VERSION 5.7 ;
  NOWIREEXTENSIONATPIN ON ;
  DIVIDERCHAR "/" ;
  BUSBITCHARS "[]" ;
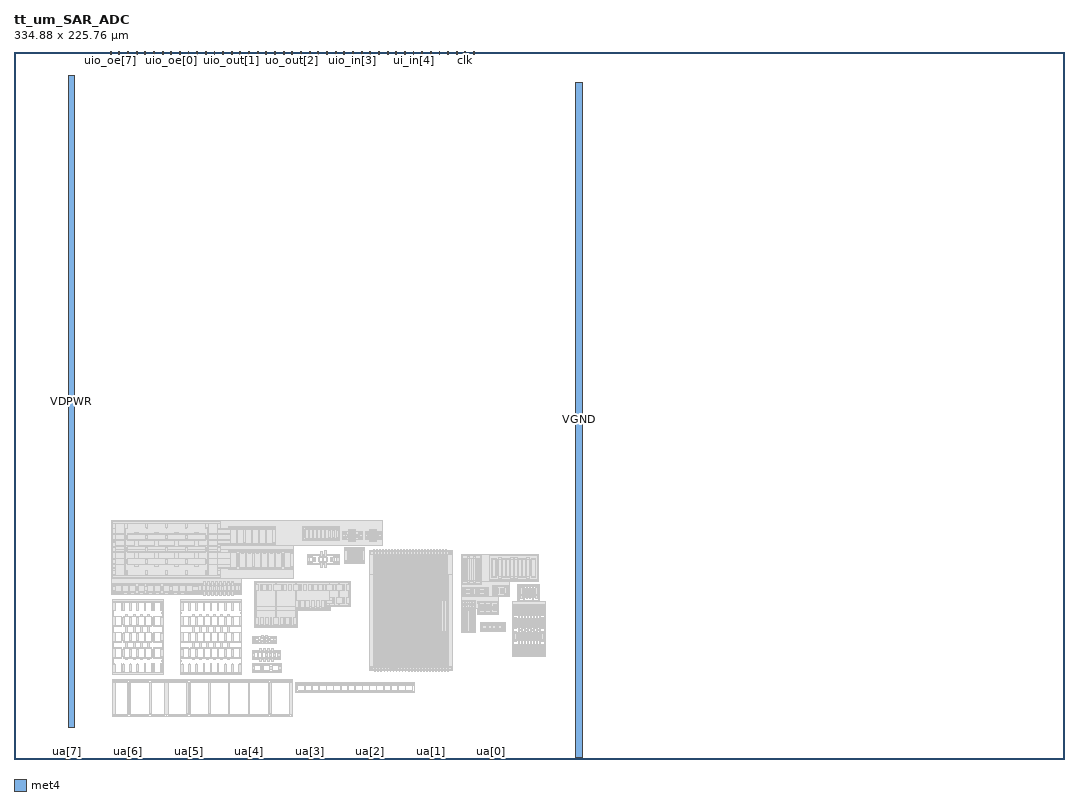
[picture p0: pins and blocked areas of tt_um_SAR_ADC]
MACRO tt_um_SAR_ADC
  CLASS BLOCK ;
  FOREIGN tt_um_SAR_ADC ;
  ORIGIN 0.000 0.000 ;
  SIZE 334.880 BY 225.760 ;
  PIN clk
    DIRECTION INPUT ;
    USE SIGNAL ;
    PORT
      LAYER met4 ;
        RECT 143.830 224.760 144.130 225.760 ;
    END
  END clk
  PIN ena
    DIRECTION INPUT ;
    USE SIGNAL ;
    PORT
      LAYER met4 ;
        RECT 146.590 224.760 146.890 225.760 ;
    END
  END ena
  PIN rst_n
    DIRECTION INPUT ;
    USE SIGNAL ;
    PORT
      LAYER met4 ;
        RECT 141.070 224.760 141.370 225.760 ;
    END
  END rst_n
  PIN ua[0]
    DIRECTION INOUT ;
    USE SIGNAL ;
    PORT
      LAYER met4 ;
        RECT 151.810 0.000 152.710 1.000 ;
    END
  END ua[0]
  PIN ua[1]
    DIRECTION INOUT ;
    USE SIGNAL ;
    PORT
      LAYER met4 ;
        RECT 132.490 0.000 133.390 1.000 ;
    END
  END ua[1]
  PIN ua[2]
    DIRECTION INOUT ;
    USE SIGNAL ;
    PORT
      LAYER met4 ;
        RECT 113.170 0.000 114.070 1.000 ;
    END
  END ua[2]
  PIN ua[3]
    DIRECTION INOUT ;
    USE SIGNAL ;
    PORT
      LAYER met4 ;
        RECT 93.850 0.000 94.750 1.000 ;
    END
  END ua[3]
  PIN ua[4]
    DIRECTION INOUT ;
    USE SIGNAL ;
    PORT
      LAYER met4 ;
        RECT 74.530 0.000 75.430 1.000 ;
    END
  END ua[4]
  PIN ua[5]
    DIRECTION INOUT ;
    USE SIGNAL ;
    PORT
      LAYER met4 ;
        RECT 55.210 0.000 56.110 1.000 ;
    END
  END ua[5]
  PIN ua[6]
    DIRECTION INOUT ;
    USE SIGNAL ;
    PORT
      LAYER met4 ;
        RECT 35.890 0.000 36.790 1.000 ;
    END
  END ua[6]
  PIN ua[7]
    DIRECTION INOUT ;
    USE SIGNAL ;
    PORT
      LAYER met4 ;
        RECT 16.570 0.000 17.470 1.000 ;
    END
  END ua[7]
  PIN ui_in[0]
    DIRECTION INPUT ;
    USE SIGNAL ;
    PORT
      LAYER met4 ;
        RECT 138.310 224.760 138.610 225.760 ;
    END
  END ui_in[0]
  PIN ui_in[1]
    DIRECTION INPUT ;
    USE SIGNAL ;
    PORT
      LAYER met4 ;
        RECT 135.550 224.760 135.850 225.760 ;
    END
  END ui_in[1]
  PIN ui_in[2]
    DIRECTION INPUT ;
    USE SIGNAL ;
    PORT
      LAYER met4 ;
        RECT 132.790 224.760 133.090 225.760 ;
    END
  END ui_in[2]
  PIN ui_in[3]
    DIRECTION INPUT ;
    USE SIGNAL ;
    PORT
      LAYER met4 ;
        RECT 130.030 224.760 130.330 225.760 ;
    END
  END ui_in[3]
  PIN ui_in[4]
    DIRECTION INPUT ;
    USE SIGNAL ;
    PORT
      LAYER met4 ;
        RECT 127.270 224.760 127.570 225.760 ;
    END
  END ui_in[4]
  PIN ui_in[5]
    DIRECTION INPUT ;
    USE SIGNAL ;
    PORT
      LAYER met4 ;
        RECT 124.510 224.760 124.810 225.760 ;
    END
  END ui_in[5]
  PIN ui_in[6]
    DIRECTION INPUT ;
    USE SIGNAL ;
    PORT
      LAYER met4 ;
        RECT 121.750 224.760 122.050 225.760 ;
    END
  END ui_in[6]
  PIN ui_in[7]
    DIRECTION INPUT ;
    USE SIGNAL ;
    PORT
      LAYER met4 ;
        RECT 118.990 224.760 119.290 225.760 ;
    END
  END ui_in[7]
  PIN uio_in[0]
    DIRECTION INPUT ;
    USE SIGNAL ;
    PORT
      LAYER met4 ;
        RECT 116.230 224.760 116.530 225.760 ;
    END
  END uio_in[0]
  PIN uio_in[1]
    DIRECTION INPUT ;
    USE SIGNAL ;
    PORT
      LAYER met4 ;
        RECT 113.470 224.760 113.770 225.760 ;
    END
  END uio_in[1]
  PIN uio_in[2]
    DIRECTION INPUT ;
    USE SIGNAL ;
    PORT
      LAYER met4 ;
        RECT 110.710 224.760 111.010 225.760 ;
    END
  END uio_in[2]
  PIN uio_in[3]
    DIRECTION INPUT ;
    USE SIGNAL ;
    PORT
      LAYER met4 ;
        RECT 107.950 224.760 108.250 225.760 ;
    END
  END uio_in[3]
  PIN uio_in[4]
    DIRECTION INPUT ;
    USE SIGNAL ;
    PORT
      LAYER met4 ;
        RECT 105.190 224.760 105.490 225.760 ;
    END
  END uio_in[4]
  PIN uio_in[5]
    DIRECTION INPUT ;
    USE SIGNAL ;
    PORT
      LAYER met4 ;
        RECT 102.430 224.760 102.730 225.760 ;
    END
  END uio_in[5]
  PIN uio_in[6]
    DIRECTION INPUT ;
    USE SIGNAL ;
    PORT
      LAYER met4 ;
        RECT 99.670 224.760 99.970 225.760 ;
    END
  END uio_in[6]
  PIN uio_in[7]
    DIRECTION INPUT ;
    USE SIGNAL ;
    PORT
      LAYER met4 ;
        RECT 96.910 224.760 97.210 225.760 ;
    END
  END uio_in[7]
  PIN uio_oe[0]
    DIRECTION OUTPUT ;
    USE SIGNAL ;
    PORT
      LAYER met4 ;
        RECT 49.990 224.760 50.290 225.760 ;
    END
  END uio_oe[0]
  PIN uio_oe[1]
    DIRECTION OUTPUT ;
    USE SIGNAL ;
    PORT
      LAYER met4 ;
        RECT 47.230 224.760 47.530 225.760 ;
    END
  END uio_oe[1]
  PIN uio_oe[2]
    DIRECTION OUTPUT ;
    USE SIGNAL ;
    PORT
      LAYER met4 ;
        RECT 44.470 224.760 44.770 225.760 ;
    END
  END uio_oe[2]
  PIN uio_oe[3]
    DIRECTION OUTPUT ;
    USE SIGNAL ;
    PORT
      LAYER met4 ;
        RECT 41.710 224.760 42.010 225.760 ;
    END
  END uio_oe[3]
  PIN uio_oe[4]
    DIRECTION OUTPUT ;
    USE SIGNAL ;
    PORT
      LAYER met4 ;
        RECT 38.950 224.760 39.250 225.760 ;
    END
  END uio_oe[4]
  PIN uio_oe[5]
    DIRECTION OUTPUT ;
    USE SIGNAL ;
    PORT
      LAYER met4 ;
        RECT 36.190 224.760 36.490 225.760 ;
    END
  END uio_oe[5]
  PIN uio_oe[6]
    DIRECTION OUTPUT ;
    USE SIGNAL ;
    PORT
      LAYER met4 ;
        RECT 33.430 224.760 33.730 225.760 ;
    END
  END uio_oe[6]
  PIN uio_oe[7]
    DIRECTION OUTPUT ;
    USE SIGNAL ;
    PORT
      LAYER met4 ;
        RECT 30.670 224.760 30.970 225.760 ;
    END
  END uio_oe[7]
  PIN uio_out[0]
    DIRECTION OUTPUT ;
    USE SIGNAL ;
    PORT
      LAYER met4 ;
        RECT 72.070 224.760 72.370 225.760 ;
    END
  END uio_out[0]
  PIN uio_out[1]
    DIRECTION OUTPUT ;
    USE SIGNAL ;
    PORT
      LAYER met4 ;
        RECT 69.310 224.760 69.610 225.760 ;
    END
  END uio_out[1]
  PIN uio_out[2]
    DIRECTION OUTPUT ;
    USE SIGNAL ;
    PORT
      LAYER met4 ;
        RECT 66.550 224.760 66.850 225.760 ;
    END
  END uio_out[2]
  PIN uio_out[3]
    DIRECTION OUTPUT ;
    USE SIGNAL ;
    PORT
      LAYER met4 ;
        RECT 63.790 224.760 64.090 225.760 ;
    END
  END uio_out[3]
  PIN uio_out[4]
    DIRECTION OUTPUT ;
    USE SIGNAL ;
    PORT
      LAYER met4 ;
        RECT 61.030 224.760 61.330 225.760 ;
    END
  END uio_out[4]
  PIN uio_out[5]
    DIRECTION OUTPUT ;
    USE SIGNAL ;
    PORT
      LAYER met4 ;
        RECT 58.270 224.760 58.570 225.760 ;
    END
  END uio_out[5]
  PIN uio_out[6]
    DIRECTION OUTPUT ;
    USE SIGNAL ;
    PORT
      LAYER met4 ;
        RECT 55.510 224.760 55.810 225.760 ;
    END
  END uio_out[6]
  PIN uio_out[7]
    DIRECTION OUTPUT ;
    USE SIGNAL ;
    PORT
      LAYER met4 ;
        RECT 52.750 224.760 53.050 225.760 ;
    END
  END uio_out[7]
  PIN uo_out[0]
    DIRECTION OUTPUT ;
    USE SIGNAL ;
    PORT
      LAYER met4 ;
        RECT 94.150 224.760 94.450 225.760 ;
    END
  END uo_out[0]
  PIN uo_out[1]
    DIRECTION OUTPUT ;
    USE SIGNAL ;
    PORT
      LAYER met4 ;
        RECT 91.390 224.760 91.690 225.760 ;
    END
  END uo_out[1]
  PIN uo_out[2]
    DIRECTION OUTPUT ;
    USE SIGNAL ;
    PORT
      LAYER met4 ;
        RECT 88.630 224.760 88.930 225.760 ;
    END
  END uo_out[2]
  PIN uo_out[3]
    DIRECTION OUTPUT ;
    USE SIGNAL ;
    PORT
      LAYER met4 ;
        RECT 85.870 224.760 86.170 225.760 ;
    END
  END uo_out[3]
  PIN uo_out[4]
    DIRECTION OUTPUT ;
    USE SIGNAL ;
    PORT
      LAYER met4 ;
        RECT 83.110 224.760 83.410 225.760 ;
    END
  END uo_out[4]
  PIN uo_out[5]
    DIRECTION OUTPUT ;
    USE SIGNAL ;
    PORT
      LAYER met4 ;
        RECT 80.350 224.760 80.650 225.760 ;
    END
  END uo_out[5]
  PIN uo_out[6]
    DIRECTION OUTPUT ;
    USE SIGNAL ;
    PORT
      LAYER met4 ;
        RECT 77.590 224.760 77.890 225.760 ;
    END
  END uo_out[6]
  PIN uo_out[7]
    DIRECTION OUTPUT ;
    USE SIGNAL ;
    PORT
      LAYER met4 ;
        RECT 74.830 224.760 75.130 225.760 ;
    END
  END uo_out[7]
  PIN VDPWR
    DIRECTION INOUT ;
    USE POWER ;
    PORT
      LAYER met4 ;
        RECT 17.400 9.940 19.400 218.050 ;
    END
  END VDPWR
  PIN VGND
    DIRECTION INOUT ;
    USE GROUND ;
    PORT
      LAYER met4 ;
        RECT 179.160 0.385 181.160 215.890 ;
    END
  END VGND
  OBS
      LAYER nwell ;
        RECT 31.225 68.130 117.555 76.010 ;
        RECT 31.225 66.700 89.210 68.130 ;
        RECT 31.225 57.720 89.215 66.700 ;
        RECT 31.225 52.520 72.515 57.720 ;
      LAYER pwell ;
        RECT 76.825 48.615 107.165 56.625 ;
        RECT 76.825 47.485 100.885 48.615 ;
        RECT 76.825 42.055 90.275 47.485 ;
      LAYER nwell ;
        RECT 113.240 28.260 139.870 66.450 ;
        RECT 142.580 56.720 167.245 65.225 ;
        RECT 142.580 51.740 158.070 56.720 ;
      LAYER pwell ;
        RECT 160.720 55.135 167.650 55.565 ;
      LAYER nwell ;
        RECT 142.580 47.900 154.585 51.740 ;
      LAYER pwell ;
        RECT 160.720 50.575 161.150 55.135 ;
        RECT 161.340 51.485 162.280 54.245 ;
        RECT 162.290 51.485 163.230 54.245 ;
        RECT 163.240 51.485 164.180 54.245 ;
        RECT 164.190 51.485 165.130 54.245 ;
        RECT 165.140 51.485 166.080 54.245 ;
        RECT 166.090 51.485 167.030 54.245 ;
        RECT 167.220 50.575 167.650 55.135 ;
        RECT 160.720 49.600 167.650 50.575 ;
        RECT 142.795 47.135 147.065 47.565 ;
        RECT 142.795 40.835 143.225 47.135 ;
        RECT 143.415 41.355 144.355 46.615 ;
        RECT 144.545 40.835 145.315 47.135 ;
        RECT 145.505 41.355 146.445 46.615 ;
        RECT 146.635 40.835 147.065 47.135 ;
      LAYER nwell ;
        RECT 147.915 46.165 154.585 47.900 ;
      LAYER pwell ;
        RECT 158.940 49.170 169.670 49.600 ;
        RECT 142.795 40.405 147.065 40.835 ;
        RECT 148.715 43.025 156.625 43.455 ;
        RECT 148.715 41.225 149.145 43.025 ;
        RECT 150.985 42.505 151.285 43.025 ;
        RECT 153.755 42.505 154.055 43.025 ;
        RECT 149.185 41.745 150.975 42.505 ;
        RECT 150.985 41.745 154.055 42.505 ;
        RECT 154.065 41.745 155.855 42.505 ;
        RECT 150.985 41.225 151.285 41.745 ;
        RECT 153.755 41.225 154.055 41.745 ;
        RECT 156.195 41.225 156.625 43.025 ;
        RECT 148.715 40.795 156.625 41.225 ;
        RECT 158.940 33.180 159.370 49.170 ;
        RECT 159.560 45.890 160.500 48.650 ;
        RECT 160.510 45.890 161.450 48.650 ;
        RECT 161.460 45.890 162.400 48.650 ;
        RECT 162.410 45.890 163.350 48.650 ;
        RECT 163.360 45.890 164.300 48.650 ;
        RECT 164.310 45.890 165.250 48.650 ;
        RECT 165.260 45.890 166.200 48.650 ;
        RECT 166.210 45.890 167.150 48.650 ;
        RECT 167.160 45.890 168.100 48.650 ;
        RECT 168.110 45.890 169.050 48.650 ;
        RECT 159.560 41.930 160.500 44.690 ;
        RECT 160.510 41.930 161.450 44.690 ;
        RECT 161.460 41.930 162.400 44.690 ;
        RECT 162.410 41.930 163.350 44.690 ;
        RECT 163.360 41.930 164.300 44.690 ;
        RECT 164.310 41.930 165.250 44.690 ;
        RECT 165.260 41.930 166.200 44.690 ;
        RECT 166.210 41.930 167.150 44.690 ;
        RECT 167.160 41.930 168.100 44.690 ;
        RECT 168.110 41.930 169.050 44.690 ;
        RECT 159.560 37.660 160.500 40.420 ;
        RECT 160.510 37.660 161.450 40.420 ;
        RECT 161.460 37.660 162.400 40.420 ;
        RECT 162.410 37.660 163.350 40.420 ;
        RECT 163.360 37.660 164.300 40.420 ;
        RECT 164.310 37.660 165.250 40.420 ;
        RECT 165.260 37.660 166.200 40.420 ;
        RECT 166.210 37.660 167.150 40.420 ;
        RECT 167.160 37.660 168.100 40.420 ;
        RECT 168.110 37.660 169.050 40.420 ;
        RECT 159.560 33.700 160.500 36.460 ;
        RECT 160.510 33.700 161.450 36.460 ;
        RECT 161.460 33.700 162.400 36.460 ;
        RECT 162.410 33.700 163.350 36.460 ;
        RECT 163.360 33.700 164.300 36.460 ;
        RECT 164.310 33.700 165.250 36.460 ;
        RECT 165.260 33.700 166.200 36.460 ;
        RECT 166.210 33.700 167.150 36.460 ;
        RECT 167.160 33.700 168.100 36.460 ;
        RECT 168.110 33.700 169.050 36.460 ;
        RECT 169.240 33.180 169.670 49.170 ;
        RECT 158.940 32.750 169.670 33.180 ;
      LAYER li1 ;
        RECT 31.555 75.535 65.725 75.830 ;
        RECT 31.555 75.345 31.725 75.535 ;
        RECT 31.555 58.485 31.765 75.345 ;
        RECT 32.355 75.150 35.355 75.320 ;
        RECT 36.205 75.150 42.205 75.320 ;
        RECT 42.495 75.150 48.495 75.320 ;
        RECT 48.785 75.150 54.785 75.320 ;
        RECT 55.075 75.150 61.075 75.320 ;
        RECT 61.925 75.150 64.925 75.320 ;
        RECT 65.555 75.225 65.725 75.535 ;
        RECT 32.125 73.645 32.295 74.935 ;
        RECT 35.415 73.645 35.585 74.935 ;
        RECT 35.975 73.645 36.145 74.935 ;
        RECT 42.265 73.645 42.435 74.935 ;
        RECT 48.555 73.645 48.725 74.935 ;
        RECT 54.845 73.645 55.015 74.935 ;
        RECT 61.135 73.645 61.305 74.935 ;
        RECT 61.695 73.645 61.865 74.935 ;
        RECT 64.985 73.645 65.155 74.935 ;
        RECT 32.355 71.615 35.355 71.785 ;
        RECT 36.205 71.615 42.205 71.785 ;
        RECT 42.495 71.615 48.495 71.785 ;
        RECT 48.785 71.615 54.785 71.785 ;
        RECT 55.075 71.615 61.075 71.785 ;
        RECT 61.925 71.615 64.925 71.785 ;
        RECT 32.125 70.110 32.295 71.400 ;
        RECT 35.415 70.110 35.585 71.400 ;
        RECT 35.975 70.110 36.145 71.400 ;
        RECT 42.265 70.110 42.435 71.400 ;
        RECT 48.555 70.110 48.725 71.400 ;
        RECT 54.845 70.110 55.015 71.400 ;
        RECT 61.135 70.110 61.305 71.400 ;
        RECT 61.695 70.110 61.865 71.400 ;
        RECT 64.985 70.110 65.155 71.400 ;
        RECT 32.355 69.725 35.355 69.895 ;
        RECT 36.205 69.725 42.205 69.895 ;
        RECT 42.495 69.725 48.495 69.895 ;
        RECT 48.785 69.725 54.785 69.895 ;
        RECT 55.075 69.725 61.075 69.895 ;
        RECT 61.925 69.725 64.925 69.895 ;
        RECT 32.355 67.725 35.355 67.895 ;
        RECT 36.205 67.725 42.205 67.895 ;
        RECT 42.495 67.725 48.495 67.895 ;
        RECT 48.785 67.725 54.785 67.895 ;
        RECT 55.075 67.725 61.075 67.895 ;
        RECT 61.925 67.725 64.925 67.895 ;
        RECT 32.125 66.220 32.295 67.510 ;
        RECT 35.415 66.220 35.585 67.510 ;
        RECT 35.975 66.220 36.145 67.510 ;
        RECT 42.265 66.220 42.435 67.510 ;
        RECT 48.555 66.220 48.725 67.510 ;
        RECT 54.845 66.220 55.015 67.510 ;
        RECT 61.135 66.220 61.305 67.510 ;
        RECT 61.695 66.220 61.865 67.510 ;
        RECT 64.985 66.220 65.155 67.510 ;
        RECT 32.355 65.835 35.355 66.005 ;
        RECT 36.205 65.835 42.205 66.005 ;
        RECT 42.495 65.835 48.495 66.005 ;
        RECT 48.785 65.835 54.785 66.005 ;
        RECT 55.075 65.835 61.075 66.005 ;
        RECT 61.925 65.835 64.925 66.005 ;
        RECT 32.355 63.835 35.355 64.005 ;
        RECT 36.205 63.835 42.205 64.005 ;
        RECT 42.495 63.835 48.495 64.005 ;
        RECT 48.785 63.835 54.785 64.005 ;
        RECT 55.075 63.835 61.075 64.005 ;
        RECT 61.925 63.835 64.925 64.005 ;
        RECT 32.125 62.330 32.295 63.620 ;
        RECT 35.415 62.330 35.585 63.620 ;
        RECT 35.975 62.330 36.145 63.620 ;
        RECT 42.265 62.330 42.435 63.620 ;
        RECT 48.555 62.330 48.725 63.620 ;
        RECT 54.845 62.330 55.015 63.620 ;
        RECT 61.135 62.330 61.305 63.620 ;
        RECT 61.695 62.330 61.865 63.620 ;
        RECT 64.985 62.330 65.155 63.620 ;
        RECT 32.355 61.945 35.355 62.115 ;
        RECT 36.205 61.945 42.205 62.115 ;
        RECT 42.495 61.945 48.495 62.115 ;
        RECT 48.785 61.945 54.785 62.115 ;
        RECT 55.075 61.945 61.075 62.115 ;
        RECT 61.925 61.945 64.925 62.115 ;
        RECT 32.125 58.795 32.295 60.085 ;
        RECT 35.415 58.795 35.585 60.085 ;
        RECT 35.975 58.795 36.145 60.085 ;
        RECT 42.265 58.795 42.435 60.085 ;
        RECT 48.555 58.795 48.725 60.085 ;
        RECT 54.845 58.795 55.015 60.085 ;
        RECT 61.135 58.795 61.305 60.085 ;
        RECT 61.695 58.795 61.865 60.085 ;
        RECT 64.985 58.795 65.155 60.085 ;
        RECT 31.555 58.170 31.725 58.485 ;
        RECT 32.355 58.410 35.355 58.580 ;
        RECT 36.205 58.410 42.205 58.580 ;
        RECT 42.495 58.410 48.495 58.580 ;
        RECT 48.785 58.410 54.785 58.580 ;
        RECT 55.075 58.410 61.075 58.580 ;
        RECT 61.925 58.410 64.925 58.580 ;
        RECT 65.460 58.450 65.725 75.225 ;
        RECT 68.290 73.885 83.340 74.055 ;
        RECT 68.290 68.145 68.460 73.885 ;
        RECT 69.090 73.375 71.090 73.545 ;
        RECT 71.380 73.375 73.380 73.545 ;
        RECT 73.670 73.375 75.670 73.545 ;
        RECT 75.960 73.375 77.960 73.545 ;
        RECT 78.250 73.375 80.250 73.545 ;
        RECT 80.540 73.375 82.540 73.545 ;
        RECT 68.860 68.870 69.030 73.160 ;
        RECT 71.150 68.870 71.320 73.160 ;
        RECT 73.440 68.870 73.610 73.160 ;
        RECT 75.730 68.870 75.900 73.160 ;
        RECT 78.020 68.870 78.190 73.160 ;
        RECT 80.310 68.870 80.480 73.160 ;
        RECT 82.600 68.870 82.770 73.160 ;
        RECT 69.090 68.485 71.090 68.655 ;
        RECT 71.380 68.485 73.380 68.655 ;
        RECT 73.670 68.485 75.670 68.655 ;
        RECT 75.960 68.485 77.960 68.655 ;
        RECT 78.250 68.485 80.250 68.655 ;
        RECT 80.540 68.485 82.540 68.655 ;
        RECT 83.170 68.145 83.340 73.885 ;
        RECT 92.145 73.795 103.775 73.965 ;
        RECT 92.145 69.805 92.315 73.795 ;
        RECT 93.010 73.285 94.010 73.455 ;
        RECT 94.300 73.285 95.300 73.455 ;
        RECT 95.590 73.285 96.590 73.455 ;
        RECT 96.880 73.285 97.880 73.455 ;
        RECT 98.170 73.285 99.170 73.455 ;
        RECT 99.460 73.285 100.460 73.455 ;
        RECT 100.750 73.285 101.750 73.455 ;
        RECT 102.040 73.285 103.040 73.455 ;
        RECT 92.780 70.530 92.950 73.070 ;
        RECT 94.070 70.530 94.240 73.070 ;
        RECT 95.360 70.530 95.530 73.070 ;
        RECT 96.650 70.530 96.820 73.070 ;
        RECT 97.940 70.530 98.110 73.070 ;
        RECT 99.230 70.530 99.400 73.070 ;
        RECT 100.520 70.530 100.690 73.070 ;
        RECT 101.810 70.530 101.980 73.070 ;
        RECT 103.100 70.530 103.270 73.070 ;
        RECT 93.010 70.145 94.010 70.315 ;
        RECT 94.300 70.145 95.300 70.315 ;
        RECT 95.590 70.145 96.590 70.315 ;
        RECT 96.880 70.145 97.880 70.315 ;
        RECT 98.170 70.145 99.170 70.315 ;
        RECT 99.460 70.145 100.460 70.315 ;
        RECT 100.750 70.145 101.750 70.315 ;
        RECT 102.040 70.145 103.040 70.315 ;
        RECT 103.605 69.805 103.775 73.795 ;
        RECT 104.750 72.445 111.020 72.615 ;
        RECT 104.750 70.075 104.920 72.445 ;
        RECT 105.550 71.935 105.900 72.105 ;
        RECT 106.750 71.935 107.100 72.105 ;
        RECT 107.390 71.935 107.740 72.105 ;
        RECT 108.030 71.935 108.380 72.105 ;
        RECT 108.670 71.935 109.020 72.105 ;
        RECT 109.870 71.935 110.220 72.105 ;
        RECT 105.320 70.800 105.490 71.720 ;
        RECT 105.960 70.800 106.130 71.720 ;
        RECT 106.520 70.800 106.690 71.720 ;
        RECT 107.160 70.800 107.330 71.720 ;
        RECT 107.800 70.800 107.970 71.720 ;
        RECT 108.440 70.800 108.610 71.720 ;
        RECT 109.080 70.800 109.250 71.720 ;
        RECT 109.640 70.800 109.810 71.720 ;
        RECT 110.280 70.800 110.450 71.720 ;
        RECT 105.550 70.415 105.900 70.585 ;
        RECT 106.750 70.415 107.100 70.585 ;
        RECT 107.390 70.415 107.740 70.585 ;
        RECT 108.030 70.415 108.380 70.585 ;
        RECT 108.670 70.415 109.020 70.585 ;
        RECT 109.870 70.415 110.220 70.585 ;
        RECT 110.850 70.075 111.020 72.445 ;
        RECT 104.750 69.905 111.020 70.075 ;
        RECT 112.030 72.445 117.180 72.615 ;
        RECT 112.030 70.075 112.200 72.445 ;
        RECT 112.830 71.935 113.180 72.105 ;
        RECT 113.470 71.935 113.820 72.105 ;
        RECT 114.110 71.935 114.460 72.105 ;
        RECT 114.750 71.935 115.100 72.105 ;
        RECT 115.390 71.935 115.740 72.105 ;
        RECT 116.030 71.935 116.380 72.105 ;
        RECT 112.600 70.800 112.770 71.720 ;
        RECT 113.240 70.800 113.410 71.720 ;
        RECT 113.880 70.800 114.050 71.720 ;
        RECT 114.520 70.800 114.690 71.720 ;
        RECT 115.160 70.800 115.330 71.720 ;
        RECT 115.800 70.800 115.970 71.720 ;
        RECT 116.440 70.800 116.610 71.720 ;
        RECT 112.830 70.415 113.180 70.585 ;
        RECT 113.470 70.415 113.820 70.585 ;
        RECT 114.110 70.415 114.460 70.585 ;
        RECT 114.750 70.415 115.100 70.585 ;
        RECT 115.390 70.415 115.740 70.585 ;
        RECT 116.030 70.415 116.380 70.585 ;
        RECT 117.010 70.075 117.180 72.445 ;
        RECT 112.030 69.905 117.180 70.075 ;
        RECT 92.145 69.635 103.775 69.805 ;
        RECT 68.290 67.975 83.340 68.145 ;
        RECT 105.430 67.295 111.860 67.465 ;
        RECT 68.285 66.260 89.035 66.430 ;
        RECT 68.285 60.520 68.455 66.260 ;
        RECT 69.085 65.750 71.085 65.920 ;
        RECT 71.935 65.750 73.935 65.920 ;
        RECT 74.225 65.750 76.225 65.920 ;
        RECT 76.515 65.750 78.515 65.920 ;
        RECT 78.805 65.750 80.805 65.920 ;
        RECT 81.095 65.750 83.095 65.920 ;
        RECT 83.385 65.750 85.385 65.920 ;
        RECT 86.235 65.750 88.235 65.920 ;
        RECT 68.855 61.245 69.025 65.535 ;
        RECT 71.145 61.245 71.315 65.535 ;
        RECT 71.705 61.245 71.875 65.535 ;
        RECT 73.995 61.245 74.165 65.535 ;
        RECT 76.285 61.245 76.455 65.535 ;
        RECT 78.575 61.245 78.745 65.535 ;
        RECT 80.865 61.245 81.035 65.535 ;
        RECT 83.155 61.245 83.325 65.535 ;
        RECT 85.445 61.245 85.615 65.535 ;
        RECT 86.005 61.245 86.175 65.535 ;
        RECT 88.295 61.245 88.465 65.535 ;
        RECT 69.085 60.860 71.085 61.030 ;
        RECT 71.935 60.860 73.935 61.030 ;
        RECT 74.225 60.860 76.225 61.030 ;
        RECT 76.515 60.860 78.515 61.030 ;
        RECT 78.805 60.860 80.805 61.030 ;
        RECT 81.095 60.860 83.095 61.030 ;
        RECT 83.385 60.860 85.385 61.030 ;
        RECT 86.235 60.860 88.235 61.030 ;
        RECT 88.865 60.520 89.035 66.260 ;
        RECT 93.540 64.950 103.710 65.120 ;
        RECT 93.540 62.300 93.710 64.950 ;
        RECT 94.340 64.440 95.340 64.610 ;
        RECT 97.480 64.440 98.480 64.610 ;
        RECT 98.770 64.440 99.770 64.610 ;
        RECT 101.910 64.440 102.910 64.610 ;
        RECT 94.110 62.980 94.280 64.270 ;
        RECT 95.400 62.980 95.570 64.270 ;
        RECT 95.960 62.980 96.130 64.270 ;
        RECT 97.250 62.980 97.420 64.270 ;
        RECT 98.540 62.980 98.710 64.270 ;
        RECT 99.830 62.980 100.000 64.270 ;
        RECT 101.120 62.980 101.290 64.270 ;
        RECT 101.680 62.980 101.850 64.270 ;
        RECT 102.970 62.980 103.140 64.270 ;
        RECT 94.340 62.640 95.340 62.810 ;
        RECT 97.480 62.640 98.480 62.810 ;
        RECT 98.770 62.640 99.770 62.810 ;
        RECT 101.910 62.640 102.910 62.810 ;
        RECT 103.540 62.300 103.710 64.950 ;
        RECT 93.540 62.130 103.710 62.300 ;
        RECT 105.430 62.395 105.600 67.295 ;
        RECT 106.230 66.785 106.580 66.955 ;
        RECT 106.870 66.785 107.220 66.955 ;
        RECT 107.510 66.785 107.860 66.955 ;
        RECT 108.150 66.785 108.500 66.955 ;
        RECT 108.790 66.785 109.140 66.955 ;
        RECT 109.430 66.785 109.780 66.955 ;
        RECT 110.070 66.785 110.420 66.955 ;
        RECT 110.710 66.785 111.060 66.955 ;
        RECT 106.000 63.075 106.170 66.615 ;
        RECT 106.640 63.075 106.810 66.615 ;
        RECT 107.280 63.075 107.450 66.615 ;
        RECT 107.920 63.075 108.090 66.615 ;
        RECT 108.560 63.075 108.730 66.615 ;
        RECT 109.200 63.075 109.370 66.615 ;
        RECT 109.840 63.075 110.010 66.615 ;
        RECT 110.480 63.075 110.650 66.615 ;
        RECT 111.120 63.075 111.290 66.615 ;
        RECT 106.230 62.735 106.580 62.905 ;
        RECT 106.870 62.735 107.220 62.905 ;
        RECT 107.510 62.735 107.860 62.905 ;
        RECT 108.150 62.735 108.500 62.905 ;
        RECT 108.790 62.735 109.140 62.905 ;
        RECT 109.430 62.735 109.780 62.905 ;
        RECT 110.070 62.735 110.420 62.905 ;
        RECT 110.710 62.735 111.060 62.905 ;
        RECT 111.690 62.395 111.860 67.295 ;
        RECT 105.430 62.225 111.860 62.395 ;
        RECT 113.420 66.100 139.690 66.270 ;
        RECT 68.285 60.350 89.035 60.520 ;
        RECT 65.555 58.170 65.725 58.450 ;
        RECT 31.555 57.900 65.725 58.170 ;
        RECT 77.005 56.275 106.985 56.445 ;
        RECT 31.405 55.860 57.855 56.030 ;
        RECT 31.405 52.870 31.575 55.860 ;
        RECT 32.205 55.350 34.205 55.520 ;
        RECT 34.495 55.350 36.495 55.520 ;
        RECT 36.785 55.350 38.785 55.520 ;
        RECT 39.635 55.350 41.635 55.520 ;
        RECT 42.485 55.350 44.485 55.520 ;
        RECT 44.775 55.350 46.775 55.520 ;
        RECT 47.625 55.350 49.625 55.520 ;
        RECT 50.475 55.350 52.475 55.520 ;
        RECT 52.765 55.350 54.765 55.520 ;
        RECT 55.055 55.350 57.055 55.520 ;
        RECT 31.975 53.595 32.145 55.135 ;
        RECT 34.265 53.595 34.435 55.135 ;
        RECT 36.555 53.595 36.725 55.135 ;
        RECT 38.845 53.595 39.015 55.135 ;
        RECT 39.405 53.595 39.575 55.135 ;
        RECT 41.695 53.595 41.865 55.135 ;
        RECT 42.255 53.595 42.425 55.135 ;
        RECT 44.545 53.595 44.715 55.135 ;
        RECT 46.835 53.595 47.005 55.135 ;
        RECT 47.395 53.595 47.565 55.135 ;
        RECT 49.685 53.595 49.855 55.135 ;
        RECT 50.245 53.595 50.415 55.135 ;
        RECT 52.535 53.595 52.705 55.135 ;
        RECT 54.825 53.595 54.995 55.135 ;
        RECT 57.115 53.595 57.285 55.135 ;
        RECT 32.205 53.210 34.205 53.380 ;
        RECT 34.495 53.210 36.495 53.380 ;
        RECT 36.785 53.210 38.785 53.380 ;
        RECT 39.635 53.210 41.635 53.380 ;
        RECT 42.485 53.210 44.485 53.380 ;
        RECT 44.775 53.210 46.775 53.380 ;
        RECT 47.625 53.210 49.625 53.380 ;
        RECT 50.475 53.210 52.475 53.380 ;
        RECT 52.765 53.210 54.765 53.380 ;
        RECT 55.055 53.210 57.055 53.380 ;
        RECT 57.685 52.870 57.855 55.860 ;
        RECT 58.125 55.795 72.335 55.965 ;
        RECT 58.125 53.055 58.295 55.795 ;
        RECT 58.925 55.285 59.925 55.455 ;
        RECT 60.215 55.285 61.215 55.455 ;
        RECT 61.505 55.285 62.505 55.455 ;
        RECT 62.795 55.285 63.795 55.455 ;
        RECT 64.085 55.285 65.085 55.455 ;
        RECT 65.375 55.285 66.375 55.455 ;
        RECT 66.665 55.285 67.665 55.455 ;
        RECT 67.955 55.285 68.955 55.455 ;
        RECT 69.245 55.285 70.245 55.455 ;
        RECT 70.535 55.285 71.535 55.455 ;
        RECT 58.695 53.780 58.865 55.070 ;
        RECT 59.985 53.780 60.155 55.070 ;
        RECT 61.275 53.780 61.445 55.070 ;
        RECT 62.565 53.780 62.735 55.070 ;
        RECT 63.855 53.780 64.025 55.070 ;
        RECT 65.145 53.780 65.315 55.070 ;
        RECT 66.435 53.780 66.605 55.070 ;
        RECT 67.725 53.780 67.895 55.070 ;
        RECT 69.015 53.780 69.185 55.070 ;
        RECT 70.305 53.780 70.475 55.070 ;
        RECT 71.595 53.780 71.765 55.070 ;
        RECT 58.925 53.395 59.925 53.565 ;
        RECT 60.215 53.395 61.215 53.565 ;
        RECT 61.505 53.395 62.505 53.565 ;
        RECT 62.795 53.395 63.795 53.565 ;
        RECT 64.085 53.395 65.085 53.565 ;
        RECT 65.375 53.395 66.375 53.565 ;
        RECT 66.665 53.395 67.665 53.565 ;
        RECT 67.955 53.395 68.955 53.565 ;
        RECT 69.245 53.395 70.245 53.565 ;
        RECT 70.535 53.395 71.535 53.565 ;
        RECT 72.165 53.055 72.335 55.795 ;
        RECT 58.125 52.885 72.335 53.055 ;
        RECT 31.405 52.700 57.855 52.870 ;
        RECT 31.375 50.530 47.545 50.740 ;
        RECT 31.375 50.300 31.545 50.530 ;
        RECT 31.375 27.635 31.575 50.300 ;
        RECT 32.175 50.060 34.175 50.230 ;
        RECT 35.025 50.060 37.025 50.230 ;
        RECT 37.315 50.060 39.315 50.230 ;
        RECT 39.605 50.060 41.605 50.230 ;
        RECT 41.895 50.060 43.895 50.230 ;
        RECT 44.745 50.060 46.745 50.230 ;
        RECT 31.945 47.350 32.115 49.890 ;
        RECT 34.235 47.350 34.405 49.890 ;
        RECT 34.795 47.350 34.965 49.890 ;
        RECT 37.085 47.350 37.255 49.890 ;
        RECT 39.375 47.350 39.545 49.890 ;
        RECT 41.665 47.350 41.835 49.890 ;
        RECT 43.955 47.350 44.125 49.890 ;
        RECT 44.515 47.350 44.685 49.890 ;
        RECT 46.805 47.350 46.975 49.890 ;
        RECT 32.175 45.320 34.175 45.490 ;
        RECT 35.025 45.320 37.025 45.490 ;
        RECT 37.315 45.320 39.315 45.490 ;
        RECT 39.605 45.320 41.605 45.490 ;
        RECT 41.895 45.320 43.895 45.490 ;
        RECT 44.745 45.320 46.745 45.490 ;
        RECT 31.945 42.610 32.115 45.150 ;
        RECT 34.235 42.610 34.405 45.150 ;
        RECT 34.795 42.610 34.965 45.150 ;
        RECT 37.085 42.610 37.255 45.150 ;
        RECT 39.375 42.610 39.545 45.150 ;
        RECT 41.665 42.610 41.835 45.150 ;
        RECT 43.955 42.610 44.125 45.150 ;
        RECT 44.515 42.610 44.685 45.150 ;
        RECT 46.805 42.610 46.975 45.150 ;
        RECT 32.175 42.270 34.175 42.440 ;
        RECT 35.025 42.270 37.025 42.440 ;
        RECT 37.315 42.270 39.315 42.440 ;
        RECT 39.605 42.270 41.605 42.440 ;
        RECT 41.895 42.270 43.895 42.440 ;
        RECT 44.745 42.270 46.745 42.440 ;
        RECT 32.175 40.275 34.175 40.445 ;
        RECT 35.025 40.270 37.025 40.440 ;
        RECT 37.315 40.270 39.315 40.440 ;
        RECT 39.605 40.270 41.605 40.440 ;
        RECT 41.895 40.270 43.895 40.440 ;
        RECT 44.745 40.270 46.745 40.440 ;
        RECT 31.945 37.565 32.115 40.105 ;
        RECT 34.235 37.565 34.405 40.105 ;
        RECT 34.795 37.560 34.965 40.100 ;
        RECT 37.085 37.560 37.255 40.100 ;
        RECT 39.375 37.560 39.545 40.100 ;
        RECT 41.665 37.560 41.835 40.100 ;
        RECT 43.955 37.560 44.125 40.100 ;
        RECT 44.515 37.560 44.685 40.100 ;
        RECT 46.805 37.560 46.975 40.100 ;
        RECT 32.175 37.225 34.175 37.395 ;
        RECT 35.025 37.220 37.025 37.390 ;
        RECT 37.315 37.220 39.315 37.390 ;
        RECT 39.605 37.220 41.605 37.390 ;
        RECT 41.895 37.220 43.895 37.390 ;
        RECT 44.745 37.220 46.745 37.390 ;
        RECT 32.175 35.220 34.175 35.390 ;
        RECT 35.025 35.220 37.025 35.390 ;
        RECT 37.315 35.220 39.315 35.390 ;
        RECT 39.605 35.220 41.605 35.390 ;
        RECT 41.895 35.220 43.895 35.390 ;
        RECT 44.745 35.220 46.745 35.390 ;
        RECT 31.945 32.510 32.115 35.050 ;
        RECT 34.235 32.510 34.405 35.050 ;
        RECT 34.795 32.510 34.965 35.050 ;
        RECT 37.085 32.510 37.255 35.050 ;
        RECT 39.375 32.510 39.545 35.050 ;
        RECT 41.665 32.510 41.835 35.050 ;
        RECT 43.955 32.510 44.125 35.050 ;
        RECT 44.515 32.510 44.685 35.050 ;
        RECT 46.805 32.510 46.975 35.050 ;
        RECT 32.175 32.170 34.175 32.340 ;
        RECT 35.025 32.170 37.025 32.340 ;
        RECT 37.315 32.170 39.315 32.340 ;
        RECT 39.605 32.170 41.605 32.340 ;
        RECT 41.895 32.170 43.895 32.340 ;
        RECT 44.745 32.170 46.745 32.340 ;
        RECT 31.945 27.770 32.115 30.310 ;
        RECT 34.235 27.770 34.405 30.310 ;
        RECT 34.795 27.770 34.965 30.310 ;
        RECT 37.085 27.770 37.255 30.310 ;
        RECT 39.375 27.770 39.545 30.310 ;
        RECT 41.665 27.770 41.835 30.310 ;
        RECT 43.955 27.770 44.125 30.310 ;
        RECT 44.515 27.770 44.685 30.310 ;
        RECT 46.805 27.770 46.975 30.310 ;
        RECT 31.375 27.210 31.545 27.635 ;
        RECT 32.175 27.430 34.175 27.600 ;
        RECT 35.025 27.430 37.025 27.600 ;
        RECT 37.315 27.430 39.315 27.600 ;
        RECT 39.605 27.430 41.605 27.600 ;
        RECT 41.895 27.430 43.895 27.600 ;
        RECT 44.745 27.430 46.745 27.600 ;
        RECT 47.375 27.210 47.545 50.530 ;
        RECT 31.375 26.920 47.545 27.210 ;
        RECT 53.025 50.520 72.660 50.740 ;
        RECT 53.025 27.120 53.195 50.520 ;
        RECT 53.830 50.060 55.830 50.230 ;
        RECT 56.120 50.060 58.120 50.230 ;
        RECT 58.410 50.060 60.410 50.230 ;
        RECT 60.700 50.060 62.700 50.230 ;
        RECT 62.990 50.060 64.990 50.230 ;
        RECT 65.280 50.060 67.280 50.230 ;
        RECT 67.570 50.060 69.570 50.230 ;
        RECT 69.860 50.060 71.860 50.230 ;
        RECT 53.600 47.350 53.770 49.890 ;
        RECT 55.890 47.350 56.060 49.890 ;
        RECT 58.180 47.350 58.350 49.890 ;
        RECT 60.470 47.350 60.640 49.890 ;
        RECT 62.760 47.350 62.930 49.890 ;
        RECT 65.050 47.350 65.220 49.890 ;
        RECT 67.340 47.350 67.510 49.890 ;
        RECT 69.630 47.350 69.800 49.890 ;
        RECT 71.920 47.350 72.090 49.890 ;
        RECT 53.825 45.320 55.825 45.490 ;
        RECT 56.115 45.320 58.115 45.490 ;
        RECT 58.405 45.320 60.405 45.490 ;
        RECT 60.695 45.320 62.695 45.490 ;
        RECT 62.985 45.320 64.985 45.490 ;
        RECT 65.275 45.320 67.275 45.490 ;
        RECT 67.565 45.320 69.565 45.490 ;
        RECT 69.855 45.320 71.855 45.490 ;
        RECT 53.595 42.610 53.765 45.150 ;
        RECT 55.885 42.610 56.055 45.150 ;
        RECT 58.175 42.610 58.345 45.150 ;
        RECT 60.465 42.610 60.635 45.150 ;
        RECT 62.755 42.610 62.925 45.150 ;
        RECT 65.045 42.610 65.215 45.150 ;
        RECT 67.335 42.610 67.505 45.150 ;
        RECT 69.625 42.610 69.795 45.150 ;
        RECT 71.915 42.610 72.085 45.150 ;
        RECT 53.825 42.270 55.825 42.440 ;
        RECT 56.115 42.270 58.115 42.440 ;
        RECT 58.405 42.270 60.405 42.440 ;
        RECT 60.695 42.270 62.695 42.440 ;
        RECT 62.985 42.270 64.985 42.440 ;
        RECT 65.275 42.270 67.275 42.440 ;
        RECT 67.565 42.270 69.565 42.440 ;
        RECT 69.855 42.270 71.855 42.440 ;
        RECT 53.825 40.270 55.825 40.440 ;
        RECT 56.115 40.270 58.115 40.440 ;
        RECT 58.405 40.270 60.405 40.440 ;
        RECT 60.695 40.270 62.695 40.440 ;
        RECT 62.985 40.270 64.985 40.440 ;
        RECT 65.275 40.270 67.275 40.440 ;
        RECT 67.565 40.270 69.565 40.440 ;
        RECT 69.855 40.270 71.855 40.440 ;
        RECT 53.595 37.560 53.765 40.100 ;
        RECT 55.885 37.560 56.055 40.100 ;
        RECT 58.175 37.560 58.345 40.100 ;
        RECT 60.465 37.560 60.635 40.100 ;
        RECT 62.755 37.560 62.925 40.100 ;
        RECT 65.045 37.560 65.215 40.100 ;
        RECT 67.335 37.560 67.505 40.100 ;
        RECT 69.625 37.560 69.795 40.100 ;
        RECT 71.915 37.560 72.085 40.100 ;
        RECT 53.825 37.220 55.825 37.390 ;
        RECT 56.115 37.220 58.115 37.390 ;
        RECT 58.405 37.220 60.405 37.390 ;
        RECT 60.695 37.220 62.695 37.390 ;
        RECT 62.985 37.220 64.985 37.390 ;
        RECT 65.275 37.220 67.275 37.390 ;
        RECT 67.565 37.220 69.565 37.390 ;
        RECT 69.855 37.220 71.855 37.390 ;
        RECT 53.825 35.220 55.825 35.390 ;
        RECT 56.115 35.220 58.115 35.390 ;
        RECT 58.405 35.220 60.405 35.390 ;
        RECT 60.695 35.220 62.695 35.390 ;
        RECT 62.985 35.220 64.985 35.390 ;
        RECT 65.275 35.220 67.275 35.390 ;
        RECT 67.565 35.220 69.565 35.390 ;
        RECT 69.855 35.220 71.855 35.390 ;
        RECT 53.595 32.510 53.765 35.050 ;
        RECT 55.885 32.510 56.055 35.050 ;
        RECT 58.175 32.510 58.345 35.050 ;
        RECT 60.465 32.510 60.635 35.050 ;
        RECT 62.755 32.510 62.925 35.050 ;
        RECT 65.045 32.510 65.215 35.050 ;
        RECT 67.335 32.510 67.505 35.050 ;
        RECT 69.625 32.510 69.795 35.050 ;
        RECT 71.915 32.510 72.085 35.050 ;
        RECT 53.825 32.170 55.825 32.340 ;
        RECT 56.115 32.170 58.115 32.340 ;
        RECT 58.405 32.170 60.405 32.340 ;
        RECT 60.695 32.170 62.695 32.340 ;
        RECT 62.985 32.170 64.985 32.340 ;
        RECT 65.275 32.170 67.275 32.340 ;
        RECT 67.565 32.170 69.565 32.340 ;
        RECT 69.855 32.170 71.855 32.340 ;
        RECT 53.595 27.770 53.765 30.310 ;
        RECT 55.885 27.770 56.055 30.310 ;
        RECT 58.175 27.770 58.345 30.310 ;
        RECT 60.465 27.770 60.635 30.310 ;
        RECT 62.755 27.770 62.925 30.310 ;
        RECT 65.045 27.770 65.215 30.310 ;
        RECT 67.335 27.770 67.505 30.310 ;
        RECT 69.625 27.770 69.795 30.310 ;
        RECT 71.915 27.770 72.085 30.310 ;
        RECT 53.825 27.430 55.825 27.600 ;
        RECT 56.115 27.430 58.115 27.600 ;
        RECT 58.405 27.430 60.405 27.600 ;
        RECT 60.695 27.430 62.695 27.600 ;
        RECT 62.985 27.430 64.985 27.600 ;
        RECT 65.275 27.430 67.275 27.600 ;
        RECT 67.565 27.430 69.565 27.600 ;
        RECT 69.855 27.430 71.855 27.600 ;
        RECT 72.490 27.120 72.660 50.520 ;
        RECT 77.005 42.405 77.175 56.275 ;
        RECT 77.655 53.635 78.005 55.795 ;
        RECT 78.485 53.635 78.835 55.795 ;
        RECT 79.315 53.635 79.665 55.795 ;
        RECT 80.145 53.635 80.495 55.795 ;
        RECT 80.975 53.635 81.325 55.795 ;
        RECT 81.805 53.635 82.155 55.795 ;
        RECT 82.635 53.635 82.985 55.795 ;
        RECT 77.655 42.885 78.005 45.045 ;
        RECT 78.485 42.885 78.835 45.045 ;
        RECT 79.315 42.885 79.665 45.045 ;
        RECT 80.145 42.885 80.495 45.045 ;
        RECT 80.975 42.885 81.325 45.045 ;
        RECT 81.805 42.885 82.155 45.045 ;
        RECT 82.635 42.885 82.985 45.045 ;
        RECT 83.465 42.405 83.635 56.275 ;
        RECT 84.115 53.635 84.465 55.795 ;
        RECT 84.945 53.635 85.295 55.795 ;
        RECT 85.775 53.635 86.125 55.795 ;
        RECT 86.605 53.635 86.955 55.795 ;
        RECT 87.435 53.635 87.785 55.795 ;
        RECT 88.265 53.635 88.615 55.795 ;
        RECT 89.095 53.635 89.445 55.795 ;
        RECT 89.925 47.835 90.095 56.275 ;
        RECT 90.575 53.635 90.925 55.795 ;
        RECT 91.405 53.635 91.755 55.795 ;
        RECT 92.235 53.635 92.585 55.795 ;
        RECT 93.065 53.635 93.415 55.795 ;
        RECT 93.895 53.635 94.245 55.795 ;
        RECT 94.725 53.635 95.075 55.795 ;
        RECT 95.555 53.635 95.905 55.795 ;
        RECT 96.385 53.635 96.735 55.795 ;
        RECT 97.215 53.635 97.565 55.795 ;
        RECT 98.045 53.635 98.395 55.795 ;
        RECT 98.875 53.635 99.225 55.795 ;
        RECT 99.705 53.635 100.055 55.795 ;
        RECT 90.575 48.315 90.925 50.475 ;
        RECT 91.405 48.315 91.755 50.475 ;
        RECT 92.235 48.315 92.585 50.475 ;
        RECT 93.065 48.315 93.415 50.475 ;
        RECT 93.895 48.315 94.245 50.475 ;
        RECT 94.725 48.315 95.075 50.475 ;
        RECT 95.555 48.315 95.905 50.475 ;
        RECT 96.385 48.315 96.735 50.475 ;
        RECT 97.215 48.315 97.565 50.475 ;
        RECT 98.045 48.315 98.395 50.475 ;
        RECT 98.875 48.315 99.225 50.475 ;
        RECT 99.705 48.315 100.055 50.475 ;
        RECT 100.535 48.965 100.705 56.275 ;
        RECT 101.185 53.635 101.535 55.795 ;
        RECT 102.015 53.635 102.365 55.795 ;
        RECT 102.845 53.635 103.195 55.795 ;
        RECT 101.185 49.445 101.535 51.605 ;
        RECT 102.015 49.445 102.365 51.605 ;
        RECT 102.845 49.445 103.195 51.605 ;
        RECT 103.675 48.965 103.845 56.275 ;
        RECT 104.325 53.635 104.675 55.795 ;
        RECT 105.155 53.635 105.505 55.795 ;
        RECT 105.985 53.635 106.335 55.795 ;
        RECT 104.325 49.445 104.675 51.605 ;
        RECT 105.155 49.445 105.505 51.605 ;
        RECT 105.985 49.445 106.335 51.605 ;
        RECT 106.815 48.965 106.985 56.275 ;
        RECT 100.535 48.795 106.985 48.965 ;
        RECT 100.535 47.835 100.705 48.795 ;
        RECT 89.925 47.665 100.705 47.835 ;
        RECT 84.115 42.885 84.465 45.045 ;
        RECT 84.945 42.885 85.295 45.045 ;
        RECT 85.775 42.885 86.125 45.045 ;
        RECT 86.605 42.885 86.955 45.045 ;
        RECT 87.435 42.885 87.785 45.045 ;
        RECT 88.265 42.885 88.615 45.045 ;
        RECT 89.095 42.885 89.445 45.045 ;
        RECT 89.925 42.405 90.095 47.665 ;
        RECT 77.005 42.235 90.095 42.405 ;
        RECT 76.075 39.010 83.665 39.180 ;
        RECT 76.075 37.110 76.245 39.010 ;
        RECT 76.875 38.500 77.875 38.670 ;
        RECT 78.725 38.500 79.725 38.670 ;
        RECT 80.015 38.500 81.015 38.670 ;
        RECT 81.865 38.500 82.865 38.670 ;
        RECT 76.645 37.790 76.815 38.330 ;
        RECT 77.935 37.790 78.105 38.330 ;
        RECT 78.495 37.790 78.665 38.330 ;
        RECT 79.785 37.790 79.955 38.330 ;
        RECT 81.075 37.790 81.245 38.330 ;
        RECT 81.635 37.790 81.805 38.330 ;
        RECT 82.925 37.790 83.095 38.330 ;
        RECT 76.875 37.450 77.875 37.620 ;
        RECT 78.725 37.450 79.725 37.620 ;
        RECT 80.015 37.450 81.015 37.620 ;
        RECT 81.865 37.450 82.865 37.620 ;
        RECT 83.495 37.110 83.665 39.010 ;
        RECT 76.075 36.940 83.665 37.110 ;
        RECT 75.980 34.550 85.030 34.720 ;
        RECT 75.980 31.900 76.150 34.550 ;
        RECT 76.780 34.040 77.780 34.210 ;
        RECT 78.070 34.040 79.070 34.210 ;
        RECT 79.360 34.040 80.360 34.210 ;
        RECT 80.650 34.040 81.650 34.210 ;
        RECT 81.940 34.040 82.940 34.210 ;
        RECT 83.230 34.040 84.230 34.210 ;
        RECT 76.550 32.580 76.720 33.870 ;
        RECT 77.840 32.580 78.010 33.870 ;
        RECT 79.130 32.580 79.300 33.870 ;
        RECT 80.420 32.580 80.590 33.870 ;
        RECT 81.710 32.580 81.880 33.870 ;
        RECT 83.000 32.580 83.170 33.870 ;
        RECT 84.290 32.580 84.460 33.870 ;
        RECT 76.780 32.240 77.780 32.410 ;
        RECT 78.070 32.240 79.070 32.410 ;
        RECT 79.360 32.240 80.360 32.410 ;
        RECT 80.650 32.240 81.650 32.410 ;
        RECT 81.940 32.240 82.940 32.410 ;
        RECT 83.230 32.240 84.230 32.410 ;
        RECT 84.860 31.900 85.030 34.550 ;
        RECT 75.980 31.730 85.030 31.900 ;
        RECT 75.980 30.240 85.280 30.410 ;
        RECT 75.980 27.840 76.150 30.240 ;
        RECT 76.780 29.730 78.780 29.900 ;
        RECT 79.630 29.730 81.630 29.900 ;
        RECT 82.480 29.730 84.480 29.900 ;
        RECT 76.550 28.520 76.720 29.560 ;
        RECT 78.840 28.520 79.010 29.560 ;
        RECT 79.400 28.520 79.570 29.560 ;
        RECT 81.690 28.520 81.860 29.560 ;
        RECT 82.250 28.520 82.420 29.560 ;
        RECT 84.540 28.520 84.710 29.560 ;
        RECT 76.780 28.180 78.780 28.350 ;
        RECT 79.630 28.180 81.630 28.350 ;
        RECT 82.480 28.180 84.480 28.350 ;
        RECT 85.110 27.840 85.280 30.240 ;
        RECT 113.420 28.610 113.590 66.100 ;
        RECT 114.630 65.590 114.960 65.760 ;
        RECT 115.590 65.590 115.920 65.760 ;
        RECT 116.550 65.590 116.880 65.760 ;
        RECT 117.510 65.590 117.840 65.760 ;
        RECT 118.470 65.590 118.800 65.760 ;
        RECT 119.430 65.590 119.760 65.760 ;
        RECT 120.390 65.590 120.720 65.760 ;
        RECT 121.350 65.590 121.680 65.760 ;
        RECT 122.310 65.590 122.640 65.760 ;
        RECT 123.270 65.590 123.600 65.760 ;
        RECT 124.230 65.590 124.560 65.760 ;
        RECT 125.190 65.590 125.520 65.760 ;
        RECT 126.150 65.590 126.480 65.760 ;
        RECT 127.110 65.590 127.440 65.760 ;
        RECT 128.070 65.590 128.400 65.760 ;
        RECT 129.030 65.590 129.360 65.760 ;
        RECT 129.990 65.590 130.320 65.760 ;
        RECT 130.950 65.590 131.280 65.760 ;
        RECT 131.910 65.590 132.240 65.760 ;
        RECT 132.870 65.590 133.200 65.760 ;
        RECT 133.830 65.590 134.160 65.760 ;
        RECT 134.790 65.590 135.120 65.760 ;
        RECT 135.750 65.590 136.080 65.760 ;
        RECT 136.710 65.590 137.040 65.760 ;
        RECT 137.670 65.590 138.000 65.760 ;
        RECT 138.630 65.590 138.960 65.760 ;
        RECT 113.990 29.335 114.160 65.375 ;
        RECT 114.470 29.335 114.640 65.375 ;
        RECT 114.950 29.335 115.120 65.375 ;
        RECT 115.430 29.335 115.600 65.375 ;
        RECT 115.910 29.335 116.080 65.375 ;
        RECT 116.390 29.335 116.560 65.375 ;
        RECT 116.870 29.335 117.040 65.375 ;
        RECT 117.350 29.335 117.520 65.375 ;
        RECT 117.830 29.335 118.000 65.375 ;
        RECT 118.310 29.335 118.480 65.375 ;
        RECT 118.790 29.335 118.960 65.375 ;
        RECT 119.270 29.335 119.440 65.375 ;
        RECT 119.750 29.335 119.920 65.375 ;
        RECT 120.230 29.335 120.400 65.375 ;
        RECT 120.710 29.335 120.880 65.375 ;
        RECT 121.190 29.335 121.360 65.375 ;
        RECT 121.670 29.335 121.840 65.375 ;
        RECT 122.150 29.335 122.320 65.375 ;
        RECT 122.630 29.335 122.800 65.375 ;
        RECT 123.110 29.335 123.280 65.375 ;
        RECT 123.590 29.335 123.760 65.375 ;
        RECT 124.070 29.335 124.240 65.375 ;
        RECT 124.550 29.335 124.720 65.375 ;
        RECT 125.030 29.335 125.200 65.375 ;
        RECT 125.510 29.335 125.680 65.375 ;
        RECT 125.990 29.335 126.160 65.375 ;
        RECT 126.470 29.335 126.640 65.375 ;
        RECT 126.950 29.335 127.120 65.375 ;
        RECT 127.430 29.335 127.600 65.375 ;
        RECT 127.910 29.335 128.080 65.375 ;
        RECT 128.390 29.335 128.560 65.375 ;
        RECT 128.870 29.335 129.040 65.375 ;
        RECT 129.350 29.335 129.520 65.375 ;
        RECT 129.830 29.335 130.000 65.375 ;
        RECT 130.310 29.335 130.480 65.375 ;
        RECT 130.790 29.335 130.960 65.375 ;
        RECT 131.270 29.335 131.440 65.375 ;
        RECT 131.750 29.335 131.920 65.375 ;
        RECT 132.230 29.335 132.400 65.375 ;
        RECT 132.710 29.335 132.880 65.375 ;
        RECT 133.190 29.335 133.360 65.375 ;
        RECT 133.670 29.335 133.840 65.375 ;
        RECT 134.150 29.335 134.320 65.375 ;
        RECT 134.630 29.335 134.800 65.375 ;
        RECT 135.110 29.335 135.280 65.375 ;
        RECT 135.590 29.335 135.760 65.375 ;
        RECT 136.070 29.335 136.240 65.375 ;
        RECT 136.550 29.335 136.720 65.375 ;
        RECT 137.030 29.335 137.200 65.375 ;
        RECT 137.510 29.335 137.680 65.375 ;
        RECT 137.990 29.335 138.160 65.375 ;
        RECT 138.470 29.335 138.640 65.375 ;
        RECT 138.950 29.335 139.120 65.375 ;
        RECT 114.150 28.950 114.480 29.120 ;
        RECT 115.110 28.950 115.440 29.120 ;
        RECT 116.070 28.950 116.400 29.120 ;
        RECT 117.030 28.950 117.360 29.120 ;
        RECT 117.990 28.950 118.320 29.120 ;
        RECT 118.950 28.950 119.280 29.120 ;
        RECT 119.910 28.950 120.240 29.120 ;
        RECT 120.870 28.950 121.200 29.120 ;
        RECT 121.830 28.950 122.160 29.120 ;
        RECT 122.790 28.950 123.120 29.120 ;
        RECT 123.750 28.950 124.080 29.120 ;
        RECT 124.710 28.950 125.040 29.120 ;
        RECT 125.670 28.950 126.000 29.120 ;
        RECT 126.630 28.950 126.960 29.120 ;
        RECT 127.590 28.950 127.920 29.120 ;
        RECT 128.550 28.950 128.880 29.120 ;
        RECT 129.510 28.950 129.840 29.120 ;
        RECT 130.470 28.950 130.800 29.120 ;
        RECT 131.430 28.950 131.760 29.120 ;
        RECT 132.390 28.950 132.720 29.120 ;
        RECT 133.350 28.950 133.680 29.120 ;
        RECT 134.310 28.950 134.640 29.120 ;
        RECT 135.270 28.950 135.600 29.120 ;
        RECT 136.230 28.950 136.560 29.120 ;
        RECT 137.190 28.950 137.520 29.120 ;
        RECT 138.150 28.950 138.480 29.120 ;
        RECT 139.520 28.610 139.690 66.100 ;
        RECT 142.760 64.875 149.070 65.045 ;
        RECT 142.760 55.870 142.930 64.875 ;
        RECT 143.645 63.840 143.995 64.070 ;
        RECT 144.795 63.840 145.145 64.070 ;
        RECT 145.425 63.840 145.775 64.070 ;
        RECT 146.055 63.840 146.405 64.070 ;
        RECT 146.685 63.840 147.035 64.070 ;
        RECT 147.835 63.840 148.185 64.070 ;
        RECT 143.420 57.030 143.590 63.630 ;
        RECT 144.050 57.030 144.220 63.630 ;
        RECT 144.570 57.030 144.740 63.630 ;
        RECT 145.200 57.030 145.370 63.630 ;
        RECT 145.830 57.030 146.000 63.630 ;
        RECT 146.460 57.030 146.630 63.630 ;
        RECT 147.090 57.030 147.260 63.630 ;
        RECT 147.610 57.030 147.780 63.630 ;
        RECT 148.240 57.030 148.410 63.630 ;
        RECT 143.645 56.590 143.995 56.820 ;
        RECT 144.795 56.590 145.145 56.820 ;
        RECT 145.425 56.590 145.775 56.820 ;
        RECT 146.055 56.590 146.405 56.820 ;
        RECT 146.685 56.590 147.035 56.820 ;
        RECT 147.835 56.590 148.185 56.820 ;
        RECT 148.900 55.870 149.070 64.875 ;
        RECT 151.565 64.875 167.065 65.045 ;
        RECT 151.565 57.070 151.735 64.875 ;
        RECT 152.620 63.685 153.620 63.915 ;
        RECT 154.420 63.685 155.420 63.915 ;
        RECT 155.700 63.685 156.700 63.915 ;
        RECT 156.980 63.685 157.980 63.915 ;
        RECT 158.260 63.685 159.260 63.915 ;
        RECT 159.540 63.685 160.540 63.915 ;
        RECT 160.820 63.685 161.820 63.915 ;
        RECT 162.100 63.685 163.100 63.915 ;
        RECT 163.380 63.685 164.380 63.915 ;
        RECT 165.180 63.685 166.180 63.915 ;
        RECT 152.395 58.475 152.565 63.475 ;
        RECT 153.675 58.475 153.845 63.475 ;
        RECT 154.195 58.475 154.365 63.475 ;
        RECT 155.475 58.475 155.645 63.475 ;
        RECT 156.755 58.475 156.925 63.475 ;
        RECT 158.035 58.475 158.205 63.475 ;
        RECT 159.315 58.475 159.485 63.475 ;
        RECT 160.595 58.475 160.765 63.475 ;
        RECT 161.875 58.475 162.045 63.475 ;
        RECT 163.155 58.475 163.325 63.475 ;
        RECT 164.435 58.475 164.605 63.475 ;
        RECT 164.955 58.475 165.125 63.475 ;
        RECT 166.235 58.475 166.405 63.475 ;
        RECT 152.620 58.035 153.620 58.265 ;
        RECT 154.420 58.035 155.420 58.265 ;
        RECT 155.700 58.035 156.700 58.265 ;
        RECT 156.980 58.035 157.980 58.265 ;
        RECT 158.260 58.035 159.260 58.265 ;
        RECT 159.540 58.035 160.540 58.265 ;
        RECT 160.820 58.035 161.820 58.265 ;
        RECT 162.100 58.035 163.100 58.265 ;
        RECT 163.380 58.035 164.380 58.265 ;
        RECT 165.180 58.035 166.180 58.265 ;
        RECT 166.895 57.070 167.065 64.875 ;
        RECT 151.565 56.900 167.065 57.070 ;
        RECT 142.760 55.700 149.070 55.870 ;
        RECT 152.560 55.150 157.890 55.320 ;
        RECT 142.760 54.490 146.770 54.660 ;
        RECT 142.760 52.430 142.930 54.490 ;
        RECT 143.630 53.920 143.980 54.150 ;
        RECT 145.520 53.920 145.870 54.150 ;
        RECT 146.600 53.960 146.770 54.490 ;
        RECT 146.960 54.440 151.380 54.610 ;
        RECT 146.960 53.960 147.130 54.440 ;
        RECT 143.405 53.210 143.575 53.710 ;
        RECT 144.035 53.210 144.205 53.710 ;
        RECT 144.665 53.210 144.835 53.710 ;
        RECT 145.295 53.210 145.465 53.710 ;
        RECT 145.925 53.210 146.095 53.710 ;
        RECT 143.630 52.770 143.980 53.000 ;
        RECT 145.520 52.770 145.870 53.000 ;
        RECT 146.600 52.630 147.130 53.960 ;
        RECT 147.865 53.870 148.215 54.100 ;
        RECT 150.165 53.870 150.515 54.100 ;
        RECT 147.640 53.240 147.810 53.660 ;
        RECT 148.270 53.240 148.440 53.660 ;
        RECT 148.790 53.240 148.960 53.660 ;
        RECT 149.420 53.240 149.590 53.660 ;
        RECT 149.940 53.240 150.110 53.660 ;
        RECT 150.570 53.240 150.740 53.660 ;
        RECT 147.865 52.800 148.215 53.030 ;
        RECT 150.165 52.800 150.515 53.030 ;
        RECT 146.600 52.430 146.770 52.630 ;
        RECT 142.760 52.260 146.770 52.430 ;
        RECT 146.960 52.460 147.130 52.630 ;
        RECT 151.210 52.460 151.380 54.440 ;
        RECT 146.960 52.290 151.380 52.460 ;
        RECT 152.560 52.090 152.730 55.150 ;
        RECT 153.445 54.580 153.865 54.810 ;
        RECT 156.585 54.580 157.005 54.810 ;
        RECT 153.220 52.870 153.390 54.370 ;
        RECT 153.920 52.870 154.090 54.370 ;
        RECT 154.440 52.870 154.610 54.370 ;
        RECT 155.140 52.870 155.310 54.370 ;
        RECT 155.840 52.870 156.010 54.370 ;
        RECT 156.360 52.870 156.530 54.370 ;
        RECT 157.060 52.870 157.230 54.370 ;
        RECT 153.445 52.430 153.865 52.660 ;
        RECT 156.585 52.430 157.005 52.660 ;
        RECT 157.720 52.090 157.890 55.150 ;
        RECT 152.560 51.920 157.890 52.090 ;
        RECT 160.850 55.265 167.520 55.435 ;
        RECT 142.760 50.360 144.880 50.530 ;
        RECT 142.760 48.250 142.930 50.360 ;
        RECT 143.645 49.790 143.995 50.020 ;
        RECT 143.420 49.030 143.590 49.580 ;
        RECT 144.050 49.030 144.220 49.580 ;
        RECT 143.645 48.590 143.995 48.820 ;
        RECT 144.710 48.250 144.880 50.360 ;
        RECT 142.760 48.080 144.880 48.250 ;
        RECT 145.070 50.360 147.190 50.530 ;
        RECT 145.070 48.250 145.240 50.360 ;
        RECT 145.955 49.790 146.305 50.020 ;
        RECT 145.730 49.030 145.900 49.580 ;
        RECT 146.360 49.030 146.530 49.580 ;
        RECT 145.955 48.590 146.305 48.820 ;
        RECT 147.020 48.250 147.190 50.360 ;
        RECT 160.850 50.445 161.020 55.265 ;
        RECT 161.645 54.325 161.975 54.555 ;
        RECT 162.595 54.325 162.925 54.555 ;
        RECT 163.545 54.325 163.875 54.555 ;
        RECT 164.495 54.325 164.825 54.555 ;
        RECT 165.445 54.325 165.775 54.555 ;
        RECT 166.395 54.325 166.725 54.555 ;
        RECT 161.510 51.615 161.680 54.115 ;
        RECT 161.940 51.615 162.110 54.115 ;
        RECT 162.460 51.615 162.630 54.115 ;
        RECT 162.890 51.615 163.060 54.115 ;
        RECT 163.410 51.615 163.580 54.115 ;
        RECT 163.840 51.615 164.010 54.115 ;
        RECT 164.360 51.615 164.530 54.115 ;
        RECT 164.790 51.615 164.960 54.115 ;
        RECT 165.310 51.615 165.480 54.115 ;
        RECT 165.740 51.615 165.910 54.115 ;
        RECT 166.260 51.615 166.430 54.115 ;
        RECT 166.690 51.615 166.860 54.115 ;
        RECT 161.645 51.175 161.975 51.405 ;
        RECT 162.595 51.175 162.925 51.405 ;
        RECT 163.545 51.175 163.875 51.405 ;
        RECT 164.495 51.175 164.825 51.405 ;
        RECT 165.445 51.175 165.775 51.405 ;
        RECT 166.395 51.175 166.725 51.405 ;
        RECT 167.350 50.445 167.520 55.265 ;
        RECT 160.850 50.275 167.520 50.445 ;
        RECT 145.070 48.080 147.190 48.250 ;
        RECT 148.095 49.865 154.405 50.035 ;
        RECT 142.925 47.265 144.845 47.435 ;
        RECT 142.925 40.705 143.095 47.265 ;
        RECT 144.675 46.995 144.845 47.265 ;
        RECT 145.015 47.265 146.935 47.435 ;
        RECT 145.015 46.995 145.185 47.265 ;
        RECT 143.720 46.695 144.050 46.925 ;
        RECT 143.585 41.485 143.755 46.485 ;
        RECT 144.015 41.485 144.185 46.485 ;
        RECT 144.675 44.105 145.185 46.995 ;
        RECT 145.810 46.695 146.140 46.925 ;
        RECT 144.675 43.545 144.845 44.105 ;
        RECT 145.015 43.545 145.185 44.105 ;
        RECT 143.720 41.045 144.050 41.275 ;
        RECT 144.675 41.025 145.185 43.545 ;
        RECT 145.675 41.485 145.845 46.485 ;
        RECT 146.105 41.485 146.275 46.485 ;
        RECT 145.810 41.045 146.140 41.275 ;
        RECT 144.675 40.705 144.845 41.025 ;
        RECT 142.925 40.535 144.845 40.705 ;
        RECT 145.015 40.705 145.185 41.025 ;
        RECT 146.765 40.705 146.935 47.265 ;
        RECT 148.095 46.515 148.265 49.865 ;
        RECT 148.980 48.900 149.330 49.130 ;
        RECT 150.130 48.900 150.480 49.130 ;
        RECT 150.760 48.900 151.110 49.130 ;
        RECT 151.390 48.900 151.740 49.130 ;
        RECT 152.020 48.900 152.370 49.130 ;
        RECT 153.170 48.900 153.520 49.130 ;
        RECT 148.755 47.690 148.925 48.690 ;
        RECT 149.385 47.690 149.555 48.690 ;
        RECT 149.905 47.690 150.075 48.690 ;
        RECT 150.535 47.690 150.705 48.690 ;
        RECT 151.165 47.690 151.335 48.690 ;
        RECT 151.795 47.690 151.965 48.690 ;
        RECT 152.425 47.690 152.595 48.690 ;
        RECT 152.945 47.690 153.115 48.690 ;
        RECT 153.575 47.690 153.745 48.690 ;
        RECT 148.980 47.250 149.330 47.480 ;
        RECT 150.130 47.250 150.480 47.480 ;
        RECT 150.760 47.250 151.110 47.480 ;
        RECT 151.390 47.250 151.740 47.480 ;
        RECT 152.020 47.250 152.370 47.480 ;
        RECT 153.170 47.250 153.520 47.480 ;
        RECT 154.235 46.515 154.405 49.865 ;
        RECT 148.095 46.345 154.405 46.515 ;
        RECT 159.070 49.300 169.540 49.470 ;
        RECT 148.845 43.155 156.495 43.325 ;
        RECT 148.845 41.095 149.015 43.155 ;
        RECT 149.580 42.585 150.580 42.815 ;
        RECT 154.460 42.585 155.460 42.815 ;
        RECT 149.355 41.875 149.525 42.375 ;
        RECT 150.635 41.875 150.805 42.375 ;
        RECT 151.155 41.875 151.325 42.375 ;
        RECT 152.435 41.875 152.605 42.375 ;
        RECT 153.715 41.875 153.885 42.375 ;
        RECT 154.235 41.875 154.405 42.375 ;
        RECT 155.515 41.875 155.685 42.375 ;
        RECT 149.580 41.435 150.580 41.665 ;
        RECT 154.460 41.435 155.460 41.665 ;
        RECT 156.325 41.095 156.495 43.155 ;
        RECT 148.845 40.925 156.495 41.095 ;
        RECT 145.015 40.535 146.935 40.705 ;
        RECT 159.070 33.050 159.240 49.300 ;
        RECT 159.865 48.730 160.195 48.960 ;
        RECT 160.815 48.730 161.145 48.960 ;
        RECT 161.765 48.730 162.095 48.960 ;
        RECT 162.715 48.730 163.045 48.960 ;
        RECT 163.665 48.730 163.995 48.960 ;
        RECT 164.615 48.730 164.945 48.960 ;
        RECT 165.565 48.730 165.895 48.960 ;
        RECT 166.515 48.730 166.845 48.960 ;
        RECT 167.465 48.730 167.795 48.960 ;
        RECT 168.415 48.730 168.745 48.960 ;
        RECT 159.730 46.020 159.900 48.520 ;
        RECT 160.160 46.020 160.330 48.520 ;
        RECT 160.680 46.020 160.850 48.520 ;
        RECT 161.110 46.020 161.280 48.520 ;
        RECT 161.630 46.020 161.800 48.520 ;
        RECT 162.060 46.020 162.230 48.520 ;
        RECT 162.580 46.020 162.750 48.520 ;
        RECT 163.010 46.020 163.180 48.520 ;
        RECT 163.530 46.020 163.700 48.520 ;
        RECT 163.960 46.020 164.130 48.520 ;
        RECT 164.480 46.020 164.650 48.520 ;
        RECT 164.910 46.020 165.080 48.520 ;
        RECT 165.430 46.020 165.600 48.520 ;
        RECT 165.860 46.020 166.030 48.520 ;
        RECT 166.380 46.020 166.550 48.520 ;
        RECT 166.810 46.020 166.980 48.520 ;
        RECT 167.330 46.020 167.500 48.520 ;
        RECT 167.760 46.020 167.930 48.520 ;
        RECT 168.280 46.020 168.450 48.520 ;
        RECT 168.710 46.020 168.880 48.520 ;
        RECT 159.865 44.770 160.195 45.000 ;
        RECT 160.815 44.770 161.145 45.000 ;
        RECT 161.765 44.770 162.095 45.000 ;
        RECT 162.715 44.770 163.045 45.000 ;
        RECT 163.665 44.770 163.995 45.000 ;
        RECT 164.615 44.770 164.945 45.000 ;
        RECT 165.565 44.770 165.895 45.000 ;
        RECT 166.515 44.770 166.845 45.000 ;
        RECT 167.465 44.770 167.795 45.000 ;
        RECT 168.415 44.770 168.745 45.000 ;
        RECT 159.730 42.060 159.900 44.560 ;
        RECT 160.160 42.060 160.330 44.560 ;
        RECT 160.680 42.060 160.850 44.560 ;
        RECT 161.110 42.060 161.280 44.560 ;
        RECT 161.630 42.060 161.800 44.560 ;
        RECT 162.060 42.060 162.230 44.560 ;
        RECT 162.580 42.060 162.750 44.560 ;
        RECT 163.010 42.060 163.180 44.560 ;
        RECT 163.530 42.060 163.700 44.560 ;
        RECT 163.960 42.060 164.130 44.560 ;
        RECT 164.480 42.060 164.650 44.560 ;
        RECT 164.910 42.060 165.080 44.560 ;
        RECT 165.430 42.060 165.600 44.560 ;
        RECT 165.860 42.060 166.030 44.560 ;
        RECT 166.380 42.060 166.550 44.560 ;
        RECT 166.810 42.060 166.980 44.560 ;
        RECT 167.330 42.060 167.500 44.560 ;
        RECT 167.760 42.060 167.930 44.560 ;
        RECT 168.280 42.060 168.450 44.560 ;
        RECT 168.710 42.060 168.880 44.560 ;
        RECT 159.865 41.620 160.195 41.850 ;
        RECT 160.815 41.620 161.145 41.850 ;
        RECT 161.765 41.620 162.095 41.850 ;
        RECT 162.715 41.620 163.045 41.850 ;
        RECT 163.665 41.620 163.995 41.850 ;
        RECT 164.615 41.620 164.945 41.850 ;
        RECT 165.565 41.620 165.895 41.850 ;
        RECT 166.515 41.620 166.845 41.850 ;
        RECT 167.465 41.620 167.795 41.850 ;
        RECT 168.415 41.620 168.745 41.850 ;
        RECT 159.865 40.500 160.195 40.730 ;
        RECT 160.815 40.500 161.145 40.730 ;
        RECT 161.765 40.500 162.095 40.730 ;
        RECT 162.715 40.500 163.045 40.730 ;
        RECT 163.665 40.500 163.995 40.730 ;
        RECT 164.615 40.500 164.945 40.730 ;
        RECT 165.565 40.500 165.895 40.730 ;
        RECT 166.515 40.500 166.845 40.730 ;
        RECT 167.465 40.500 167.795 40.730 ;
        RECT 168.415 40.500 168.745 40.730 ;
        RECT 159.730 37.790 159.900 40.290 ;
        RECT 160.160 37.790 160.330 40.290 ;
        RECT 160.680 37.790 160.850 40.290 ;
        RECT 161.110 37.790 161.280 40.290 ;
        RECT 161.630 37.790 161.800 40.290 ;
        RECT 162.060 37.790 162.230 40.290 ;
        RECT 162.580 37.790 162.750 40.290 ;
        RECT 163.010 37.790 163.180 40.290 ;
        RECT 163.530 37.790 163.700 40.290 ;
        RECT 163.960 37.790 164.130 40.290 ;
        RECT 164.480 37.790 164.650 40.290 ;
        RECT 164.910 37.790 165.080 40.290 ;
        RECT 165.430 37.790 165.600 40.290 ;
        RECT 165.860 37.790 166.030 40.290 ;
        RECT 166.380 37.790 166.550 40.290 ;
        RECT 166.810 37.790 166.980 40.290 ;
        RECT 167.330 37.790 167.500 40.290 ;
        RECT 167.760 37.790 167.930 40.290 ;
        RECT 168.280 37.790 168.450 40.290 ;
        RECT 168.710 37.790 168.880 40.290 ;
        RECT 159.865 37.350 160.195 37.580 ;
        RECT 160.815 37.350 161.145 37.580 ;
        RECT 161.765 37.350 162.095 37.580 ;
        RECT 162.715 37.350 163.045 37.580 ;
        RECT 163.665 37.350 163.995 37.580 ;
        RECT 164.615 37.350 164.945 37.580 ;
        RECT 165.565 37.350 165.895 37.580 ;
        RECT 166.515 37.350 166.845 37.580 ;
        RECT 167.465 37.350 167.795 37.580 ;
        RECT 168.415 37.350 168.745 37.580 ;
        RECT 159.730 33.830 159.900 36.330 ;
        RECT 160.160 33.830 160.330 36.330 ;
        RECT 160.680 33.830 160.850 36.330 ;
        RECT 161.110 33.830 161.280 36.330 ;
        RECT 161.630 33.830 161.800 36.330 ;
        RECT 162.060 33.830 162.230 36.330 ;
        RECT 162.580 33.830 162.750 36.330 ;
        RECT 163.010 33.830 163.180 36.330 ;
        RECT 163.530 33.830 163.700 36.330 ;
        RECT 163.960 33.830 164.130 36.330 ;
        RECT 164.480 33.830 164.650 36.330 ;
        RECT 164.910 33.830 165.080 36.330 ;
        RECT 165.430 33.830 165.600 36.330 ;
        RECT 165.860 33.830 166.030 36.330 ;
        RECT 166.380 33.830 166.550 36.330 ;
        RECT 166.810 33.830 166.980 36.330 ;
        RECT 167.330 33.830 167.500 36.330 ;
        RECT 167.760 33.830 167.930 36.330 ;
        RECT 168.280 33.830 168.450 36.330 ;
        RECT 168.710 33.830 168.880 36.330 ;
        RECT 159.865 33.390 160.195 33.620 ;
        RECT 160.815 33.390 161.145 33.620 ;
        RECT 161.765 33.390 162.095 33.620 ;
        RECT 162.715 33.390 163.045 33.620 ;
        RECT 163.665 33.390 163.995 33.620 ;
        RECT 164.615 33.390 164.945 33.620 ;
        RECT 165.565 33.390 165.895 33.620 ;
        RECT 166.515 33.390 166.845 33.620 ;
        RECT 167.465 33.390 167.795 33.620 ;
        RECT 168.415 33.390 168.745 33.620 ;
        RECT 169.370 33.050 169.540 49.300 ;
        RECT 159.070 32.880 169.540 33.050 ;
        RECT 113.420 28.440 139.690 28.610 ;
        RECT 75.980 27.670 85.280 27.840 ;
        RECT 53.025 26.920 72.660 27.120 ;
        RECT 31.405 25.000 88.705 25.170 ;
        RECT 31.405 13.600 31.575 25.000 ;
        RECT 32.205 24.490 36.205 24.660 ;
        RECT 37.055 24.490 43.055 24.660 ;
        RECT 43.905 24.490 47.905 24.660 ;
        RECT 31.975 14.280 32.145 24.320 ;
        RECT 36.265 14.280 36.435 24.320 ;
        RECT 36.825 14.280 36.995 24.320 ;
        RECT 43.115 14.280 43.285 24.320 ;
        RECT 43.675 14.280 43.845 24.320 ;
        RECT 47.965 14.280 48.135 24.320 ;
        RECT 32.205 13.940 36.205 14.110 ;
        RECT 37.055 13.940 43.055 14.110 ;
        RECT 43.905 13.940 47.905 14.110 ;
        RECT 48.535 13.600 48.705 25.000 ;
        RECT 49.335 24.490 55.335 24.660 ;
        RECT 56.185 24.490 62.185 24.660 ;
        RECT 62.475 24.490 68.475 24.660 ;
        RECT 68.765 24.490 74.765 24.660 ;
        RECT 75.055 24.490 81.055 24.660 ;
        RECT 81.905 24.490 87.905 24.660 ;
        RECT 49.105 14.280 49.275 24.320 ;
        RECT 55.395 14.280 55.565 24.320 ;
        RECT 55.955 14.280 56.125 24.320 ;
        RECT 62.245 14.280 62.415 24.320 ;
        RECT 68.535 14.280 68.705 24.320 ;
        RECT 74.825 14.280 74.995 24.320 ;
        RECT 81.115 14.280 81.285 24.320 ;
        RECT 81.675 14.280 81.845 24.320 ;
        RECT 87.965 14.280 88.135 24.320 ;
        RECT 49.335 13.940 55.335 14.110 ;
        RECT 56.185 13.940 62.185 14.110 ;
        RECT 62.475 13.940 68.475 14.110 ;
        RECT 68.765 13.940 74.765 14.110 ;
        RECT 75.055 13.940 81.055 14.110 ;
        RECT 81.905 13.940 87.905 14.110 ;
        RECT 88.535 13.600 88.705 25.000 ;
        RECT 89.825 24.050 127.775 24.220 ;
        RECT 89.825 21.400 89.995 24.050 ;
        RECT 90.625 23.540 92.625 23.710 ;
        RECT 92.915 23.540 94.915 23.710 ;
        RECT 95.205 23.540 97.205 23.710 ;
        RECT 97.495 23.540 99.495 23.710 ;
        RECT 99.785 23.540 101.785 23.710 ;
        RECT 102.075 23.540 104.075 23.710 ;
        RECT 104.365 23.540 106.365 23.710 ;
        RECT 106.655 23.540 108.655 23.710 ;
        RECT 108.945 23.540 110.945 23.710 ;
        RECT 111.235 23.540 113.235 23.710 ;
        RECT 113.525 23.540 115.525 23.710 ;
        RECT 115.815 23.540 117.815 23.710 ;
        RECT 118.105 23.540 120.105 23.710 ;
        RECT 120.395 23.540 122.395 23.710 ;
        RECT 122.685 23.540 124.685 23.710 ;
        RECT 124.975 23.540 126.975 23.710 ;
        RECT 90.395 22.080 90.565 23.370 ;
        RECT 92.685 22.080 92.855 23.370 ;
        RECT 94.975 22.080 95.145 23.370 ;
        RECT 97.265 22.080 97.435 23.370 ;
        RECT 99.555 22.080 99.725 23.370 ;
        RECT 101.845 22.080 102.015 23.370 ;
        RECT 104.135 22.080 104.305 23.370 ;
        RECT 106.425 22.080 106.595 23.370 ;
        RECT 108.715 22.080 108.885 23.370 ;
        RECT 111.005 22.080 111.175 23.370 ;
        RECT 113.295 22.080 113.465 23.370 ;
        RECT 115.585 22.080 115.755 23.370 ;
        RECT 117.875 22.080 118.045 23.370 ;
        RECT 120.165 22.080 120.335 23.370 ;
        RECT 122.455 22.080 122.625 23.370 ;
        RECT 124.745 22.080 124.915 23.370 ;
        RECT 127.035 22.080 127.205 23.370 ;
        RECT 90.625 21.740 92.625 21.910 ;
        RECT 92.915 21.740 94.915 21.910 ;
        RECT 95.205 21.740 97.205 21.910 ;
        RECT 97.495 21.740 99.495 21.910 ;
        RECT 99.785 21.740 101.785 21.910 ;
        RECT 102.075 21.740 104.075 21.910 ;
        RECT 104.365 21.740 106.365 21.910 ;
        RECT 106.655 21.740 108.655 21.910 ;
        RECT 108.945 21.740 110.945 21.910 ;
        RECT 111.235 21.740 113.235 21.910 ;
        RECT 113.525 21.740 115.525 21.910 ;
        RECT 115.815 21.740 117.815 21.910 ;
        RECT 118.105 21.740 120.105 21.910 ;
        RECT 120.395 21.740 122.395 21.910 ;
        RECT 122.685 21.740 124.685 21.910 ;
        RECT 124.975 21.740 126.975 21.910 ;
        RECT 127.605 21.400 127.775 24.050 ;
        RECT 89.825 21.230 127.775 21.400 ;
        RECT 31.405 13.430 88.705 13.600 ;
      LAYER met1 ;
        RECT 31.555 75.065 65.725 75.830 ;
        RECT 31.555 73.665 32.345 75.065 ;
        RECT 35.385 73.665 36.175 75.065 ;
        RECT 42.065 73.725 42.635 75.065 ;
        RECT 42.235 73.665 42.465 73.725 ;
        RECT 48.355 73.695 48.925 75.065 ;
        RECT 54.650 73.725 55.220 75.065 ;
        RECT 60.945 73.725 61.895 75.065 ;
        RECT 48.525 73.665 48.755 73.695 ;
        RECT 54.815 73.665 55.045 73.725 ;
        RECT 61.105 73.665 61.335 73.725 ;
        RECT 31.555 71.815 32.325 73.665 ;
        RECT 35.385 71.815 35.615 73.665 ;
        RECT 38.585 71.815 39.865 72.375 ;
        RECT 44.865 71.815 46.145 72.375 ;
        RECT 51.140 71.815 52.420 72.375 ;
        RECT 57.425 71.815 58.705 72.375 ;
        RECT 61.665 71.815 61.895 73.725 ;
        RECT 64.840 73.485 65.725 75.065 ;
        RECT 68.260 73.855 83.370 74.085 ;
        RECT 68.260 73.575 68.490 73.855 ;
        RECT 72.080 73.575 72.720 73.650 ;
        RECT 74.360 73.575 75.000 73.650 ;
        RECT 76.605 73.575 77.245 73.650 ;
        RECT 78.930 73.575 79.570 73.650 ;
        RECT 83.140 73.575 83.370 73.855 ;
        RECT 68.260 73.485 71.070 73.575 ;
        RECT 64.840 73.345 71.070 73.485 ;
        RECT 71.400 73.345 73.360 73.575 ;
        RECT 73.690 73.345 75.650 73.575 ;
        RECT 75.980 73.345 77.940 73.575 ;
        RECT 78.270 73.345 80.230 73.575 ;
        RECT 80.560 73.345 83.370 73.575 ;
        RECT 64.840 71.865 69.135 73.345 ;
        RECT 72.080 73.280 72.720 73.345 ;
        RECT 74.360 73.280 75.000 73.345 ;
        RECT 76.605 73.280 77.245 73.345 ;
        RECT 78.930 73.280 79.570 73.345 ;
        RECT 71.120 73.080 71.350 73.140 ;
        RECT 73.410 73.080 73.640 73.140 ;
        RECT 75.700 73.080 75.930 73.140 ;
        RECT 77.990 73.080 78.220 73.140 ;
        RECT 80.280 73.080 80.510 73.140 ;
        RECT 82.570 73.080 82.800 73.140 ;
        RECT 83.140 73.080 83.370 73.345 ;
        RECT 64.820 71.815 69.135 71.865 ;
        RECT 31.555 71.585 35.615 71.815 ;
        RECT 36.225 71.585 42.185 71.815 ;
        RECT 42.515 71.585 48.475 71.815 ;
        RECT 48.805 71.585 54.765 71.815 ;
        RECT 55.095 71.585 61.055 71.815 ;
        RECT 61.665 71.585 69.135 71.815 ;
        RECT 31.555 69.925 32.325 71.585 ;
        RECT 35.385 69.925 35.615 71.585 ;
        RECT 35.945 71.320 36.175 71.380 ;
        RECT 42.235 71.320 42.465 71.380 ;
        RECT 48.525 71.320 48.755 71.380 ;
        RECT 54.815 71.320 55.045 71.380 ;
        RECT 61.105 71.320 61.335 71.380 ;
        RECT 35.760 70.190 36.330 71.320 ;
        RECT 42.065 70.190 42.635 71.320 ;
        RECT 48.355 70.190 48.925 71.320 ;
        RECT 54.650 70.190 55.220 71.320 ;
        RECT 60.940 70.190 61.510 71.320 ;
        RECT 35.945 70.130 36.175 70.190 ;
        RECT 42.235 70.130 42.465 70.190 ;
        RECT 48.525 70.130 48.755 70.190 ;
        RECT 54.815 70.130 55.045 70.190 ;
        RECT 61.105 70.130 61.335 70.190 ;
        RECT 61.665 69.925 61.895 71.585 ;
        RECT 64.820 69.925 69.135 71.585 ;
        RECT 31.555 69.695 35.615 69.925 ;
        RECT 36.225 69.695 42.185 69.925 ;
        RECT 42.515 69.695 48.475 69.925 ;
        RECT 48.805 69.695 54.765 69.925 ;
        RECT 55.095 69.695 61.055 69.925 ;
        RECT 61.665 69.695 69.135 69.925 ;
        RECT 31.555 69.480 32.325 69.695 ;
        RECT 31.555 69.160 32.365 69.480 ;
        RECT 31.555 67.925 32.325 69.160 ;
        RECT 35.385 67.925 35.615 69.695 ;
        RECT 38.585 67.925 39.865 69.695 ;
        RECT 44.865 67.925 46.145 69.695 ;
        RECT 51.140 67.925 52.420 69.695 ;
        RECT 57.425 67.925 58.705 69.695 ;
        RECT 61.665 67.925 61.895 69.695 ;
        RECT 64.840 68.685 69.135 69.695 ;
        RECT 71.045 68.950 71.425 73.080 ;
        RECT 73.335 68.950 73.715 73.080 ;
        RECT 75.625 68.950 76.005 73.080 ;
        RECT 77.915 68.950 78.295 73.080 ;
        RECT 80.205 68.950 80.585 73.080 ;
        RECT 82.495 68.950 83.370 73.080 ;
        RECT 92.115 73.740 103.805 74.010 ;
        RECT 92.115 69.880 92.345 73.740 ;
        RECT 93.030 73.255 103.020 73.485 ;
        RECT 92.750 72.990 92.980 73.050 ;
        RECT 94.040 72.990 94.270 73.050 ;
        RECT 95.330 72.990 95.560 73.050 ;
        RECT 92.675 70.610 93.055 72.990 ;
        RECT 93.965 70.610 94.345 72.990 ;
        RECT 95.255 70.610 95.635 72.990 ;
        RECT 92.750 70.550 92.980 70.610 ;
        RECT 94.040 70.550 94.270 70.610 ;
        RECT 95.330 70.550 95.560 70.610 ;
        RECT 96.545 70.345 96.925 73.255 ;
        RECT 97.910 73.040 98.140 73.050 ;
        RECT 97.835 70.560 98.215 73.040 ;
        RECT 97.910 70.550 98.140 70.560 ;
        RECT 99.125 70.345 99.505 73.255 ;
        RECT 100.490 72.990 100.720 73.050 ;
        RECT 101.780 72.990 102.010 73.050 ;
        RECT 103.070 72.990 103.300 73.050 ;
        RECT 100.415 70.610 100.795 72.990 ;
        RECT 101.705 70.610 102.085 72.990 ;
        RECT 102.995 70.610 103.375 72.990 ;
        RECT 100.490 70.550 100.720 70.610 ;
        RECT 101.780 70.550 102.010 70.610 ;
        RECT 103.070 70.550 103.300 70.610 ;
        RECT 93.030 70.115 103.020 70.345 ;
        RECT 103.575 69.880 103.805 73.740 ;
        RECT 104.720 72.370 105.020 72.645 ;
        RECT 104.720 72.175 104.950 72.370 ;
        RECT 104.695 72.135 105.070 72.175 ;
        RECT 104.695 71.905 105.880 72.135 ;
        RECT 106.770 71.905 107.080 73.190 ;
        RECT 107.410 71.905 107.720 73.190 ;
        RECT 108.050 71.905 108.360 73.190 ;
        RECT 108.690 71.905 109.000 73.190 ;
        RECT 112.060 72.645 113.275 72.665 ;
        RECT 110.730 72.370 111.050 72.645 ;
        RECT 112.050 72.415 113.275 72.645 ;
        RECT 112.060 72.380 113.275 72.415 ;
        RECT 110.820 72.185 111.050 72.370 ;
        RECT 110.805 72.135 111.180 72.185 ;
        RECT 109.890 71.905 111.180 72.135 ;
        RECT 104.695 71.640 105.070 71.905 ;
        RECT 105.290 71.640 105.520 71.700 ;
        RECT 105.930 71.640 106.160 71.700 ;
        RECT 106.490 71.640 106.720 71.700 ;
        RECT 107.130 71.640 107.360 71.700 ;
        RECT 107.770 71.640 108.000 71.700 ;
        RECT 108.410 71.640 108.640 71.700 ;
        RECT 109.050 71.640 109.280 71.700 ;
        RECT 109.610 71.640 109.840 71.700 ;
        RECT 110.250 71.640 110.480 71.700 ;
        RECT 110.805 71.640 111.180 71.905 ;
        RECT 104.695 70.880 105.585 71.640 ;
        RECT 105.865 70.880 106.225 71.640 ;
        RECT 106.415 70.880 106.795 71.640 ;
        RECT 107.055 70.880 107.435 71.640 ;
        RECT 107.695 70.880 108.075 71.640 ;
        RECT 108.335 70.880 108.715 71.640 ;
        RECT 108.975 70.880 109.355 71.640 ;
        RECT 109.545 70.880 109.905 71.640 ;
        RECT 110.185 70.880 111.180 71.640 ;
        RECT 104.695 70.615 105.070 70.880 ;
        RECT 105.290 70.820 105.520 70.880 ;
        RECT 105.930 70.820 106.160 70.880 ;
        RECT 106.490 70.820 106.720 70.880 ;
        RECT 107.130 70.820 107.360 70.880 ;
        RECT 107.770 70.820 108.000 70.880 ;
        RECT 108.410 70.820 108.640 70.880 ;
        RECT 109.050 70.820 109.280 70.880 ;
        RECT 109.610 70.820 109.840 70.880 ;
        RECT 110.250 70.820 110.480 70.880 ;
        RECT 110.805 70.615 111.180 70.880 ;
        RECT 104.695 70.385 105.880 70.615 ;
        RECT 104.695 70.185 105.070 70.385 ;
        RECT 92.115 69.610 103.805 69.880 ;
        RECT 104.720 70.165 105.070 70.185 ;
        RECT 104.720 69.875 105.180 70.165 ;
        RECT 92.480 69.605 103.805 69.610 ;
        RECT 106.770 69.345 107.080 70.615 ;
        RECT 107.410 69.345 107.720 70.615 ;
        RECT 108.050 69.340 108.360 70.615 ;
        RECT 108.690 69.345 109.000 70.615 ;
        RECT 109.890 70.385 111.180 70.615 ;
        RECT 110.805 70.195 111.180 70.385 ;
        RECT 112.000 72.135 112.230 72.195 ;
        RECT 112.000 71.905 113.160 72.135 ;
        RECT 113.490 71.905 113.800 73.235 ;
        RECT 114.130 71.905 114.440 73.235 ;
        RECT 114.770 71.905 115.080 73.235 ;
        RECT 115.410 71.905 115.720 73.235 ;
        RECT 115.915 72.415 117.100 72.645 ;
        RECT 116.980 72.135 117.210 72.195 ;
        RECT 116.050 71.905 117.210 72.135 ;
        RECT 112.000 71.700 112.230 71.905 ;
        RECT 116.980 71.700 117.210 71.905 ;
        RECT 112.000 71.640 112.800 71.700 ;
        RECT 113.210 71.640 113.440 71.700 ;
        RECT 113.850 71.640 114.080 71.700 ;
        RECT 114.490 71.640 114.720 71.700 ;
        RECT 115.130 71.640 115.360 71.700 ;
        RECT 115.770 71.640 116.000 71.700 ;
        RECT 116.410 71.640 117.210 71.700 ;
        RECT 112.000 70.880 112.875 71.640 ;
        RECT 113.135 70.880 113.515 71.640 ;
        RECT 113.785 70.880 114.145 71.640 ;
        RECT 114.415 70.880 114.795 71.640 ;
        RECT 115.065 70.880 115.425 71.640 ;
        RECT 115.695 70.880 116.075 71.640 ;
        RECT 116.345 70.880 117.210 71.640 ;
        RECT 112.000 70.820 112.800 70.880 ;
        RECT 113.210 70.820 113.440 70.880 ;
        RECT 113.850 70.820 114.080 70.880 ;
        RECT 114.490 70.820 114.720 70.880 ;
        RECT 115.130 70.820 115.360 70.880 ;
        RECT 115.770 70.820 116.000 70.880 ;
        RECT 116.410 70.820 117.210 70.880 ;
        RECT 112.000 70.615 112.230 70.820 ;
        RECT 116.980 70.615 117.210 70.820 ;
        RECT 112.000 70.385 113.160 70.615 ;
        RECT 112.000 70.325 112.230 70.385 ;
        RECT 110.805 70.165 111.050 70.195 ;
        RECT 110.720 69.875 111.050 70.165 ;
        RECT 112.005 69.875 113.190 70.105 ;
        RECT 113.490 69.300 113.800 70.615 ;
        RECT 114.130 69.300 114.440 70.615 ;
        RECT 114.770 69.300 115.080 70.615 ;
        RECT 115.410 69.300 115.720 70.615 ;
        RECT 116.050 70.385 117.210 70.615 ;
        RECT 116.980 70.325 117.210 70.385 ;
        RECT 115.930 69.875 117.115 70.105 ;
        RECT 71.120 68.890 71.350 68.950 ;
        RECT 73.410 68.890 73.640 68.950 ;
        RECT 75.700 68.890 75.930 68.950 ;
        RECT 77.990 68.890 78.220 68.950 ;
        RECT 80.280 68.890 80.510 68.950 ;
        RECT 82.570 68.890 82.800 68.950 ;
        RECT 72.080 68.685 72.720 68.730 ;
        RECT 74.360 68.685 75.000 68.730 ;
        RECT 76.610 68.685 77.250 68.730 ;
        RECT 78.925 68.685 79.565 68.730 ;
        RECT 83.140 68.685 83.370 68.950 ;
        RECT 64.840 68.455 71.070 68.685 ;
        RECT 71.400 68.455 73.360 68.685 ;
        RECT 73.690 68.455 75.650 68.685 ;
        RECT 75.980 68.455 77.940 68.685 ;
        RECT 78.270 68.455 80.230 68.685 ;
        RECT 80.560 68.455 83.370 68.685 ;
        RECT 64.840 67.925 65.725 68.455 ;
        RECT 68.260 68.175 68.490 68.455 ;
        RECT 72.080 68.360 72.720 68.455 ;
        RECT 74.360 68.360 75.000 68.455 ;
        RECT 76.610 68.360 77.250 68.455 ;
        RECT 78.925 68.360 79.565 68.455 ;
        RECT 83.140 68.175 83.370 68.455 ;
        RECT 68.260 67.945 83.370 68.175 ;
        RECT 31.555 67.695 35.615 67.925 ;
        RECT 36.225 67.695 42.185 67.925 ;
        RECT 42.515 67.695 48.475 67.925 ;
        RECT 48.805 67.695 54.765 67.925 ;
        RECT 55.095 67.695 61.055 67.925 ;
        RECT 61.665 67.695 65.725 67.925 ;
        RECT 31.555 67.430 32.325 67.695 ;
        RECT 31.555 66.300 32.460 67.430 ;
        RECT 31.555 66.035 32.325 66.300 ;
        RECT 35.385 66.035 35.615 67.695 ;
        RECT 35.945 67.430 36.175 67.490 ;
        RECT 42.235 67.430 42.465 67.490 ;
        RECT 48.525 67.430 48.755 67.490 ;
        RECT 54.815 67.430 55.045 67.490 ;
        RECT 61.105 67.430 61.335 67.490 ;
        RECT 35.760 66.300 36.330 67.430 ;
        RECT 42.065 66.300 42.635 67.430 ;
        RECT 48.355 66.300 48.925 67.430 ;
        RECT 54.650 66.300 55.220 67.430 ;
        RECT 60.950 66.300 61.520 67.430 ;
        RECT 35.945 66.240 36.175 66.300 ;
        RECT 42.235 66.240 42.465 66.300 ;
        RECT 48.525 66.240 48.755 66.300 ;
        RECT 54.815 66.240 55.045 66.300 ;
        RECT 61.105 66.240 61.335 66.300 ;
        RECT 61.665 66.035 61.895 67.695 ;
        RECT 64.840 67.430 65.725 67.695 ;
        RECT 64.825 66.300 65.725 67.430 ;
        RECT 105.800 67.265 111.515 67.495 ;
        RECT 105.400 66.985 105.630 67.225 ;
        RECT 111.660 66.985 111.890 67.225 ;
        RECT 105.400 66.755 106.560 66.985 ;
        RECT 106.890 66.755 110.400 66.985 ;
        RECT 110.730 66.755 111.890 66.985 ;
        RECT 105.400 66.535 105.630 66.755 ;
        RECT 105.970 66.535 106.200 66.595 ;
        RECT 106.610 66.535 106.840 66.595 ;
        RECT 107.250 66.535 107.480 66.595 ;
        RECT 107.890 66.535 108.120 66.595 ;
        RECT 64.840 66.035 65.725 66.300 ;
        RECT 31.555 65.805 35.615 66.035 ;
        RECT 36.225 65.805 42.185 66.035 ;
        RECT 42.515 65.805 48.475 66.035 ;
        RECT 48.805 65.805 54.765 66.035 ;
        RECT 55.095 65.805 61.055 66.035 ;
        RECT 61.665 65.950 65.725 66.035 ;
        RECT 68.255 66.230 89.065 66.460 ;
        RECT 68.255 65.950 68.485 66.230 ;
        RECT 72.615 65.950 73.255 66.005 ;
        RECT 74.900 65.950 75.540 66.020 ;
        RECT 77.185 65.950 77.825 66.020 ;
        RECT 79.460 65.950 80.100 66.020 ;
        RECT 81.755 65.950 82.395 66.020 ;
        RECT 84.060 65.950 84.700 66.020 ;
        RECT 88.835 65.950 89.065 66.230 ;
        RECT 61.665 65.805 71.065 65.950 ;
        RECT 31.555 64.035 32.325 65.805 ;
        RECT 35.385 64.035 35.615 65.805 ;
        RECT 38.585 64.035 39.865 65.805 ;
        RECT 44.865 64.035 46.145 65.805 ;
        RECT 51.140 64.035 52.420 65.805 ;
        RECT 57.425 64.035 58.705 65.805 ;
        RECT 61.665 64.035 61.895 65.805 ;
        RECT 64.840 65.720 71.065 65.805 ;
        RECT 71.955 65.720 73.915 65.950 ;
        RECT 74.245 65.720 76.205 65.950 ;
        RECT 76.535 65.720 78.495 65.950 ;
        RECT 78.825 65.720 80.785 65.950 ;
        RECT 81.115 65.720 83.075 65.950 ;
        RECT 83.405 65.720 85.365 65.950 ;
        RECT 86.255 65.720 89.065 65.950 ;
        RECT 64.840 64.035 69.130 65.720 ;
        RECT 72.615 65.635 73.255 65.720 ;
        RECT 74.900 65.650 75.540 65.720 ;
        RECT 77.185 65.650 77.825 65.720 ;
        RECT 79.460 65.650 80.100 65.720 ;
        RECT 81.755 65.650 82.395 65.720 ;
        RECT 84.060 65.650 84.700 65.720 ;
        RECT 71.115 65.455 71.345 65.515 ;
        RECT 71.675 65.455 71.905 65.515 ;
        RECT 73.965 65.455 74.195 65.515 ;
        RECT 76.255 65.455 76.485 65.515 ;
        RECT 78.545 65.455 78.775 65.515 ;
        RECT 80.835 65.455 81.065 65.515 ;
        RECT 83.125 65.455 83.355 65.515 ;
        RECT 85.415 65.455 85.645 65.515 ;
        RECT 85.975 65.455 86.205 65.515 ;
        RECT 88.265 65.455 88.495 65.515 ;
        RECT 88.835 65.455 89.065 65.720 ;
        RECT 31.555 63.805 35.615 64.035 ;
        RECT 36.225 63.805 42.185 64.035 ;
        RECT 42.515 63.805 48.475 64.035 ;
        RECT 48.805 63.805 54.765 64.035 ;
        RECT 55.095 63.805 61.055 64.035 ;
        RECT 61.665 63.805 69.130 64.035 ;
        RECT 31.555 63.540 32.325 63.805 ;
        RECT 31.555 62.410 32.460 63.540 ;
        RECT 31.555 62.145 32.325 62.410 ;
        RECT 35.385 62.145 35.615 63.805 ;
        RECT 35.945 63.540 36.175 63.600 ;
        RECT 42.235 63.540 42.465 63.600 ;
        RECT 48.525 63.540 48.755 63.600 ;
        RECT 54.815 63.540 55.045 63.600 ;
        RECT 61.105 63.540 61.335 63.600 ;
        RECT 35.760 62.410 36.330 63.540 ;
        RECT 42.065 62.410 42.635 63.540 ;
        RECT 48.355 62.410 48.925 63.540 ;
        RECT 54.650 62.410 55.220 63.540 ;
        RECT 60.945 62.410 61.515 63.540 ;
        RECT 35.945 62.350 36.175 62.410 ;
        RECT 42.235 62.350 42.465 62.410 ;
        RECT 48.525 62.350 48.755 62.410 ;
        RECT 54.815 62.350 55.045 62.410 ;
        RECT 61.105 62.350 61.335 62.410 ;
        RECT 61.665 62.145 61.895 63.805 ;
        RECT 64.840 62.145 69.130 63.805 ;
        RECT 31.555 61.915 35.615 62.145 ;
        RECT 36.225 61.915 42.185 62.145 ;
        RECT 42.515 61.915 48.475 62.145 ;
        RECT 48.805 61.915 54.765 62.145 ;
        RECT 55.095 61.915 61.055 62.145 ;
        RECT 61.665 61.915 69.130 62.145 ;
        RECT 31.555 61.210 32.325 61.915 ;
        RECT 31.555 60.890 32.400 61.210 ;
        RECT 31.555 60.005 32.325 60.890 ;
        RECT 31.555 58.875 32.440 60.005 ;
        RECT 31.555 58.815 32.325 58.875 ;
        RECT 35.385 58.815 35.615 61.915 ;
        RECT 38.585 61.355 39.865 61.915 ;
        RECT 44.865 61.355 46.145 61.915 ;
        RECT 51.140 61.355 52.420 61.915 ;
        RECT 57.420 61.520 58.705 61.915 ;
        RECT 57.425 61.355 58.705 61.520 ;
        RECT 35.945 59.920 36.175 60.065 ;
        RECT 42.235 60.005 42.465 60.065 ;
        RECT 48.525 60.005 48.755 60.065 ;
        RECT 54.815 60.005 55.045 60.065 ;
        RECT 61.105 60.005 61.335 60.065 ;
        RECT 35.760 58.875 36.330 59.920 ;
        RECT 42.065 58.875 42.635 60.005 ;
        RECT 48.355 58.875 48.925 60.005 ;
        RECT 54.650 58.875 55.220 60.005 ;
        RECT 60.940 58.875 61.510 60.005 ;
        RECT 35.945 58.815 36.175 58.875 ;
        RECT 42.235 58.815 42.465 58.875 ;
        RECT 48.525 58.815 48.755 58.875 ;
        RECT 54.815 58.815 55.045 58.875 ;
        RECT 61.105 58.815 61.335 58.875 ;
        RECT 31.555 58.610 32.260 58.815 ;
        RECT 61.665 58.610 61.895 61.915 ;
        RECT 64.840 61.060 69.130 61.915 ;
        RECT 70.920 61.325 71.345 65.455 ;
        RECT 71.600 61.325 71.980 65.455 ;
        RECT 73.890 61.325 74.270 65.455 ;
        RECT 76.180 61.325 76.560 65.455 ;
        RECT 78.470 61.325 78.850 65.455 ;
        RECT 80.760 61.325 81.140 65.455 ;
        RECT 83.050 61.325 83.430 65.455 ;
        RECT 85.340 61.325 85.720 65.455 ;
        RECT 85.975 61.325 86.400 65.455 ;
        RECT 88.190 61.325 89.065 65.455 ;
        RECT 93.510 64.640 93.740 65.230 ;
        RECT 97.660 64.640 98.300 66.250 ;
        RECT 98.950 64.640 99.590 66.360 ;
        RECT 103.510 64.640 103.740 64.880 ;
        RECT 93.510 64.410 95.320 64.640 ;
        RECT 97.500 64.410 98.460 64.640 ;
        RECT 98.790 64.410 99.750 64.640 ;
        RECT 101.930 64.410 103.740 64.640 ;
        RECT 93.510 64.190 93.740 64.410 ;
        RECT 94.080 64.190 94.310 64.250 ;
        RECT 95.370 64.190 95.600 64.250 ;
        RECT 95.930 64.190 96.160 64.250 ;
        RECT 97.220 64.190 97.450 64.250 ;
        RECT 98.510 64.190 98.740 64.250 ;
        RECT 93.510 63.060 94.385 64.190 ;
        RECT 95.160 63.060 95.600 64.190 ;
        RECT 95.855 63.060 96.235 64.190 ;
        RECT 97.145 63.060 97.525 64.190 ;
        RECT 98.435 63.060 98.815 64.190 ;
        RECT 99.800 64.185 100.030 64.250 ;
        RECT 101.090 64.190 101.320 64.250 ;
        RECT 101.650 64.190 101.880 64.250 ;
        RECT 102.940 64.190 103.170 64.250 ;
        RECT 103.510 64.190 103.740 64.410 ;
        RECT 93.510 62.840 93.740 63.060 ;
        RECT 94.080 63.000 94.310 63.060 ;
        RECT 95.370 63.000 95.600 63.060 ;
        RECT 95.930 63.000 96.160 63.060 ;
        RECT 97.220 63.000 97.450 63.060 ;
        RECT 98.510 63.000 98.740 63.060 ;
        RECT 99.725 63.055 100.105 64.185 ;
        RECT 101.015 63.060 101.395 64.190 ;
        RECT 101.650 63.060 102.085 64.190 ;
        RECT 102.865 63.060 103.740 64.190 ;
        RECT 99.800 63.000 100.030 63.055 ;
        RECT 101.090 63.000 101.320 63.060 ;
        RECT 101.650 63.000 101.880 63.060 ;
        RECT 102.940 63.000 103.170 63.060 ;
        RECT 103.510 62.840 103.740 63.060 ;
        RECT 93.510 62.610 95.320 62.840 ;
        RECT 97.500 62.610 98.460 62.840 ;
        RECT 98.790 62.610 99.750 62.840 ;
        RECT 101.930 62.610 103.740 62.840 ;
        RECT 93.510 62.015 93.740 62.610 ;
        RECT 71.115 61.265 71.345 61.325 ;
        RECT 71.675 61.265 71.905 61.325 ;
        RECT 73.965 61.265 74.195 61.325 ;
        RECT 76.255 61.265 76.485 61.325 ;
        RECT 78.545 61.265 78.775 61.325 ;
        RECT 80.835 61.265 81.065 61.325 ;
        RECT 83.125 61.265 83.355 61.325 ;
        RECT 85.415 61.265 85.645 61.325 ;
        RECT 85.975 61.265 86.205 61.325 ;
        RECT 88.265 61.265 88.495 61.325 ;
        RECT 72.605 61.060 73.245 61.100 ;
        RECT 74.900 61.060 75.540 61.100 ;
        RECT 77.180 61.060 77.820 61.100 ;
        RECT 79.455 61.060 80.095 61.100 ;
        RECT 81.755 61.060 82.395 61.100 ;
        RECT 84.065 61.060 84.705 61.100 ;
        RECT 88.835 61.060 89.065 61.325 ;
        RECT 64.840 60.880 71.065 61.060 ;
        RECT 64.840 60.005 65.725 60.880 ;
        RECT 68.255 60.830 71.065 60.880 ;
        RECT 71.955 60.830 73.915 61.060 ;
        RECT 74.245 60.830 76.205 61.060 ;
        RECT 76.535 60.830 78.495 61.060 ;
        RECT 78.825 60.830 80.785 61.060 ;
        RECT 81.115 60.830 83.075 61.060 ;
        RECT 83.405 60.830 85.365 61.060 ;
        RECT 86.255 60.830 89.065 61.060 ;
        RECT 97.660 60.995 98.300 62.610 ;
        RECT 98.950 60.995 99.590 62.610 ;
        RECT 103.510 62.370 103.740 62.610 ;
        RECT 105.400 63.155 106.265 66.535 ;
        RECT 106.545 63.155 106.905 66.535 ;
        RECT 107.175 63.155 107.555 66.535 ;
        RECT 107.825 63.155 108.185 66.535 ;
        RECT 105.400 62.935 105.630 63.155 ;
        RECT 105.970 63.095 106.200 63.155 ;
        RECT 106.610 63.095 106.840 63.155 ;
        RECT 107.250 63.095 107.480 63.155 ;
        RECT 107.890 63.095 108.120 63.155 ;
        RECT 108.455 62.935 108.835 66.755 ;
        RECT 109.170 66.535 109.400 66.595 ;
        RECT 109.810 66.570 110.040 66.595 ;
        RECT 109.105 63.155 109.465 66.535 ;
        RECT 109.735 63.190 110.115 66.570 ;
        RECT 110.450 66.535 110.680 66.595 ;
        RECT 111.090 66.535 111.320 66.595 ;
        RECT 111.660 66.535 111.890 66.755 ;
        RECT 109.170 63.095 109.400 63.155 ;
        RECT 109.810 63.095 110.040 63.190 ;
        RECT 110.385 63.155 110.745 66.535 ;
        RECT 111.025 63.155 111.890 66.535 ;
        RECT 110.450 63.095 110.680 63.155 ;
        RECT 111.090 63.095 111.320 63.155 ;
        RECT 111.660 62.935 111.890 63.155 ;
        RECT 105.400 62.705 106.560 62.935 ;
        RECT 106.890 62.705 110.400 62.935 ;
        RECT 110.730 62.705 111.890 62.935 ;
        RECT 105.400 62.425 105.630 62.705 ;
        RECT 111.660 62.425 111.890 62.705 ;
        RECT 105.400 62.195 111.890 62.425 ;
        RECT 113.390 65.355 113.620 66.380 ;
        RECT 114.650 65.560 114.940 66.895 ;
        RECT 115.610 65.560 115.900 66.895 ;
        RECT 116.570 65.560 116.860 66.895 ;
        RECT 117.530 65.560 117.820 66.895 ;
        RECT 118.490 65.560 118.780 66.895 ;
        RECT 119.450 65.560 119.740 66.895 ;
        RECT 120.410 65.560 120.700 66.895 ;
        RECT 121.370 65.560 121.660 66.895 ;
        RECT 122.330 65.560 122.620 66.895 ;
        RECT 123.290 65.560 123.580 66.895 ;
        RECT 124.250 65.560 124.540 66.895 ;
        RECT 125.210 65.560 125.500 66.895 ;
        RECT 126.170 65.560 126.460 66.895 ;
        RECT 127.130 65.560 127.420 66.895 ;
        RECT 128.090 65.560 128.380 66.895 ;
        RECT 129.050 65.560 129.340 66.895 ;
        RECT 130.010 65.560 130.300 66.895 ;
        RECT 130.970 65.560 131.260 66.895 ;
        RECT 131.930 65.560 132.220 66.895 ;
        RECT 132.890 65.560 133.180 66.895 ;
        RECT 133.850 65.560 134.140 66.895 ;
        RECT 134.810 65.560 135.100 66.895 ;
        RECT 135.770 65.560 136.060 66.895 ;
        RECT 136.730 65.560 137.020 66.895 ;
        RECT 137.690 65.560 137.980 66.895 ;
        RECT 139.490 65.790 139.720 65.850 ;
        RECT 138.650 65.560 139.720 65.790 ;
        RECT 139.490 65.355 139.720 65.560 ;
        RECT 113.390 65.295 114.670 65.355 ;
        RECT 68.255 60.550 68.485 60.830 ;
        RECT 72.605 60.730 73.245 60.830 ;
        RECT 74.900 60.730 75.540 60.830 ;
        RECT 77.180 60.730 77.820 60.830 ;
        RECT 79.455 60.730 80.095 60.830 ;
        RECT 81.755 60.730 82.395 60.830 ;
        RECT 84.065 60.730 84.705 60.830 ;
        RECT 88.835 60.550 89.065 60.830 ;
        RECT 68.255 60.320 89.065 60.550 ;
        RECT 64.835 58.875 65.725 60.005 ;
        RECT 64.840 58.610 65.725 58.875 ;
        RECT 31.555 57.900 65.725 58.610 ;
        RECT 113.390 58.870 114.750 65.295 ;
        RECT 31.375 55.550 31.605 55.790 ;
        RECT 34.900 55.550 36.180 56.110 ;
        RECT 37.110 55.550 38.390 56.110 ;
        RECT 39.995 55.550 41.275 56.110 ;
        RECT 41.585 55.830 42.535 56.060 ;
        RECT 31.375 55.320 34.185 55.550 ;
        RECT 34.515 55.320 36.475 55.550 ;
        RECT 36.805 55.320 38.765 55.550 ;
        RECT 39.655 55.320 41.615 55.550 ;
        RECT 31.375 55.115 31.605 55.320 ;
        RECT 41.755 55.115 42.335 55.830 ;
        RECT 42.875 55.550 44.155 56.110 ;
        RECT 45.145 55.550 46.425 56.110 ;
        RECT 47.925 55.550 49.205 56.110 ;
        RECT 49.575 55.830 50.525 56.060 ;
        RECT 42.505 55.320 44.465 55.550 ;
        RECT 44.795 55.320 46.755 55.550 ;
        RECT 47.645 55.320 49.605 55.550 ;
        RECT 49.780 55.115 50.355 55.830 ;
        RECT 50.855 55.550 52.135 56.110 ;
        RECT 53.130 55.550 54.410 56.110 ;
        RECT 58.095 55.605 58.325 55.725 ;
        RECT 57.060 55.550 58.325 55.605 ;
        RECT 50.495 55.320 52.455 55.550 ;
        RECT 52.785 55.320 54.745 55.550 ;
        RECT 55.075 55.485 58.325 55.550 ;
        RECT 60.400 55.485 61.040 56.555 ;
        RECT 61.680 55.485 62.320 56.555 ;
        RECT 62.980 55.485 63.620 56.555 ;
        RECT 64.265 55.485 64.905 56.555 ;
        RECT 65.535 55.485 66.175 56.555 ;
        RECT 66.840 55.485 67.480 56.555 ;
        RECT 68.135 56.540 68.775 56.555 ;
        RECT 69.425 56.540 70.065 56.555 ;
        RECT 68.115 56.210 68.775 56.540 ;
        RECT 69.400 56.210 70.065 56.540 ;
        RECT 68.135 55.485 68.775 56.210 ;
        RECT 69.425 55.485 70.065 56.210 ;
        RECT 76.975 56.245 90.125 56.475 ;
        RECT 90.345 56.245 107.015 56.475 ;
        RECT 76.975 55.765 77.205 56.245 ;
        RECT 83.435 55.765 83.665 56.245 ;
        RECT 89.895 55.765 90.125 56.245 ;
        RECT 90.355 56.180 107.015 56.245 ;
        RECT 100.505 55.765 100.735 56.180 ;
        RECT 103.645 55.765 103.875 56.180 ;
        RECT 106.785 55.765 107.015 56.180 ;
        RECT 72.135 55.485 72.365 55.725 ;
        RECT 55.075 55.320 59.905 55.485 ;
        RECT 57.060 55.255 59.905 55.320 ;
        RECT 60.235 55.255 61.195 55.485 ;
        RECT 61.525 55.255 62.485 55.485 ;
        RECT 62.815 55.255 63.775 55.485 ;
        RECT 64.105 55.255 65.065 55.485 ;
        RECT 65.395 55.255 66.355 55.485 ;
        RECT 66.685 55.255 67.645 55.485 ;
        RECT 67.975 55.255 68.935 55.485 ;
        RECT 69.265 55.255 70.225 55.485 ;
        RECT 70.555 55.255 72.365 55.485 ;
        RECT 31.375 53.615 32.250 55.115 ;
        RECT 34.235 55.055 34.465 55.115 ;
        RECT 36.525 55.055 36.755 55.115 ;
        RECT 38.815 55.055 39.045 55.115 ;
        RECT 39.375 55.055 39.605 55.115 ;
        RECT 41.665 55.055 42.455 55.115 ;
        RECT 44.515 55.055 44.745 55.115 ;
        RECT 46.805 55.055 47.035 55.115 ;
        RECT 47.365 55.055 47.595 55.115 ;
        RECT 49.655 55.055 50.445 55.115 ;
        RECT 52.505 55.055 52.735 55.115 ;
        RECT 54.795 55.055 55.025 55.115 ;
        RECT 57.060 55.055 58.970 55.255 ;
        RECT 34.160 53.675 34.540 55.055 ;
        RECT 36.450 53.675 36.830 55.055 ;
        RECT 38.620 53.675 39.125 55.055 ;
        RECT 39.300 53.675 39.680 55.055 ;
        RECT 41.645 53.675 42.475 55.055 ;
        RECT 44.440 53.675 44.820 55.055 ;
        RECT 46.735 53.675 47.115 55.055 ;
        RECT 47.290 53.675 47.670 55.055 ;
        RECT 49.635 53.675 50.465 55.055 ;
        RECT 52.430 53.675 52.810 55.055 ;
        RECT 54.720 53.675 55.100 55.055 ;
        RECT 57.010 53.675 58.970 55.055 ;
        RECT 59.955 54.990 60.185 55.050 ;
        RECT 61.245 54.990 61.475 55.050 ;
        RECT 62.535 54.990 62.765 55.050 ;
        RECT 63.825 54.990 64.055 55.050 ;
        RECT 65.115 54.990 65.345 55.050 ;
        RECT 66.405 54.990 66.635 55.050 ;
        RECT 67.695 54.990 67.925 55.050 ;
        RECT 68.985 54.990 69.215 55.050 ;
        RECT 70.275 54.990 70.505 55.050 ;
        RECT 59.880 53.860 60.260 54.990 ;
        RECT 61.170 53.860 61.550 54.990 ;
        RECT 62.460 53.860 62.840 54.990 ;
        RECT 63.750 53.860 64.130 54.990 ;
        RECT 65.040 53.860 65.420 54.990 ;
        RECT 66.330 53.860 66.710 54.990 ;
        RECT 67.620 53.860 68.000 54.990 ;
        RECT 68.910 53.860 69.290 54.990 ;
        RECT 70.200 53.860 70.580 54.990 ;
        RECT 59.955 53.800 60.185 53.860 ;
        RECT 61.245 53.800 61.475 53.860 ;
        RECT 62.535 53.800 62.765 53.860 ;
        RECT 63.825 53.800 64.055 53.860 ;
        RECT 65.115 53.800 65.345 53.860 ;
        RECT 66.405 53.800 66.635 53.860 ;
        RECT 67.695 53.800 67.925 53.860 ;
        RECT 68.985 53.800 69.215 53.860 ;
        RECT 70.275 53.800 70.505 53.860 ;
        RECT 34.235 53.615 34.465 53.675 ;
        RECT 36.525 53.615 36.755 53.675 ;
        RECT 38.815 53.615 39.045 53.675 ;
        RECT 39.375 53.615 39.605 53.675 ;
        RECT 41.665 53.615 42.455 53.675 ;
        RECT 44.515 53.615 44.745 53.675 ;
        RECT 46.805 53.615 47.035 53.675 ;
        RECT 47.365 53.615 47.595 53.675 ;
        RECT 49.655 53.615 50.445 53.675 ;
        RECT 52.505 53.615 52.735 53.675 ;
        RECT 54.795 53.615 55.025 53.675 ;
        RECT 31.375 53.410 31.605 53.615 ;
        RECT 31.375 53.180 34.185 53.410 ;
        RECT 34.515 53.180 36.475 53.410 ;
        RECT 36.805 53.180 38.765 53.410 ;
        RECT 39.655 53.180 41.615 53.410 ;
        RECT 31.375 53.010 31.605 53.180 ;
        RECT 34.900 52.620 36.180 53.180 ;
        RECT 37.110 52.620 38.390 53.180 ;
        RECT 39.995 52.620 41.275 53.180 ;
        RECT 41.760 52.900 42.335 53.615 ;
        RECT 42.505 53.180 44.465 53.410 ;
        RECT 44.795 53.180 46.755 53.410 ;
        RECT 47.645 53.180 49.605 53.410 ;
        RECT 41.585 52.670 42.535 52.900 ;
        RECT 42.875 52.620 44.155 53.180 ;
        RECT 45.145 52.620 46.425 53.180 ;
        RECT 47.925 52.620 49.205 53.180 ;
        RECT 49.780 52.900 50.355 53.615 ;
        RECT 57.060 53.595 58.970 53.675 ;
        RECT 71.490 53.595 72.365 55.255 ;
        RECT 57.060 53.410 59.905 53.595 ;
        RECT 50.495 53.180 52.455 53.410 ;
        RECT 52.785 53.180 54.745 53.410 ;
        RECT 55.075 53.365 59.905 53.410 ;
        RECT 60.235 53.365 61.195 53.595 ;
        RECT 61.525 53.365 62.485 53.595 ;
        RECT 62.815 53.365 63.775 53.595 ;
        RECT 64.105 53.365 65.065 53.595 ;
        RECT 65.395 53.365 66.355 53.595 ;
        RECT 66.685 53.365 67.645 53.595 ;
        RECT 67.975 53.365 68.935 53.595 ;
        RECT 69.265 53.365 70.225 53.595 ;
        RECT 70.555 53.365 72.365 53.595 ;
        RECT 55.075 53.180 58.325 53.365 ;
        RECT 49.575 52.670 50.525 52.900 ;
        RECT 50.855 52.620 52.135 53.180 ;
        RECT 53.130 52.620 54.410 53.180 ;
        RECT 57.655 53.165 57.885 53.180 ;
        RECT 58.095 53.125 58.325 53.180 ;
        RECT 60.400 52.295 61.040 53.365 ;
        RECT 61.680 52.295 62.320 53.365 ;
        RECT 62.980 52.295 63.620 53.365 ;
        RECT 64.265 52.295 64.905 53.365 ;
        RECT 65.535 52.295 66.175 53.365 ;
        RECT 66.840 52.295 67.480 53.365 ;
        RECT 68.135 52.295 68.775 53.365 ;
        RECT 69.425 52.295 70.065 53.365 ;
        RECT 72.135 53.125 72.365 53.365 ;
        RECT 76.975 53.660 77.955 55.765 ;
        RECT 78.535 55.705 78.785 55.765 ;
        RECT 78.470 53.720 78.850 55.705 ;
        RECT 78.535 53.660 78.785 53.720 ;
        RECT 79.365 53.660 80.445 55.765 ;
        RECT 81.025 53.660 82.105 55.765 ;
        RECT 82.685 53.660 85.245 55.765 ;
        RECT 85.825 53.660 86.905 55.765 ;
        RECT 87.485 53.660 88.565 55.765 ;
        RECT 89.145 53.660 90.875 55.765 ;
        RECT 91.455 55.700 91.705 55.765 ;
        RECT 91.390 53.715 91.770 55.700 ;
        RECT 91.455 53.660 91.705 53.715 ;
        RECT 92.285 53.660 93.365 55.765 ;
        RECT 93.945 53.660 95.025 55.765 ;
        RECT 95.605 53.660 96.685 55.765 ;
        RECT 97.265 53.660 98.345 55.765 ;
        RECT 98.925 55.705 99.175 55.765 ;
        RECT 98.860 53.720 99.240 55.705 ;
        RECT 98.925 53.660 99.175 53.720 ;
        RECT 99.755 53.660 101.485 55.765 ;
        RECT 102.065 55.745 102.315 55.765 ;
        RECT 101.980 53.680 102.400 55.745 ;
        RECT 102.065 53.660 102.315 53.680 ;
        RECT 102.895 53.660 104.625 55.765 ;
        RECT 105.205 55.755 105.455 55.765 ;
        RECT 105.125 53.690 105.545 55.755 ;
        RECT 105.205 53.660 105.455 53.690 ;
        RECT 106.035 53.660 107.015 55.765 ;
        RECT 76.975 50.740 77.205 53.660 ;
        RECT 31.375 50.350 47.545 50.740 ;
        RECT 31.375 50.030 47.575 50.350 ;
        RECT 53.025 50.250 72.660 50.740 ;
        RECT 53.025 50.095 72.690 50.250 ;
        RECT 31.375 47.370 32.255 50.030 ;
        RECT 34.205 47.370 34.435 50.030 ;
        RECT 34.765 49.770 34.995 49.870 ;
        RECT 37.055 49.770 37.285 49.870 ;
        RECT 39.345 49.770 39.575 49.870 ;
        RECT 41.635 49.770 41.865 49.870 ;
        RECT 43.925 49.770 44.155 49.870 ;
        RECT 34.645 47.495 35.115 49.770 ;
        RECT 36.935 47.495 37.405 49.770 ;
        RECT 39.225 47.495 39.695 49.770 ;
        RECT 41.515 47.495 41.985 49.770 ;
        RECT 43.810 47.495 44.280 49.770 ;
        RECT 34.765 47.370 34.995 47.495 ;
        RECT 37.055 47.370 37.285 47.495 ;
        RECT 39.345 47.370 39.575 47.495 ;
        RECT 41.635 47.370 41.865 47.495 ;
        RECT 43.925 47.370 44.155 47.495 ;
        RECT 44.485 47.370 44.715 50.030 ;
        RECT 46.645 47.480 47.115 50.030 ;
        RECT 46.775 47.370 47.005 47.480 ;
        RECT 31.375 46.560 31.605 47.370 ;
        RECT 47.345 46.570 47.575 50.030 ;
        RECT 31.375 46.240 31.780 46.560 ;
        RECT 47.155 46.250 47.575 46.570 ;
        RECT 31.375 45.520 31.605 46.240 ;
        RECT 35.705 45.520 36.345 46.080 ;
        RECT 38.010 45.520 38.650 46.080 ;
        RECT 40.300 45.520 40.940 46.090 ;
        RECT 42.585 45.520 43.225 46.080 ;
        RECT 47.345 45.520 47.575 46.250 ;
        RECT 31.375 45.395 34.430 45.520 ;
        RECT 31.375 45.290 34.435 45.395 ;
        RECT 35.045 45.290 37.005 45.520 ;
        RECT 37.335 45.290 39.295 45.520 ;
        RECT 39.625 45.290 41.585 45.520 ;
        RECT 41.915 45.290 43.875 45.520 ;
        RECT 44.485 45.290 47.575 45.520 ;
        RECT 31.375 42.470 32.260 45.290 ;
        RECT 34.205 42.470 34.435 45.290 ;
        RECT 34.765 45.025 34.995 45.130 ;
        RECT 37.055 45.025 37.285 45.130 ;
        RECT 39.345 45.025 39.575 45.130 ;
        RECT 41.635 45.025 41.865 45.130 ;
        RECT 43.925 45.025 44.155 45.130 ;
        RECT 34.645 42.750 35.115 45.025 ;
        RECT 36.935 42.750 37.405 45.025 ;
        RECT 39.225 42.750 39.695 45.025 ;
        RECT 41.515 42.750 41.985 45.025 ;
        RECT 43.810 42.750 44.280 45.025 ;
        RECT 34.765 42.630 34.995 42.750 ;
        RECT 37.055 42.630 37.285 42.750 ;
        RECT 39.345 42.630 39.575 42.750 ;
        RECT 41.635 42.630 41.865 42.750 ;
        RECT 43.925 42.630 44.155 42.750 ;
        RECT 44.485 42.470 44.715 45.290 ;
        RECT 46.775 45.005 47.575 45.290 ;
        RECT 46.640 42.730 47.575 45.005 ;
        RECT 46.775 42.470 47.575 42.730 ;
        RECT 31.375 42.240 34.435 42.470 ;
        RECT 35.045 42.240 37.005 42.470 ;
        RECT 37.335 42.240 39.295 42.470 ;
        RECT 39.625 42.240 41.585 42.470 ;
        RECT 41.915 42.240 43.875 42.470 ;
        RECT 44.485 42.240 47.575 42.470 ;
        RECT 31.375 40.475 31.605 42.240 ;
        RECT 31.375 40.245 34.435 40.475 ;
        RECT 35.705 40.470 36.345 42.240 ;
        RECT 38.010 40.470 38.650 42.240 ;
        RECT 40.300 40.470 40.940 42.240 ;
        RECT 42.585 40.470 43.225 42.240 ;
        RECT 47.345 40.470 47.575 42.240 ;
        RECT 31.375 37.425 32.250 40.245 ;
        RECT 34.205 37.425 34.435 40.245 ;
        RECT 35.045 40.240 37.005 40.470 ;
        RECT 37.335 40.240 39.295 40.470 ;
        RECT 39.625 40.240 41.585 40.470 ;
        RECT 41.915 40.240 43.875 40.470 ;
        RECT 44.485 40.240 47.575 40.470 ;
        RECT 34.765 39.965 34.995 40.080 ;
        RECT 37.055 39.970 37.285 40.080 ;
        RECT 39.345 39.970 39.575 40.080 ;
        RECT 41.635 39.970 41.865 40.080 ;
        RECT 43.925 39.970 44.155 40.080 ;
        RECT 34.645 37.690 35.115 39.965 ;
        RECT 36.935 37.695 37.405 39.970 ;
        RECT 39.225 37.695 39.695 39.970 ;
        RECT 41.515 37.695 41.985 39.970 ;
        RECT 43.810 37.695 44.280 39.970 ;
        RECT 34.765 37.580 34.995 37.690 ;
        RECT 37.055 37.580 37.285 37.695 ;
        RECT 39.345 37.580 39.575 37.695 ;
        RECT 41.635 37.580 41.865 37.695 ;
        RECT 43.925 37.580 44.155 37.695 ;
        RECT 31.375 37.195 34.435 37.425 ;
        RECT 44.485 37.420 44.715 40.240 ;
        RECT 46.775 39.970 47.575 40.240 ;
        RECT 46.645 37.695 47.575 39.970 ;
        RECT 46.775 37.420 47.575 37.695 ;
        RECT 31.375 35.420 31.605 37.195 ;
        RECT 35.045 37.190 37.005 37.420 ;
        RECT 37.335 37.190 39.295 37.420 ;
        RECT 39.625 37.190 41.585 37.420 ;
        RECT 41.915 37.190 43.875 37.420 ;
        RECT 44.485 37.190 47.575 37.420 ;
        RECT 35.705 35.420 36.345 37.190 ;
        RECT 38.010 35.420 38.650 37.190 ;
        RECT 40.300 35.420 40.940 37.190 ;
        RECT 42.585 35.420 43.225 37.190 ;
        RECT 47.345 35.420 47.575 37.190 ;
        RECT 31.375 35.190 34.435 35.420 ;
        RECT 35.045 35.190 37.005 35.420 ;
        RECT 37.335 35.190 39.295 35.420 ;
        RECT 39.625 35.190 41.585 35.420 ;
        RECT 41.915 35.190 43.875 35.420 ;
        RECT 44.485 35.190 47.575 35.420 ;
        RECT 31.375 32.370 32.250 35.190 ;
        RECT 34.205 32.370 34.435 35.190 ;
        RECT 34.765 34.900 34.995 35.030 ;
        RECT 37.055 34.900 37.285 35.030 ;
        RECT 39.345 34.900 39.575 35.030 ;
        RECT 41.635 34.900 41.865 35.030 ;
        RECT 43.925 34.900 44.155 35.030 ;
        RECT 34.645 32.625 35.115 34.900 ;
        RECT 36.935 32.625 37.405 34.900 ;
        RECT 39.225 32.625 39.695 34.900 ;
        RECT 41.515 32.625 41.985 34.900 ;
        RECT 43.810 32.625 44.280 34.900 ;
        RECT 34.765 32.530 34.995 32.625 ;
        RECT 37.055 32.530 37.285 32.625 ;
        RECT 39.345 32.530 39.575 32.625 ;
        RECT 41.635 32.530 41.865 32.625 ;
        RECT 43.925 32.530 44.155 32.625 ;
        RECT 44.485 32.370 44.715 35.190 ;
        RECT 46.775 34.925 47.575 35.190 ;
        RECT 46.650 32.650 47.575 34.925 ;
        RECT 46.775 32.370 47.575 32.650 ;
        RECT 31.375 32.140 34.435 32.370 ;
        RECT 35.045 32.140 37.005 32.370 ;
        RECT 37.335 32.140 39.295 32.370 ;
        RECT 39.625 32.140 41.585 32.370 ;
        RECT 41.915 32.140 43.875 32.370 ;
        RECT 44.485 32.140 47.575 32.370 ;
        RECT 31.375 31.405 31.605 32.140 ;
        RECT 35.705 31.580 36.345 32.140 ;
        RECT 38.010 31.580 38.650 32.140 ;
        RECT 40.300 31.580 40.940 32.140 ;
        RECT 42.585 31.580 43.225 32.140 ;
        RECT 47.345 31.415 47.575 32.140 ;
        RECT 31.370 31.085 31.690 31.405 ;
        RECT 47.150 31.095 47.575 31.415 ;
        RECT 31.375 30.240 31.605 31.085 ;
        RECT 31.915 30.240 32.145 30.290 ;
        RECT 31.375 27.630 32.255 30.240 ;
        RECT 34.205 27.630 34.435 30.290 ;
        RECT 34.765 30.185 34.995 30.290 ;
        RECT 37.055 30.185 37.285 30.290 ;
        RECT 39.345 30.185 39.575 30.290 ;
        RECT 41.635 30.185 41.865 30.290 ;
        RECT 43.925 30.185 44.155 30.290 ;
        RECT 34.645 27.910 35.115 30.185 ;
        RECT 36.935 27.910 37.405 30.185 ;
        RECT 39.225 27.910 39.695 30.185 ;
        RECT 41.515 27.910 41.985 30.185 ;
        RECT 43.810 27.910 44.280 30.185 ;
        RECT 34.765 27.790 34.995 27.910 ;
        RECT 37.055 27.790 37.285 27.910 ;
        RECT 39.345 27.790 39.575 27.910 ;
        RECT 41.635 27.790 41.865 27.910 ;
        RECT 43.925 27.790 44.155 27.910 ;
        RECT 44.485 27.630 44.715 30.290 ;
        RECT 46.775 30.210 47.005 30.290 ;
        RECT 46.655 27.935 47.125 30.210 ;
        RECT 46.775 27.790 47.005 27.935 ;
        RECT 47.345 27.630 47.575 31.095 ;
        RECT 31.375 27.565 47.575 27.630 ;
        RECT 52.995 50.030 72.690 50.095 ;
        RECT 52.995 47.465 53.920 50.030 ;
        RECT 55.740 47.470 56.210 50.030 ;
        RECT 58.030 47.470 58.500 50.030 ;
        RECT 60.320 47.470 60.790 50.030 ;
        RECT 62.610 47.470 63.080 50.030 ;
        RECT 64.900 47.470 65.370 50.030 ;
        RECT 67.190 47.470 67.660 50.030 ;
        RECT 69.480 47.470 69.950 50.030 ;
        RECT 71.770 47.470 72.690 50.030 ;
        RECT 76.880 49.870 77.305 50.740 ;
        RECT 52.995 46.570 53.225 47.465 ;
        RECT 53.570 47.370 53.800 47.465 ;
        RECT 55.860 47.370 56.090 47.470 ;
        RECT 58.150 47.370 58.380 47.470 ;
        RECT 60.440 47.370 60.670 47.470 ;
        RECT 62.730 47.370 62.960 47.470 ;
        RECT 65.020 47.370 65.250 47.470 ;
        RECT 67.310 47.370 67.540 47.470 ;
        RECT 69.600 47.370 69.830 47.470 ;
        RECT 71.890 47.370 72.120 47.470 ;
        RECT 72.460 46.570 72.690 47.470 ;
        RECT 76.975 46.595 77.205 49.870 ;
        RECT 52.995 46.250 53.430 46.570 ;
        RECT 72.250 46.250 72.690 46.570 ;
        RECT 52.995 45.520 53.225 46.250 ;
        RECT 56.805 45.520 57.445 46.085 ;
        RECT 59.090 45.520 59.730 46.085 ;
        RECT 61.380 45.520 62.020 46.085 ;
        RECT 63.655 45.520 64.295 46.085 ;
        RECT 65.955 45.520 66.595 46.085 ;
        RECT 68.240 45.520 68.880 46.085 ;
        RECT 72.460 45.520 72.690 46.250 ;
        RECT 76.880 46.225 77.305 46.595 ;
        RECT 52.995 45.290 55.805 45.520 ;
        RECT 56.135 45.290 58.095 45.520 ;
        RECT 58.425 45.290 60.385 45.520 ;
        RECT 60.715 45.290 62.675 45.520 ;
        RECT 63.005 45.290 64.965 45.520 ;
        RECT 65.295 45.290 67.255 45.520 ;
        RECT 67.585 45.290 69.545 45.520 ;
        RECT 69.875 45.290 72.690 45.520 ;
        RECT 52.995 42.470 53.915 45.290 ;
        RECT 55.745 42.630 56.215 45.130 ;
        RECT 58.025 42.630 58.495 45.130 ;
        RECT 60.320 42.630 60.790 45.130 ;
        RECT 62.600 42.630 63.070 45.130 ;
        RECT 64.900 42.630 65.370 45.130 ;
        RECT 67.185 42.630 67.655 45.130 ;
        RECT 69.480 42.630 69.950 45.130 ;
        RECT 71.765 42.470 72.690 45.290 ;
        RECT 52.995 42.240 55.805 42.470 ;
        RECT 56.135 42.240 58.095 42.470 ;
        RECT 58.425 42.240 60.385 42.470 ;
        RECT 60.715 42.240 62.675 42.470 ;
        RECT 63.005 42.240 64.965 42.470 ;
        RECT 65.295 42.240 67.255 42.470 ;
        RECT 67.585 42.240 69.545 42.470 ;
        RECT 69.875 42.240 72.690 42.470 ;
        RECT 52.995 40.470 53.225 42.240 ;
        RECT 56.805 40.470 57.445 42.240 ;
        RECT 59.090 40.470 59.730 42.240 ;
        RECT 61.380 40.470 62.020 42.240 ;
        RECT 63.655 40.470 64.295 42.240 ;
        RECT 65.955 40.470 66.595 42.240 ;
        RECT 68.240 40.470 68.880 42.240 ;
        RECT 72.460 40.470 72.690 42.240 ;
        RECT 76.975 45.015 77.205 46.225 ;
        RECT 83.435 45.020 83.665 53.660 ;
        RECT 89.895 50.450 90.125 53.660 ;
        RECT 100.505 51.580 100.735 53.660 ;
        RECT 103.645 51.580 103.875 53.660 ;
        RECT 106.785 51.580 107.015 53.660 ;
        RECT 100.505 50.450 101.485 51.580 ;
        RECT 89.895 48.345 90.875 50.450 ;
        RECT 91.455 48.345 92.535 50.450 ;
        RECT 93.115 48.345 94.195 50.450 ;
        RECT 94.775 48.345 95.855 50.450 ;
        RECT 96.435 48.345 97.515 50.450 ;
        RECT 98.095 48.345 99.175 50.450 ;
        RECT 99.755 49.475 101.485 50.450 ;
        RECT 99.755 48.995 100.735 49.475 ;
        RECT 102.065 48.995 102.315 51.580 ;
        RECT 102.895 49.475 104.625 51.580 ;
        RECT 105.205 51.520 105.455 51.580 ;
        RECT 103.645 48.995 103.875 49.475 ;
        RECT 105.120 49.455 105.540 51.520 ;
        RECT 106.035 49.475 107.015 51.580 ;
        RECT 106.785 49.040 107.015 49.475 ;
        RECT 105.305 48.995 107.015 49.040 ;
        RECT 99.755 48.765 107.015 48.995 ;
        RECT 99.755 48.345 100.735 48.765 ;
        RECT 105.305 48.730 106.915 48.765 ;
        RECT 89.895 47.865 90.125 48.345 ;
        RECT 90.350 47.865 100.330 47.890 ;
        RECT 100.505 47.865 100.735 48.345 ;
        RECT 89.895 47.635 100.735 47.865 ;
        RECT 89.895 45.020 90.125 47.635 ;
        RECT 90.350 47.600 100.330 47.635 ;
        RECT 77.705 45.015 77.955 45.020 ;
        RECT 76.975 42.915 77.955 45.015 ;
        RECT 78.535 42.915 79.615 45.020 ;
        RECT 80.195 42.915 81.275 45.020 ;
        RECT 81.855 44.960 82.105 45.020 ;
        RECT 81.790 42.975 82.170 44.960 ;
        RECT 81.855 42.915 82.105 42.975 ;
        RECT 82.685 42.915 84.415 45.020 ;
        RECT 84.995 42.915 86.075 45.020 ;
        RECT 86.655 42.915 87.735 45.020 ;
        RECT 88.315 44.960 88.565 45.020 ;
        RECT 88.250 42.975 88.630 44.960 ;
        RECT 88.315 42.915 88.565 42.975 ;
        RECT 89.145 42.915 90.125 45.020 ;
        RECT 76.975 42.910 77.770 42.915 ;
        RECT 76.975 42.465 77.205 42.910 ;
        RECT 83.435 42.465 83.665 42.915 ;
        RECT 89.895 42.465 90.125 42.915 ;
        RECT 76.975 42.205 90.125 42.465 ;
        RECT 77.025 42.185 90.060 42.205 ;
        RECT 52.995 40.240 55.805 40.470 ;
        RECT 56.135 40.240 58.095 40.470 ;
        RECT 58.425 40.240 60.385 40.470 ;
        RECT 60.715 40.240 62.675 40.470 ;
        RECT 63.005 40.240 64.965 40.470 ;
        RECT 65.295 40.240 67.255 40.470 ;
        RECT 67.585 40.240 69.545 40.470 ;
        RECT 69.875 40.240 72.690 40.470 ;
        RECT 52.995 37.420 53.910 40.240 ;
        RECT 55.750 37.580 56.220 40.080 ;
        RECT 58.025 37.580 58.495 40.080 ;
        RECT 60.305 37.740 60.790 40.080 ;
        RECT 62.595 37.740 63.080 40.080 ;
        RECT 64.885 37.740 65.370 40.080 ;
        RECT 67.170 37.740 67.655 40.080 ;
        RECT 60.435 37.580 60.665 37.740 ;
        RECT 62.725 37.580 62.955 37.740 ;
        RECT 65.015 37.580 65.245 37.740 ;
        RECT 67.305 37.580 67.535 37.740 ;
        RECT 69.480 37.580 69.950 40.080 ;
        RECT 71.765 37.420 72.690 40.240 ;
        RECT 76.045 38.980 78.610 39.210 ;
        RECT 76.045 38.700 76.275 38.980 ;
        RECT 78.920 38.700 79.560 39.260 ;
        RECT 80.190 38.700 80.830 39.260 ;
        RECT 81.150 38.980 83.695 39.210 ;
        RECT 81.170 38.930 83.695 38.980 ;
        RECT 83.465 38.700 83.695 38.930 ;
        RECT 76.045 38.470 77.855 38.700 ;
        RECT 78.745 38.470 79.705 38.700 ;
        RECT 80.035 38.470 80.995 38.700 ;
        RECT 81.885 38.470 83.695 38.700 ;
        RECT 76.045 38.310 76.275 38.470 ;
        RECT 83.465 38.310 83.695 38.470 ;
        RECT 76.045 38.230 76.845 38.310 ;
        RECT 77.905 38.235 78.135 38.310 ;
        RECT 78.465 38.250 78.695 38.310 ;
        RECT 79.755 38.250 79.985 38.310 ;
        RECT 81.045 38.250 81.275 38.310 ;
        RECT 81.605 38.255 81.835 38.310 ;
        RECT 75.985 38.220 76.845 38.230 ;
        RECT 75.985 37.910 76.890 38.220 ;
        RECT 77.870 37.915 78.190 38.235 ;
        RECT 52.995 37.190 55.805 37.420 ;
        RECT 56.135 37.190 58.095 37.420 ;
        RECT 58.425 37.190 60.385 37.420 ;
        RECT 60.715 37.190 62.675 37.420 ;
        RECT 63.005 37.190 64.965 37.420 ;
        RECT 65.295 37.190 67.255 37.420 ;
        RECT 67.585 37.190 69.545 37.420 ;
        RECT 69.875 37.190 72.690 37.420 ;
        RECT 52.995 35.420 53.225 37.190 ;
        RECT 56.805 35.420 57.445 37.190 ;
        RECT 59.090 35.420 59.730 37.190 ;
        RECT 61.380 35.420 62.020 37.190 ;
        RECT 63.655 35.420 64.295 37.190 ;
        RECT 65.955 35.420 66.595 37.190 ;
        RECT 68.240 35.420 68.880 37.190 ;
        RECT 72.460 35.420 72.690 37.190 ;
        RECT 76.045 37.900 76.890 37.910 ;
        RECT 76.045 37.810 76.845 37.900 ;
        RECT 77.905 37.810 78.135 37.915 ;
        RECT 78.390 37.870 78.770 38.250 ;
        RECT 79.680 37.870 80.060 38.250 ;
        RECT 80.970 37.870 81.350 38.250 ;
        RECT 81.575 37.935 81.895 38.255 ;
        RECT 78.465 37.810 78.695 37.870 ;
        RECT 79.755 37.810 79.985 37.870 ;
        RECT 81.045 37.810 81.275 37.870 ;
        RECT 81.605 37.810 81.835 37.935 ;
        RECT 82.895 37.810 83.695 38.310 ;
        RECT 76.045 37.650 76.275 37.810 ;
        RECT 83.465 37.650 83.695 37.810 ;
        RECT 76.045 37.420 77.855 37.650 ;
        RECT 78.745 37.420 79.705 37.650 ;
        RECT 80.035 37.420 80.995 37.650 ;
        RECT 81.885 37.420 83.695 37.650 ;
        RECT 76.045 37.140 76.275 37.420 ;
        RECT 76.045 36.910 78.620 37.140 ;
        RECT 78.920 36.860 79.560 37.420 ;
        RECT 80.190 36.860 80.830 37.420 ;
        RECT 83.465 37.180 83.695 37.420 ;
        RECT 81.030 37.140 83.695 37.180 ;
        RECT 80.975 36.910 83.695 37.140 ;
        RECT 52.995 35.190 55.805 35.420 ;
        RECT 56.135 35.190 58.095 35.420 ;
        RECT 58.425 35.190 60.385 35.420 ;
        RECT 60.715 35.190 62.675 35.420 ;
        RECT 63.005 35.190 64.965 35.420 ;
        RECT 65.295 35.190 67.255 35.420 ;
        RECT 67.585 35.190 69.545 35.420 ;
        RECT 69.875 35.190 72.690 35.420 ;
        RECT 52.995 34.975 53.795 35.190 ;
        RECT 55.855 34.975 56.085 35.030 ;
        RECT 52.995 32.635 53.915 34.975 ;
        RECT 55.740 32.635 56.225 34.975 ;
        RECT 58.145 34.970 58.375 35.030 ;
        RECT 60.435 34.970 60.665 35.030 ;
        RECT 62.725 34.970 62.955 35.030 ;
        RECT 65.015 34.970 65.245 35.030 ;
        RECT 67.305 34.970 67.535 35.030 ;
        RECT 69.595 34.970 69.825 35.030 ;
        RECT 52.995 32.370 53.795 32.635 ;
        RECT 55.855 32.530 56.085 32.635 ;
        RECT 58.020 32.630 58.505 34.970 ;
        RECT 60.315 32.630 60.800 34.970 ;
        RECT 62.600 32.630 63.085 34.970 ;
        RECT 64.890 32.630 65.375 34.970 ;
        RECT 67.175 32.630 67.660 34.970 ;
        RECT 69.470 32.630 69.955 34.970 ;
        RECT 58.145 32.530 58.375 32.630 ;
        RECT 60.435 32.530 60.665 32.630 ;
        RECT 62.725 32.530 62.955 32.630 ;
        RECT 65.015 32.530 65.245 32.630 ;
        RECT 67.305 32.530 67.535 32.630 ;
        RECT 69.595 32.530 69.825 32.630 ;
        RECT 71.765 32.370 72.690 35.190 ;
        RECT 52.995 32.140 55.805 32.370 ;
        RECT 56.135 32.140 58.095 32.370 ;
        RECT 58.425 32.140 60.385 32.370 ;
        RECT 60.715 32.140 62.675 32.370 ;
        RECT 63.005 32.140 64.965 32.370 ;
        RECT 65.295 32.140 67.255 32.370 ;
        RECT 67.585 32.140 69.545 32.370 ;
        RECT 69.875 32.140 72.690 32.370 ;
        RECT 52.995 31.415 53.225 32.140 ;
        RECT 56.805 31.580 57.445 32.140 ;
        RECT 59.090 31.580 59.730 32.140 ;
        RECT 61.380 31.580 62.020 32.140 ;
        RECT 63.655 31.580 64.295 32.140 ;
        RECT 65.955 31.580 66.595 32.140 ;
        RECT 68.240 31.580 68.880 32.140 ;
        RECT 52.995 31.095 53.430 31.415 ;
        RECT 52.995 30.205 53.225 31.095 ;
        RECT 53.565 30.205 53.795 30.290 ;
        RECT 55.855 30.205 56.085 30.290 ;
        RECT 58.145 30.205 58.375 30.290 ;
        RECT 60.435 30.205 60.665 30.290 ;
        RECT 62.725 30.205 62.955 30.290 ;
        RECT 65.015 30.205 65.245 30.290 ;
        RECT 67.305 30.205 67.535 30.290 ;
        RECT 69.595 30.205 69.825 30.290 ;
        RECT 71.885 30.205 72.115 30.290 ;
        RECT 72.460 30.205 72.690 32.140 ;
        RECT 75.950 34.520 77.845 34.750 ;
        RECT 75.950 34.240 76.180 34.520 ;
        RECT 78.250 34.240 78.890 35.310 ;
        RECT 79.550 34.240 80.190 35.310 ;
        RECT 80.820 34.240 81.460 35.310 ;
        RECT 82.110 34.240 82.750 35.310 ;
        RECT 82.925 34.520 85.060 34.750 ;
        RECT 84.830 34.240 85.060 34.520 ;
        RECT 75.950 34.010 77.760 34.240 ;
        RECT 78.090 34.010 79.050 34.240 ;
        RECT 79.380 34.010 80.340 34.240 ;
        RECT 80.670 34.010 81.630 34.240 ;
        RECT 81.960 34.010 82.920 34.240 ;
        RECT 83.250 34.010 85.060 34.240 ;
        RECT 75.950 33.790 76.180 34.010 ;
        RECT 76.520 33.790 76.750 33.850 ;
        RECT 77.810 33.790 78.040 33.850 ;
        RECT 79.100 33.790 79.330 33.850 ;
        RECT 80.390 33.790 80.620 33.850 ;
        RECT 81.680 33.790 81.910 33.850 ;
        RECT 82.970 33.790 83.200 33.850 ;
        RECT 84.260 33.790 84.490 33.850 ;
        RECT 84.830 33.790 85.060 34.010 ;
        RECT 75.950 32.660 76.825 33.790 ;
        RECT 77.735 32.660 78.115 33.790 ;
        RECT 79.025 32.660 79.405 33.790 ;
        RECT 80.315 32.660 80.695 33.790 ;
        RECT 81.605 32.660 81.985 33.790 ;
        RECT 82.895 32.660 83.275 33.790 ;
        RECT 84.185 32.660 85.060 33.790 ;
        RECT 75.950 32.440 76.180 32.660 ;
        RECT 76.520 32.600 76.750 32.660 ;
        RECT 77.810 32.600 78.040 32.660 ;
        RECT 79.100 32.600 79.330 32.660 ;
        RECT 80.390 32.600 80.620 32.660 ;
        RECT 81.680 32.600 81.910 32.660 ;
        RECT 82.970 32.600 83.200 32.660 ;
        RECT 84.260 32.600 84.490 32.660 ;
        RECT 84.830 32.440 85.060 32.660 ;
        RECT 75.950 32.210 77.760 32.440 ;
        RECT 78.090 32.210 79.050 32.440 ;
        RECT 79.380 32.210 80.340 32.440 ;
        RECT 80.670 32.210 81.630 32.440 ;
        RECT 81.960 32.210 82.920 32.440 ;
        RECT 83.250 32.210 85.060 32.440 ;
        RECT 75.950 31.930 76.180 32.210 ;
        RECT 75.950 31.700 77.845 31.930 ;
        RECT 78.250 31.140 78.890 32.210 ;
        RECT 79.550 31.140 80.190 32.210 ;
        RECT 80.820 31.140 81.460 32.210 ;
        RECT 82.110 31.140 82.750 32.210 ;
        RECT 84.830 31.930 85.060 32.210 ;
        RECT 82.915 31.700 85.060 31.930 ;
        RECT 52.995 27.650 53.960 30.205 ;
        RECT 55.735 27.650 56.205 30.205 ;
        RECT 58.025 27.650 58.495 30.205 ;
        RECT 60.320 27.650 60.790 30.205 ;
        RECT 62.605 27.650 63.075 30.205 ;
        RECT 64.900 27.650 65.370 30.205 ;
        RECT 67.185 27.650 67.655 30.205 ;
        RECT 69.480 27.650 69.950 30.205 ;
        RECT 71.640 27.650 72.690 30.205 ;
        RECT 31.375 26.920 47.545 27.565 ;
        RECT 52.995 27.360 72.690 27.650 ;
        RECT 75.950 30.180 85.310 30.440 ;
        RECT 75.950 29.930 76.180 30.180 ;
        RECT 85.080 29.930 85.310 30.180 ;
        RECT 75.950 29.700 78.760 29.930 ;
        RECT 79.370 29.700 81.610 29.930 ;
        RECT 82.500 29.700 85.310 29.930 ;
        RECT 75.950 29.480 76.180 29.700 ;
        RECT 76.520 29.480 76.750 29.540 ;
        RECT 78.810 29.480 79.040 29.540 ;
        RECT 79.370 29.480 79.600 29.700 ;
        RECT 81.660 29.480 81.890 29.540 ;
        RECT 82.220 29.480 82.450 29.540 ;
        RECT 84.510 29.480 84.740 29.540 ;
        RECT 85.080 29.480 85.310 29.700 ;
        RECT 75.950 28.600 76.750 29.480 ;
        RECT 78.615 28.600 79.040 29.480 ;
        RECT 79.295 28.600 79.675 29.480 ;
        RECT 81.640 28.600 82.470 29.480 ;
        RECT 84.490 28.600 85.310 29.480 ;
        RECT 75.950 28.380 76.180 28.600 ;
        RECT 76.520 28.540 76.750 28.600 ;
        RECT 78.810 28.540 79.040 28.600 ;
        RECT 79.370 28.380 79.600 28.600 ;
        RECT 81.660 28.540 81.890 28.600 ;
        RECT 82.220 28.540 82.450 28.600 ;
        RECT 84.510 28.540 84.740 28.600 ;
        RECT 85.080 28.380 85.310 28.600 ;
        RECT 75.950 28.150 78.760 28.380 ;
        RECT 79.370 28.150 81.610 28.380 ;
        RECT 82.500 28.150 85.310 28.380 ;
        RECT 113.390 29.355 114.670 58.870 ;
        RECT 114.920 58.730 115.150 65.355 ;
        RECT 115.400 65.295 115.630 65.355 ;
        RECT 115.335 58.870 115.700 65.295 ;
        RECT 114.845 52.145 115.225 58.730 ;
        RECT 114.920 29.355 115.150 52.145 ;
        RECT 115.400 50.470 115.630 58.870 ;
        RECT 115.880 58.730 116.110 65.355 ;
        RECT 116.360 65.295 116.590 65.355 ;
        RECT 116.295 58.870 116.655 65.295 ;
        RECT 115.805 52.145 116.185 58.730 ;
        RECT 115.325 40.590 115.705 50.470 ;
        RECT 115.400 35.840 115.630 40.590 ;
        RECT 115.335 29.415 115.695 35.840 ;
        RECT 115.400 29.355 115.630 29.415 ;
        RECT 115.880 29.355 116.110 52.145 ;
        RECT 116.360 50.470 116.590 58.870 ;
        RECT 116.840 58.730 117.070 65.355 ;
        RECT 117.320 65.295 117.550 65.355 ;
        RECT 117.255 58.870 117.615 65.295 ;
        RECT 116.765 52.145 117.145 58.730 ;
        RECT 116.285 40.590 116.665 50.470 ;
        RECT 116.360 35.840 116.590 40.590 ;
        RECT 116.295 29.415 116.655 35.840 ;
        RECT 116.360 29.355 116.590 29.415 ;
        RECT 116.840 29.355 117.070 52.145 ;
        RECT 117.320 50.470 117.550 58.870 ;
        RECT 117.800 58.730 118.030 65.355 ;
        RECT 118.280 65.295 118.510 65.355 ;
        RECT 118.215 58.870 118.575 65.295 ;
        RECT 117.730 52.145 118.110 58.730 ;
        RECT 117.245 40.590 117.625 50.470 ;
        RECT 117.320 35.840 117.550 40.590 ;
        RECT 117.255 29.415 117.615 35.840 ;
        RECT 117.320 29.355 117.550 29.415 ;
        RECT 117.800 29.355 118.030 52.145 ;
        RECT 118.280 50.470 118.510 58.870 ;
        RECT 118.760 58.730 118.990 65.355 ;
        RECT 119.240 65.295 119.470 65.355 ;
        RECT 119.175 58.870 119.535 65.295 ;
        RECT 118.685 52.145 119.065 58.730 ;
        RECT 118.205 40.590 118.585 50.470 ;
        RECT 118.280 35.840 118.510 40.590 ;
        RECT 118.215 29.415 118.575 35.840 ;
        RECT 118.280 29.355 118.510 29.415 ;
        RECT 118.760 29.355 118.990 52.145 ;
        RECT 119.240 50.470 119.470 58.870 ;
        RECT 119.720 58.730 119.950 65.355 ;
        RECT 120.200 65.295 120.430 65.355 ;
        RECT 120.135 58.870 120.495 65.295 ;
        RECT 119.650 52.145 120.030 58.730 ;
        RECT 119.165 40.590 119.545 50.470 ;
        RECT 119.240 35.840 119.470 40.590 ;
        RECT 119.175 29.415 119.535 35.840 ;
        RECT 119.240 29.355 119.470 29.415 ;
        RECT 119.720 29.355 119.950 52.145 ;
        RECT 120.200 50.470 120.430 58.870 ;
        RECT 120.680 58.730 120.910 65.355 ;
        RECT 121.160 65.295 121.390 65.355 ;
        RECT 121.095 58.870 121.455 65.295 ;
        RECT 120.605 52.145 120.985 58.730 ;
        RECT 120.125 40.590 120.505 50.470 ;
        RECT 120.200 35.840 120.430 40.590 ;
        RECT 120.135 29.415 120.495 35.840 ;
        RECT 120.200 29.355 120.430 29.415 ;
        RECT 120.680 29.355 120.910 52.145 ;
        RECT 121.160 50.470 121.390 58.870 ;
        RECT 121.640 58.730 121.870 65.355 ;
        RECT 122.120 65.295 122.350 65.355 ;
        RECT 122.055 58.870 122.415 65.295 ;
        RECT 121.570 52.145 121.950 58.730 ;
        RECT 121.085 40.590 121.465 50.470 ;
        RECT 121.160 35.840 121.390 40.590 ;
        RECT 121.095 29.415 121.455 35.840 ;
        RECT 121.160 29.355 121.390 29.415 ;
        RECT 121.640 29.355 121.870 52.145 ;
        RECT 122.120 50.470 122.350 58.870 ;
        RECT 122.600 58.730 122.830 65.355 ;
        RECT 123.080 65.295 123.310 65.355 ;
        RECT 123.015 58.870 123.375 65.295 ;
        RECT 122.525 52.145 122.905 58.730 ;
        RECT 122.045 40.590 122.425 50.470 ;
        RECT 122.120 35.840 122.350 40.590 ;
        RECT 122.055 29.415 122.415 35.840 ;
        RECT 122.120 29.355 122.350 29.415 ;
        RECT 122.600 29.355 122.830 52.145 ;
        RECT 123.080 50.470 123.310 58.870 ;
        RECT 123.560 58.730 123.790 65.355 ;
        RECT 124.040 65.295 124.270 65.355 ;
        RECT 123.975 58.870 124.335 65.295 ;
        RECT 123.490 52.145 123.870 58.730 ;
        RECT 123.005 40.590 123.385 50.470 ;
        RECT 123.080 35.840 123.310 40.590 ;
        RECT 123.015 29.415 123.375 35.840 ;
        RECT 123.080 29.355 123.310 29.415 ;
        RECT 123.560 29.355 123.790 52.145 ;
        RECT 124.040 50.470 124.270 58.870 ;
        RECT 124.520 58.730 124.750 65.355 ;
        RECT 125.000 65.295 125.230 65.355 ;
        RECT 124.935 58.870 125.295 65.295 ;
        RECT 124.445 52.145 124.825 58.730 ;
        RECT 123.965 40.590 124.345 50.470 ;
        RECT 124.040 35.840 124.270 40.590 ;
        RECT 123.975 29.415 124.335 35.840 ;
        RECT 124.040 29.355 124.270 29.415 ;
        RECT 124.520 29.355 124.750 52.145 ;
        RECT 125.000 50.470 125.230 58.870 ;
        RECT 125.480 58.730 125.710 65.355 ;
        RECT 125.960 65.295 126.190 65.355 ;
        RECT 125.895 58.870 126.255 65.295 ;
        RECT 125.410 52.145 125.790 58.730 ;
        RECT 124.925 40.590 125.305 50.470 ;
        RECT 125.000 35.840 125.230 40.590 ;
        RECT 124.935 29.415 125.295 35.840 ;
        RECT 125.000 29.355 125.230 29.415 ;
        RECT 125.480 29.355 125.710 52.145 ;
        RECT 125.960 50.470 126.190 58.870 ;
        RECT 126.440 58.730 126.670 65.355 ;
        RECT 126.920 65.295 127.150 65.355 ;
        RECT 126.855 58.870 127.215 65.295 ;
        RECT 126.365 52.145 126.745 58.730 ;
        RECT 125.885 40.590 126.265 50.470 ;
        RECT 125.960 35.840 126.190 40.590 ;
        RECT 125.895 29.415 126.255 35.840 ;
        RECT 125.960 29.355 126.190 29.415 ;
        RECT 126.440 29.355 126.670 52.145 ;
        RECT 126.920 50.470 127.150 58.870 ;
        RECT 127.400 58.730 127.630 65.355 ;
        RECT 127.880 65.295 128.110 65.355 ;
        RECT 127.815 58.870 128.175 65.295 ;
        RECT 127.330 52.145 127.710 58.730 ;
        RECT 126.845 40.590 127.225 50.470 ;
        RECT 126.920 35.840 127.150 40.590 ;
        RECT 126.855 29.415 127.215 35.840 ;
        RECT 126.920 29.355 127.150 29.415 ;
        RECT 127.400 29.355 127.630 52.145 ;
        RECT 127.880 50.470 128.110 58.870 ;
        RECT 128.360 58.730 128.590 65.355 ;
        RECT 128.840 65.295 129.070 65.355 ;
        RECT 128.775 58.870 129.135 65.295 ;
        RECT 128.285 52.145 128.665 58.730 ;
        RECT 127.805 40.590 128.185 50.470 ;
        RECT 127.880 35.840 128.110 40.590 ;
        RECT 127.815 29.415 128.175 35.840 ;
        RECT 127.880 29.355 128.110 29.415 ;
        RECT 128.360 29.355 128.590 52.145 ;
        RECT 128.840 50.470 129.070 58.870 ;
        RECT 129.320 58.730 129.550 65.355 ;
        RECT 129.800 65.285 130.030 65.355 ;
        RECT 129.735 58.860 130.095 65.285 ;
        RECT 129.250 52.145 129.630 58.730 ;
        RECT 128.765 40.590 129.145 50.470 ;
        RECT 128.840 35.840 129.070 40.590 ;
        RECT 128.775 29.415 129.135 35.840 ;
        RECT 128.840 29.355 129.070 29.415 ;
        RECT 129.320 29.355 129.550 52.145 ;
        RECT 129.800 50.470 130.030 58.860 ;
        RECT 130.280 58.730 130.510 65.355 ;
        RECT 130.760 65.285 130.990 65.355 ;
        RECT 130.695 58.860 131.055 65.285 ;
        RECT 130.205 52.145 130.585 58.730 ;
        RECT 129.725 40.590 130.105 50.470 ;
        RECT 129.800 35.840 130.030 40.590 ;
        RECT 129.735 29.415 130.095 35.840 ;
        RECT 129.800 29.355 130.030 29.415 ;
        RECT 130.280 29.355 130.510 52.145 ;
        RECT 130.760 50.470 130.990 58.860 ;
        RECT 131.240 58.730 131.470 65.355 ;
        RECT 131.720 65.285 131.950 65.355 ;
        RECT 131.655 58.860 132.015 65.285 ;
        RECT 131.170 52.145 131.550 58.730 ;
        RECT 130.685 40.590 131.065 50.470 ;
        RECT 130.760 35.840 130.990 40.590 ;
        RECT 130.695 29.415 131.055 35.840 ;
        RECT 130.760 29.355 130.990 29.415 ;
        RECT 131.240 29.355 131.470 52.145 ;
        RECT 131.720 50.470 131.950 58.860 ;
        RECT 132.200 58.730 132.430 65.355 ;
        RECT 132.680 65.285 132.910 65.355 ;
        RECT 132.615 58.860 132.975 65.285 ;
        RECT 132.125 52.145 132.505 58.730 ;
        RECT 131.645 40.590 132.025 50.470 ;
        RECT 131.720 35.840 131.950 40.590 ;
        RECT 131.655 29.415 132.015 35.840 ;
        RECT 131.720 29.355 131.950 29.415 ;
        RECT 132.200 29.355 132.430 52.145 ;
        RECT 132.680 50.470 132.910 58.860 ;
        RECT 133.160 58.730 133.390 65.355 ;
        RECT 133.640 65.285 133.870 65.355 ;
        RECT 133.575 58.860 133.935 65.285 ;
        RECT 133.090 52.145 133.470 58.730 ;
        RECT 132.605 40.590 132.985 50.470 ;
        RECT 132.680 35.840 132.910 40.590 ;
        RECT 132.615 29.415 132.975 35.840 ;
        RECT 132.680 29.355 132.910 29.415 ;
        RECT 133.160 29.355 133.390 52.145 ;
        RECT 133.640 50.470 133.870 58.860 ;
        RECT 134.120 58.730 134.350 65.355 ;
        RECT 134.600 65.285 134.830 65.355 ;
        RECT 134.535 58.860 134.895 65.285 ;
        RECT 134.045 52.145 134.425 58.730 ;
        RECT 133.565 40.590 133.945 50.470 ;
        RECT 133.640 35.840 133.870 40.590 ;
        RECT 133.575 29.415 133.935 35.840 ;
        RECT 133.640 29.355 133.870 29.415 ;
        RECT 134.120 29.355 134.350 52.145 ;
        RECT 134.600 50.470 134.830 58.860 ;
        RECT 135.080 58.730 135.310 65.355 ;
        RECT 135.560 65.285 135.790 65.355 ;
        RECT 135.495 58.860 135.855 65.285 ;
        RECT 135.010 52.145 135.390 58.730 ;
        RECT 134.525 40.590 134.905 50.470 ;
        RECT 134.600 35.840 134.830 40.590 ;
        RECT 134.535 29.415 134.895 35.840 ;
        RECT 134.600 29.355 134.830 29.415 ;
        RECT 135.080 29.355 135.310 52.145 ;
        RECT 135.560 50.470 135.790 58.860 ;
        RECT 136.040 58.730 136.270 65.355 ;
        RECT 136.520 65.285 136.750 65.355 ;
        RECT 136.455 58.860 136.815 65.285 ;
        RECT 135.965 52.145 136.345 58.730 ;
        RECT 135.485 40.590 135.865 50.470 ;
        RECT 135.560 35.840 135.790 40.590 ;
        RECT 135.495 29.415 135.855 35.840 ;
        RECT 135.560 29.355 135.790 29.415 ;
        RECT 136.040 29.355 136.270 52.145 ;
        RECT 136.520 50.470 136.750 58.860 ;
        RECT 137.000 58.730 137.230 65.355 ;
        RECT 137.480 65.285 137.710 65.355 ;
        RECT 137.415 58.860 137.775 65.285 ;
        RECT 136.930 52.145 137.310 58.730 ;
        RECT 136.445 40.590 136.825 50.470 ;
        RECT 136.520 35.840 136.750 40.590 ;
        RECT 136.455 29.415 136.815 35.840 ;
        RECT 136.520 29.355 136.750 29.415 ;
        RECT 137.000 29.355 137.230 52.145 ;
        RECT 137.480 50.470 137.710 58.860 ;
        RECT 137.960 58.705 138.190 65.355 ;
        RECT 138.440 65.285 139.720 65.355 ;
        RECT 138.365 58.860 139.720 65.285 ;
        RECT 137.885 52.120 138.265 58.705 ;
        RECT 137.405 40.590 137.785 50.470 ;
        RECT 137.480 35.840 137.710 40.590 ;
        RECT 137.415 29.415 137.775 35.840 ;
        RECT 137.480 29.355 137.710 29.415 ;
        RECT 137.960 29.355 138.190 52.120 ;
        RECT 138.440 29.355 139.720 58.860 ;
        RECT 142.700 64.815 149.130 65.105 ;
        RECT 142.700 55.935 142.990 64.815 ;
        RECT 143.390 63.820 144.250 64.090 ;
        RECT 144.795 63.820 145.145 64.520 ;
        RECT 145.425 63.820 145.775 64.090 ;
        RECT 146.055 63.820 146.405 64.090 ;
        RECT 146.685 63.820 147.035 64.520 ;
        RECT 147.580 63.820 148.440 64.090 ;
        RECT 143.390 62.135 143.620 63.820 ;
        RECT 144.020 62.135 144.250 63.820 ;
        RECT 143.375 61.495 143.635 62.135 ;
        RECT 144.005 61.495 144.265 62.135 ;
        RECT 143.390 56.840 143.620 61.495 ;
        RECT 144.020 56.840 144.250 61.495 ;
        RECT 144.540 60.505 144.770 63.630 ;
        RECT 144.525 59.865 144.785 60.505 ;
        RECT 144.540 57.030 144.770 59.865 ;
        RECT 145.170 57.910 145.400 63.630 ;
        RECT 145.800 63.465 146.030 63.630 ;
        RECT 145.785 62.825 146.045 63.465 ;
        RECT 145.155 57.270 145.415 57.910 ;
        RECT 145.170 57.030 145.400 57.270 ;
        RECT 145.800 57.030 146.030 62.825 ;
        RECT 146.430 57.910 146.660 63.630 ;
        RECT 147.060 60.505 147.290 63.630 ;
        RECT 147.580 62.135 147.810 63.820 ;
        RECT 148.210 62.135 148.440 63.820 ;
        RECT 147.565 61.525 147.825 62.135 ;
        RECT 148.195 61.525 148.455 62.135 ;
        RECT 147.045 59.865 147.305 60.505 ;
        RECT 146.415 57.270 146.675 57.910 ;
        RECT 146.430 57.030 146.660 57.270 ;
        RECT 147.060 57.030 147.290 59.865 ;
        RECT 147.580 56.840 147.810 61.525 ;
        RECT 148.210 56.840 148.440 61.525 ;
        RECT 143.390 56.590 144.250 56.840 ;
        RECT 143.495 56.570 144.200 56.590 ;
        RECT 144.795 56.140 145.145 56.840 ;
        RECT 145.425 56.570 145.775 56.840 ;
        RECT 146.055 56.570 146.405 56.840 ;
        RECT 146.685 56.140 147.035 56.840 ;
        RECT 147.580 56.590 148.440 56.840 ;
        RECT 147.580 56.570 148.350 56.590 ;
        RECT 142.700 55.930 144.525 55.935 ;
        RECT 148.840 55.930 149.130 64.815 ;
        RECT 151.505 64.815 167.125 65.105 ;
        RECT 151.505 57.130 151.795 64.815 ;
        RECT 152.365 63.665 153.875 63.935 ;
        RECT 154.420 63.665 155.420 64.365 ;
        RECT 155.700 63.665 156.700 63.935 ;
        RECT 156.980 63.665 157.980 63.935 ;
        RECT 158.260 63.665 159.260 64.365 ;
        RECT 159.540 63.665 160.540 64.365 ;
        RECT 160.820 63.665 161.820 63.935 ;
        RECT 162.100 63.665 163.100 63.935 ;
        RECT 163.380 63.665 164.380 64.365 ;
        RECT 164.925 63.665 166.435 63.935 ;
        RECT 152.365 63.465 152.595 63.665 ;
        RECT 153.645 63.465 153.875 63.665 ;
        RECT 152.350 62.455 152.610 63.465 ;
        RECT 153.630 62.455 153.890 63.465 ;
        RECT 152.365 59.365 152.595 62.455 ;
        RECT 153.645 59.365 153.875 62.455 ;
        RECT 154.165 62.290 154.395 63.475 ;
        RECT 155.445 63.310 155.675 63.475 ;
        RECT 155.430 62.670 155.690 63.310 ;
        RECT 154.140 61.650 154.400 62.290 ;
        RECT 152.350 58.575 152.610 59.365 ;
        RECT 153.630 58.575 153.890 59.365 ;
        RECT 152.365 58.285 152.595 58.575 ;
        RECT 153.645 58.285 153.875 58.575 ;
        RECT 154.165 58.475 154.395 61.650 ;
        RECT 155.445 61.200 155.675 62.670 ;
        RECT 155.430 60.560 155.690 61.200 ;
        RECT 155.445 59.225 155.675 60.560 ;
        RECT 156.725 60.165 156.955 63.475 ;
        RECT 158.005 63.310 158.235 63.475 ;
        RECT 157.990 62.670 158.250 63.310 ;
        RECT 158.005 61.200 158.235 62.670 ;
        RECT 159.285 62.290 159.515 63.475 ;
        RECT 160.565 63.310 160.795 63.475 ;
        RECT 160.550 62.670 160.810 63.310 ;
        RECT 159.270 61.650 159.530 62.290 ;
        RECT 157.990 60.560 158.250 61.200 ;
        RECT 156.710 59.575 156.970 60.165 ;
        RECT 155.430 58.585 155.690 59.225 ;
        RECT 155.445 58.475 155.675 58.585 ;
        RECT 156.725 58.475 156.955 59.575 ;
        RECT 158.005 59.225 158.235 60.560 ;
        RECT 157.990 58.585 158.250 59.225 ;
        RECT 158.005 58.475 158.235 58.585 ;
        RECT 159.285 58.475 159.515 61.650 ;
        RECT 160.565 61.200 160.795 62.670 ;
        RECT 160.550 60.560 160.810 61.200 ;
        RECT 160.565 59.225 160.795 60.560 ;
        RECT 161.845 60.165 162.075 63.475 ;
        RECT 163.125 63.310 163.355 63.475 ;
        RECT 163.110 62.670 163.370 63.310 ;
        RECT 163.125 61.200 163.355 62.670 ;
        RECT 164.405 62.290 164.635 63.475 ;
        RECT 164.925 63.465 165.155 63.665 ;
        RECT 166.205 63.465 166.435 63.665 ;
        RECT 164.910 62.455 165.170 63.465 ;
        RECT 166.190 62.455 166.450 63.465 ;
        RECT 164.390 61.650 164.650 62.290 ;
        RECT 163.110 60.560 163.370 61.200 ;
        RECT 161.830 59.575 162.090 60.165 ;
        RECT 160.550 58.585 160.810 59.225 ;
        RECT 160.565 58.475 160.795 58.585 ;
        RECT 161.845 58.475 162.075 59.575 ;
        RECT 163.125 59.225 163.355 60.560 ;
        RECT 163.110 58.585 163.370 59.225 ;
        RECT 163.125 58.475 163.355 58.585 ;
        RECT 164.405 58.475 164.635 61.650 ;
        RECT 164.925 59.365 165.155 62.455 ;
        RECT 166.205 59.365 166.435 62.455 ;
        RECT 164.910 58.485 165.170 59.365 ;
        RECT 166.190 58.485 166.450 59.365 ;
        RECT 164.925 58.285 165.155 58.485 ;
        RECT 166.205 58.285 166.435 58.485 ;
        RECT 152.365 58.035 153.875 58.285 ;
        RECT 152.425 58.015 153.875 58.035 ;
        RECT 154.420 57.580 155.420 58.285 ;
        RECT 155.700 58.015 156.700 58.285 ;
        RECT 156.980 58.015 157.980 58.285 ;
        RECT 158.260 57.580 159.260 58.285 ;
        RECT 159.540 57.580 160.540 58.285 ;
        RECT 160.820 58.015 161.820 58.285 ;
        RECT 162.100 58.015 163.100 58.285 ;
        RECT 163.380 57.580 164.380 58.285 ;
        RECT 164.925 58.035 166.435 58.285 ;
        RECT 164.990 58.015 166.435 58.035 ;
        RECT 166.835 57.130 167.125 64.815 ;
        RECT 151.505 56.840 167.125 57.130 ;
        RECT 161.015 56.800 162.935 56.840 ;
        RECT 142.700 55.640 149.130 55.930 ;
        RECT 152.500 55.090 157.950 55.380 ;
        RECT 142.700 54.670 146.830 54.720 ;
        RECT 142.700 54.405 151.440 54.670 ;
        RECT 142.700 52.490 142.990 54.405 ;
        RECT 146.540 54.380 151.440 54.405 ;
        RECT 143.375 53.900 143.980 54.170 ;
        RECT 145.520 53.900 146.125 54.170 ;
        RECT 143.375 53.510 143.605 53.900 ;
        RECT 143.360 53.190 143.620 53.510 ;
        RECT 144.005 53.500 144.235 53.710 ;
        RECT 144.610 53.500 144.930 53.760 ;
        RECT 145.265 53.500 145.495 53.710 ;
        RECT 145.895 53.510 146.125 53.900 ;
        RECT 143.375 53.020 143.620 53.190 ;
        RECT 143.990 53.180 144.250 53.500 ;
        RECT 144.635 53.210 144.865 53.500 ;
        RECT 145.215 53.210 145.495 53.500 ;
        RECT 145.215 53.180 145.475 53.210 ;
        RECT 145.880 53.190 146.140 53.510 ;
        RECT 145.880 53.020 146.125 53.190 ;
        RECT 143.375 52.770 143.980 53.020 ;
        RECT 143.470 52.750 143.980 52.770 ;
        RECT 145.520 52.750 146.125 53.020 ;
        RECT 146.540 52.520 147.190 54.380 ;
        RECT 147.610 53.850 148.470 54.120 ;
        RECT 147.610 53.590 147.840 53.850 ;
        RECT 147.595 53.260 147.855 53.590 ;
        RECT 147.610 53.050 147.840 53.260 ;
        RECT 148.240 53.050 148.470 53.850 ;
        RECT 149.910 53.850 150.770 54.120 ;
        RECT 148.760 53.605 148.990 53.660 ;
        RECT 149.390 53.610 149.620 53.660 ;
        RECT 148.745 53.285 149.005 53.605 ;
        RECT 149.380 53.290 149.640 53.610 ;
        RECT 149.910 53.590 150.140 53.850 ;
        RECT 150.540 53.590 150.770 53.850 ;
        RECT 151.150 53.590 151.440 54.380 ;
        RECT 148.760 53.240 148.990 53.285 ;
        RECT 149.390 53.240 149.620 53.290 ;
        RECT 149.895 53.255 150.155 53.590 ;
        RECT 150.525 53.255 150.785 53.590 ;
        RECT 151.150 53.260 151.460 53.590 ;
        RECT 147.610 52.800 148.470 53.050 ;
        RECT 149.910 53.050 150.140 53.255 ;
        RECT 150.540 53.050 150.770 53.255 ;
        RECT 147.695 52.780 148.360 52.800 ;
        RECT 149.910 52.780 150.770 53.050 ;
        RECT 151.150 52.520 151.440 53.260 ;
        RECT 146.540 52.490 151.440 52.520 ;
        RECT 142.700 52.230 151.440 52.490 ;
        RECT 152.500 52.245 152.790 55.090 ;
        RECT 153.190 54.560 154.120 54.830 ;
        RECT 153.190 54.415 153.420 54.560 ;
        RECT 153.890 54.415 154.120 54.560 ;
        RECT 156.330 54.560 157.260 54.830 ;
        RECT 153.175 54.095 153.435 54.415 ;
        RECT 153.875 54.095 154.135 54.415 ;
        RECT 153.190 53.550 153.420 54.095 ;
        RECT 153.890 53.550 154.120 54.095 ;
        RECT 154.410 53.970 154.640 54.370 ;
        RECT 155.110 54.360 155.340 54.370 ;
        RECT 155.095 54.040 155.355 54.360 ;
        RECT 154.395 53.650 154.655 53.970 ;
        RECT 153.175 53.230 153.435 53.550 ;
        RECT 153.875 53.230 154.135 53.550 ;
        RECT 153.190 52.680 153.420 53.230 ;
        RECT 153.890 52.680 154.120 53.230 ;
        RECT 154.410 52.870 154.640 53.650 ;
        RECT 155.110 53.610 155.340 54.040 ;
        RECT 155.095 53.290 155.355 53.610 ;
        RECT 155.110 52.870 155.340 53.290 ;
        RECT 155.810 53.195 156.040 54.370 ;
        RECT 156.330 54.360 156.560 54.560 ;
        RECT 157.030 54.360 157.260 54.560 ;
        RECT 156.315 54.040 156.575 54.360 ;
        RECT 157.015 54.040 157.275 54.360 ;
        RECT 156.330 53.610 156.560 54.040 ;
        RECT 157.030 53.610 157.260 54.040 ;
        RECT 156.315 53.290 156.575 53.610 ;
        RECT 157.015 53.290 157.275 53.610 ;
        RECT 155.795 52.875 156.055 53.195 ;
        RECT 155.810 52.870 156.040 52.875 ;
        RECT 153.190 52.430 154.120 52.680 ;
        RECT 156.330 52.680 156.560 53.290 ;
        RECT 157.030 52.680 157.260 53.290 ;
        RECT 156.330 52.430 157.260 52.680 ;
        RECT 153.260 52.410 154.020 52.430 ;
        RECT 156.330 52.410 157.150 52.430 ;
        RECT 157.660 52.245 157.950 55.090 ;
        RECT 160.790 55.205 167.580 55.495 ;
        RECT 160.790 55.150 163.785 55.205 ;
        RECT 160.790 52.320 161.080 55.150 ;
        RECT 161.480 52.320 162.140 54.575 ;
        RECT 162.595 54.305 162.925 54.995 ;
        RECT 163.545 54.305 163.875 54.575 ;
        RECT 164.495 54.305 164.825 54.575 ;
        RECT 165.445 54.305 165.775 54.995 ;
        RECT 162.430 53.610 162.660 54.115 ;
        RECT 162.415 53.290 162.675 53.610 ;
        RECT 142.700 52.215 151.280 52.230 ;
        RECT 142.700 52.200 146.830 52.215 ;
        RECT 152.500 51.860 157.950 52.245 ;
        RECT 160.775 52.000 161.080 52.320 ;
        RECT 161.465 52.000 162.155 52.320 ;
        RECT 142.730 50.315 147.220 50.575 ;
        RECT 142.730 49.460 142.960 50.315 ;
        RECT 143.645 49.770 143.995 50.040 ;
        RECT 143.390 49.460 143.620 49.580 ;
        RECT 144.020 49.460 144.250 49.580 ;
        RECT 144.680 49.460 145.270 50.315 ;
        RECT 145.955 49.770 146.305 50.040 ;
        RECT 145.700 49.460 145.930 49.580 ;
        RECT 146.330 49.460 146.560 49.580 ;
        RECT 146.990 49.460 147.220 50.315 ;
        RECT 160.790 50.505 161.080 52.000 ;
        RECT 161.480 51.155 162.140 52.000 ;
        RECT 162.430 51.615 162.660 53.290 ;
        RECT 162.860 52.775 163.090 54.115 ;
        RECT 162.845 52.455 163.105 52.775 ;
        RECT 162.860 51.615 163.090 52.455 ;
        RECT 163.380 51.950 163.610 54.115 ;
        RECT 163.810 54.095 164.040 54.115 ;
        RECT 163.795 53.775 164.055 54.095 ;
        RECT 163.365 51.620 163.625 51.950 ;
        RECT 163.380 51.615 163.610 51.620 ;
        RECT 163.810 51.615 164.040 53.775 ;
        RECT 164.330 51.950 164.560 54.115 ;
        RECT 164.760 54.095 164.990 54.115 ;
        RECT 164.745 53.775 165.005 54.095 ;
        RECT 164.315 51.620 164.575 51.950 ;
        RECT 164.330 51.615 164.560 51.620 ;
        RECT 164.760 51.615 164.990 53.775 ;
        RECT 165.280 53.610 165.510 54.115 ;
        RECT 165.265 53.290 165.525 53.610 ;
        RECT 165.280 51.615 165.510 53.290 ;
        RECT 165.710 52.770 165.940 54.115 ;
        RECT 165.695 52.450 165.955 52.770 ;
        RECT 165.710 51.615 165.940 52.450 ;
        RECT 166.230 52.310 166.890 54.575 ;
        RECT 166.215 51.990 166.905 52.310 ;
        RECT 162.595 50.715 162.925 51.425 ;
        RECT 163.545 51.155 163.875 51.425 ;
        RECT 164.495 51.155 164.825 51.425 ;
        RECT 165.445 50.715 165.775 51.425 ;
        RECT 166.230 51.155 166.890 51.990 ;
        RECT 167.290 50.505 167.580 55.205 ;
        RECT 160.790 50.235 167.580 50.505 ;
        RECT 159.010 50.215 168.010 50.235 ;
        RECT 168.825 50.215 169.600 50.235 ;
        RECT 147.980 49.805 154.465 50.095 ;
        RECT 147.980 49.745 148.325 49.805 ;
        RECT 142.715 49.140 142.975 49.460 ;
        RECT 143.375 49.140 143.635 49.460 ;
        RECT 144.005 49.140 144.265 49.460 ;
        RECT 144.665 49.140 145.285 49.460 ;
        RECT 145.685 49.140 145.945 49.460 ;
        RECT 146.315 49.140 146.575 49.460 ;
        RECT 146.975 49.140 147.235 49.460 ;
        RECT 142.730 48.285 142.960 49.140 ;
        RECT 143.390 49.030 143.620 49.140 ;
        RECT 144.020 49.030 144.250 49.140 ;
        RECT 143.645 48.570 143.995 48.840 ;
        RECT 144.680 48.295 145.270 49.140 ;
        RECT 145.700 49.030 145.930 49.140 ;
        RECT 146.330 49.030 146.560 49.140 ;
        RECT 145.955 48.570 146.305 48.840 ;
        RECT 146.990 48.295 147.220 49.140 ;
        RECT 144.680 48.285 147.220 48.295 ;
        RECT 142.730 48.035 147.220 48.285 ;
        RECT 142.730 48.025 144.910 48.035 ;
        RECT 148.035 47.970 148.325 49.745 ;
        RECT 148.725 48.880 149.585 49.150 ;
        RECT 150.130 48.880 150.480 49.595 ;
        RECT 150.760 48.880 151.110 49.150 ;
        RECT 151.390 48.880 151.740 49.150 ;
        RECT 152.020 48.880 152.370 49.595 ;
        RECT 152.915 48.880 153.775 49.150 ;
        RECT 148.725 48.690 148.955 48.880 ;
        RECT 148.710 48.250 148.970 48.690 ;
        RECT 142.925 47.220 146.935 47.480 ;
        RECT 142.895 46.485 143.125 47.075 ;
        RECT 143.720 46.675 144.050 46.945 ;
        RECT 142.880 45.845 143.140 46.485 ;
        RECT 143.535 45.845 143.795 46.485 ;
        RECT 143.970 45.845 144.230 46.485 ;
        RECT 142.895 45.085 143.125 45.845 ;
        RECT 143.555 45.085 143.785 45.845 ;
        RECT 143.985 45.085 144.215 45.845 ;
        RECT 142.880 44.445 143.140 45.085 ;
        RECT 143.535 44.445 143.795 45.085 ;
        RECT 143.970 44.445 144.230 45.085 ;
        RECT 142.895 43.610 143.125 44.445 ;
        RECT 143.555 43.610 143.785 44.445 ;
        RECT 143.985 43.610 144.215 44.445 ;
        RECT 142.880 42.970 143.140 43.610 ;
        RECT 143.535 42.970 143.795 43.610 ;
        RECT 143.970 42.970 144.230 43.610 ;
        RECT 142.895 42.125 143.125 42.970 ;
        RECT 143.555 42.125 143.785 42.970 ;
        RECT 143.985 42.125 144.215 42.970 ;
        RECT 142.880 41.485 143.140 42.125 ;
        RECT 143.535 41.485 143.795 42.125 ;
        RECT 143.970 41.485 144.230 42.125 ;
        RECT 142.895 40.750 143.125 41.485 ;
        RECT 143.720 41.025 144.050 41.295 ;
        RECT 144.690 40.750 145.215 47.220 ;
        RECT 145.810 46.675 146.140 46.945 ;
        RECT 146.780 46.485 146.935 47.220 ;
        RECT 148.010 46.575 148.325 47.970 ;
        RECT 148.725 47.500 148.955 48.250 ;
        RECT 149.355 47.500 149.585 48.880 ;
        RECT 149.875 47.960 150.105 48.690 ;
        RECT 150.490 48.420 150.750 48.740 ;
        RECT 149.860 47.640 150.120 47.960 ;
        RECT 150.505 47.690 150.735 48.420 ;
        RECT 151.135 48.335 151.365 48.690 ;
        RECT 151.750 48.400 152.010 48.720 ;
        RECT 151.120 48.015 151.380 48.335 ;
        RECT 151.135 47.690 151.365 48.015 ;
        RECT 151.765 47.690 151.995 48.400 ;
        RECT 152.395 47.930 152.625 48.690 ;
        RECT 152.350 47.670 152.670 47.930 ;
        RECT 152.915 47.500 153.145 48.880 ;
        RECT 153.545 48.690 153.775 48.880 ;
        RECT 153.530 48.250 153.790 48.690 ;
        RECT 153.545 47.500 153.775 48.250 ;
        RECT 148.725 47.250 149.585 47.500 ;
        RECT 148.785 47.230 149.480 47.250 ;
        RECT 150.130 46.785 150.480 47.500 ;
        RECT 150.760 47.230 151.110 47.500 ;
        RECT 151.390 47.230 151.740 47.500 ;
        RECT 152.020 46.830 152.370 47.500 ;
        RECT 152.915 47.250 153.775 47.500 ;
        RECT 152.975 47.230 153.765 47.250 ;
        RECT 148.625 46.575 149.115 46.580 ;
        RECT 151.805 46.575 152.295 46.580 ;
        RECT 153.395 46.575 153.885 46.580 ;
        RECT 154.175 46.575 154.465 49.805 ;
        RECT 145.630 45.845 145.890 46.485 ;
        RECT 146.060 45.845 146.320 46.485 ;
        RECT 146.745 45.845 147.005 46.485 ;
        RECT 148.010 46.290 154.465 46.575 ;
        RECT 148.035 46.285 154.465 46.290 ;
        RECT 159.010 49.240 169.600 50.215 ;
        RECT 145.645 45.085 145.875 45.845 ;
        RECT 146.075 45.085 146.305 45.845 ;
        RECT 145.630 44.445 145.890 45.085 ;
        RECT 146.060 44.445 146.320 45.085 ;
        RECT 146.780 44.990 146.935 45.845 ;
        RECT 146.675 44.450 146.935 44.990 ;
        RECT 145.645 43.610 145.875 44.445 ;
        RECT 146.075 43.610 146.305 44.445 ;
        RECT 146.780 43.610 146.920 44.450 ;
        RECT 145.630 42.970 145.890 43.610 ;
        RECT 146.060 42.970 146.320 43.610 ;
        RECT 146.720 42.970 146.980 43.610 ;
        RECT 148.785 43.085 156.555 43.385 ;
        RECT 145.645 42.125 145.875 42.970 ;
        RECT 146.075 42.125 146.305 42.970 ;
        RECT 146.780 42.125 146.920 42.970 ;
        RECT 145.630 41.485 145.890 42.125 ;
        RECT 146.060 41.485 146.320 42.125 ;
        RECT 146.720 41.485 146.980 42.125 ;
        RECT 145.810 41.290 146.140 41.295 ;
        RECT 145.810 41.030 146.155 41.290 ;
        RECT 145.810 41.025 146.140 41.030 ;
        RECT 146.780 40.750 146.920 41.485 ;
        RECT 148.785 41.155 149.075 43.085 ;
        RECT 149.325 42.565 150.835 42.835 ;
        RECT 149.325 42.465 149.570 42.565 ;
        RECT 149.310 42.145 149.570 42.465 ;
        RECT 149.325 41.685 149.555 42.145 ;
        RECT 150.605 41.685 150.835 42.565 ;
        RECT 154.205 42.565 155.715 42.835 ;
        RECT 151.125 42.085 151.355 42.375 ;
        RECT 152.370 42.165 152.690 42.425 ;
        RECT 151.080 41.825 151.400 42.085 ;
        RECT 152.405 41.875 152.635 42.165 ;
        RECT 153.685 42.085 153.915 42.375 ;
        RECT 153.640 41.825 153.960 42.085 ;
        RECT 149.325 41.415 150.835 41.685 ;
        RECT 154.205 41.685 154.435 42.565 ;
        RECT 155.475 42.425 155.715 42.565 ;
        RECT 155.475 42.105 155.735 42.425 ;
        RECT 155.485 41.685 155.715 42.105 ;
        RECT 154.205 41.415 155.715 41.685 ;
        RECT 156.265 41.155 156.555 43.085 ;
        RECT 148.785 40.865 156.555 41.155 ;
        RECT 142.895 40.505 146.920 40.750 ;
        RECT 143.195 40.490 146.915 40.505 ;
        RECT 159.010 33.110 159.300 49.240 ;
        RECT 159.700 48.710 160.360 48.985 ;
        RECT 159.700 48.520 159.930 48.710 ;
        RECT 160.130 48.520 160.360 48.710 ;
        RECT 160.650 48.710 161.310 48.985 ;
        RECT 160.650 48.520 160.880 48.710 ;
        RECT 161.080 48.520 161.310 48.710 ;
        RECT 161.600 48.710 162.260 48.985 ;
        RECT 161.600 48.520 161.830 48.710 ;
        RECT 162.030 48.520 162.260 48.710 ;
        RECT 162.550 48.710 163.210 48.985 ;
        RECT 162.550 48.520 162.780 48.710 ;
        RECT 162.980 48.520 163.210 48.710 ;
        RECT 163.500 48.710 164.160 48.985 ;
        RECT 163.500 48.520 163.730 48.710 ;
        RECT 163.930 48.520 164.160 48.710 ;
        RECT 164.450 48.710 165.110 48.985 ;
        RECT 164.450 48.520 164.680 48.710 ;
        RECT 164.880 48.520 165.110 48.710 ;
        RECT 165.400 48.710 166.060 48.985 ;
        RECT 165.400 48.520 165.630 48.710 ;
        RECT 165.830 48.520 166.060 48.710 ;
        RECT 166.350 48.710 167.010 48.985 ;
        RECT 166.350 48.520 166.580 48.710 ;
        RECT 166.780 48.520 167.010 48.710 ;
        RECT 167.300 48.710 167.960 48.985 ;
        RECT 167.300 48.520 167.530 48.710 ;
        RECT 167.730 48.520 167.960 48.710 ;
        RECT 168.250 48.710 168.910 48.985 ;
        RECT 168.250 48.520 168.480 48.710 ;
        RECT 168.680 48.520 168.910 48.710 ;
        RECT 159.685 48.190 159.945 48.520 ;
        RECT 160.115 48.190 160.375 48.520 ;
        RECT 160.635 48.190 160.895 48.520 ;
        RECT 161.065 48.190 161.325 48.520 ;
        RECT 161.585 48.190 161.845 48.520 ;
        RECT 162.015 48.190 162.275 48.520 ;
        RECT 162.535 48.190 162.795 48.520 ;
        RECT 162.965 48.190 163.225 48.520 ;
        RECT 163.485 48.190 163.745 48.520 ;
        RECT 163.915 48.190 164.175 48.520 ;
        RECT 164.435 48.190 164.695 48.520 ;
        RECT 164.865 48.190 165.125 48.520 ;
        RECT 165.385 48.190 165.645 48.520 ;
        RECT 165.815 48.190 166.075 48.520 ;
        RECT 166.335 48.190 166.595 48.520 ;
        RECT 166.765 48.190 167.025 48.520 ;
        RECT 167.285 48.190 167.545 48.520 ;
        RECT 167.715 48.190 167.975 48.520 ;
        RECT 168.235 48.190 168.495 48.520 ;
        RECT 168.665 48.190 168.925 48.520 ;
        RECT 159.700 47.865 159.930 48.190 ;
        RECT 160.130 47.865 160.360 48.190 ;
        RECT 160.650 47.865 160.880 48.190 ;
        RECT 161.080 47.865 161.310 48.190 ;
        RECT 161.600 47.865 161.830 48.190 ;
        RECT 162.030 47.865 162.260 48.190 ;
        RECT 162.550 47.865 162.780 48.190 ;
        RECT 162.980 47.865 163.210 48.190 ;
        RECT 163.500 47.865 163.730 48.190 ;
        RECT 163.930 47.865 164.160 48.190 ;
        RECT 164.450 47.865 164.680 48.190 ;
        RECT 164.880 47.865 165.110 48.190 ;
        RECT 165.400 47.865 165.630 48.190 ;
        RECT 165.830 47.865 166.060 48.190 ;
        RECT 166.350 47.865 166.580 48.190 ;
        RECT 166.780 47.865 167.010 48.190 ;
        RECT 167.300 47.865 167.530 48.190 ;
        RECT 167.730 47.865 167.960 48.190 ;
        RECT 168.250 47.865 168.480 48.190 ;
        RECT 168.680 47.865 168.910 48.190 ;
        RECT 159.685 47.530 159.945 47.865 ;
        RECT 160.115 47.530 160.375 47.865 ;
        RECT 160.635 47.530 160.895 47.865 ;
        RECT 161.065 47.530 161.325 47.865 ;
        RECT 161.585 47.530 161.845 47.865 ;
        RECT 162.015 47.530 162.275 47.865 ;
        RECT 162.535 47.530 162.795 47.865 ;
        RECT 162.965 47.530 163.225 47.865 ;
        RECT 163.485 47.530 163.745 47.865 ;
        RECT 163.915 47.530 164.175 47.865 ;
        RECT 164.435 47.530 164.695 47.865 ;
        RECT 164.865 47.530 165.125 47.865 ;
        RECT 165.385 47.530 165.645 47.865 ;
        RECT 165.815 47.530 166.075 47.865 ;
        RECT 166.335 47.530 166.595 47.865 ;
        RECT 166.765 47.530 167.025 47.865 ;
        RECT 167.285 47.530 167.545 47.865 ;
        RECT 167.715 47.530 167.975 47.865 ;
        RECT 168.235 47.530 168.495 47.865 ;
        RECT 168.665 47.530 168.925 47.865 ;
        RECT 159.700 47.095 159.930 47.530 ;
        RECT 160.130 47.095 160.360 47.530 ;
        RECT 160.650 47.095 160.880 47.530 ;
        RECT 161.080 47.095 161.310 47.530 ;
        RECT 161.600 47.095 161.830 47.530 ;
        RECT 162.030 47.095 162.260 47.530 ;
        RECT 162.550 47.095 162.780 47.530 ;
        RECT 162.980 47.095 163.210 47.530 ;
        RECT 163.500 47.095 163.730 47.530 ;
        RECT 163.930 47.095 164.160 47.530 ;
        RECT 164.450 47.095 164.680 47.530 ;
        RECT 164.880 47.095 165.110 47.530 ;
        RECT 165.400 47.095 165.630 47.530 ;
        RECT 165.830 47.095 166.060 47.530 ;
        RECT 166.350 47.095 166.580 47.530 ;
        RECT 166.780 47.095 167.010 47.530 ;
        RECT 167.300 47.095 167.530 47.530 ;
        RECT 167.730 47.095 167.960 47.530 ;
        RECT 168.250 47.095 168.480 47.530 ;
        RECT 168.680 47.095 168.910 47.530 ;
        RECT 159.685 46.765 159.945 47.095 ;
        RECT 160.115 46.765 160.375 47.095 ;
        RECT 160.635 46.765 160.895 47.095 ;
        RECT 161.065 46.765 161.325 47.095 ;
        RECT 161.585 46.765 161.845 47.095 ;
        RECT 162.015 46.765 162.275 47.095 ;
        RECT 162.535 46.765 162.795 47.095 ;
        RECT 162.965 46.765 163.225 47.095 ;
        RECT 163.485 46.765 163.745 47.095 ;
        RECT 163.915 46.765 164.175 47.095 ;
        RECT 164.435 46.765 164.695 47.095 ;
        RECT 164.865 46.765 165.125 47.095 ;
        RECT 165.385 46.765 165.645 47.095 ;
        RECT 165.815 46.765 166.075 47.095 ;
        RECT 166.335 46.765 166.595 47.095 ;
        RECT 166.765 46.765 167.025 47.095 ;
        RECT 167.285 46.765 167.545 47.095 ;
        RECT 167.715 46.765 167.975 47.095 ;
        RECT 168.235 46.765 168.495 47.095 ;
        RECT 168.665 46.765 168.925 47.095 ;
        RECT 159.700 46.355 159.930 46.765 ;
        RECT 160.130 46.355 160.360 46.765 ;
        RECT 160.650 46.355 160.880 46.765 ;
        RECT 161.080 46.355 161.310 46.765 ;
        RECT 161.600 46.355 161.830 46.765 ;
        RECT 162.030 46.355 162.260 46.765 ;
        RECT 162.550 46.355 162.780 46.765 ;
        RECT 162.980 46.355 163.210 46.765 ;
        RECT 163.500 46.355 163.730 46.765 ;
        RECT 163.930 46.355 164.160 46.765 ;
        RECT 164.450 46.355 164.680 46.765 ;
        RECT 164.880 46.355 165.110 46.765 ;
        RECT 165.400 46.355 165.630 46.765 ;
        RECT 165.830 46.355 166.060 46.765 ;
        RECT 166.350 46.355 166.580 46.765 ;
        RECT 166.780 46.355 167.010 46.765 ;
        RECT 167.300 46.355 167.530 46.765 ;
        RECT 167.730 46.355 167.960 46.765 ;
        RECT 168.250 46.355 168.480 46.765 ;
        RECT 168.680 46.355 168.910 46.765 ;
        RECT 159.685 46.025 159.945 46.355 ;
        RECT 160.115 46.025 160.375 46.355 ;
        RECT 160.635 46.025 160.895 46.355 ;
        RECT 161.065 46.025 161.325 46.355 ;
        RECT 161.585 46.025 161.845 46.355 ;
        RECT 162.015 46.025 162.275 46.355 ;
        RECT 162.535 46.025 162.795 46.355 ;
        RECT 162.965 46.025 163.225 46.355 ;
        RECT 163.485 46.025 163.745 46.355 ;
        RECT 163.915 46.025 164.175 46.355 ;
        RECT 164.435 46.025 164.695 46.355 ;
        RECT 164.865 46.025 165.125 46.355 ;
        RECT 165.385 46.025 165.645 46.355 ;
        RECT 165.815 46.025 166.075 46.355 ;
        RECT 166.335 46.025 166.595 46.355 ;
        RECT 166.765 46.025 167.025 46.355 ;
        RECT 167.285 46.025 167.545 46.355 ;
        RECT 167.715 46.025 167.975 46.355 ;
        RECT 168.235 46.025 168.495 46.355 ;
        RECT 168.665 46.025 168.925 46.355 ;
        RECT 159.700 46.020 159.930 46.025 ;
        RECT 160.130 46.020 160.360 46.025 ;
        RECT 160.650 46.020 160.880 46.025 ;
        RECT 161.080 46.020 161.310 46.025 ;
        RECT 161.600 46.020 161.830 46.025 ;
        RECT 162.030 46.020 162.260 46.025 ;
        RECT 162.550 46.020 162.780 46.025 ;
        RECT 162.980 46.020 163.210 46.025 ;
        RECT 163.500 46.020 163.730 46.025 ;
        RECT 163.930 46.020 164.160 46.025 ;
        RECT 164.450 46.020 164.680 46.025 ;
        RECT 164.880 46.020 165.110 46.025 ;
        RECT 165.400 46.020 165.630 46.025 ;
        RECT 165.830 46.020 166.060 46.025 ;
        RECT 166.350 46.020 166.580 46.025 ;
        RECT 166.780 46.020 167.010 46.025 ;
        RECT 167.300 46.020 167.530 46.025 ;
        RECT 167.730 46.020 167.960 46.025 ;
        RECT 168.250 46.020 168.480 46.025 ;
        RECT 168.680 46.020 168.910 46.025 ;
        RECT 159.745 44.750 160.315 45.020 ;
        RECT 160.815 44.750 161.145 45.350 ;
        RECT 161.765 44.750 162.095 45.775 ;
        RECT 162.715 44.750 163.045 45.775 ;
        RECT 163.665 44.750 163.995 45.350 ;
        RECT 164.615 44.750 164.945 45.350 ;
        RECT 165.565 44.750 165.895 45.775 ;
        RECT 166.515 44.750 166.845 45.775 ;
        RECT 167.465 44.750 167.795 45.350 ;
        RECT 168.295 44.750 168.865 45.020 ;
        RECT 159.745 44.560 159.885 44.750 ;
        RECT 160.175 44.560 160.315 44.750 ;
        RECT 168.295 44.560 168.435 44.750 ;
        RECT 168.725 44.560 168.865 44.750 ;
        RECT 159.685 44.230 159.945 44.560 ;
        RECT 160.115 44.230 160.375 44.560 ;
        RECT 160.635 44.230 160.895 44.560 ;
        RECT 159.700 42.395 159.930 44.230 ;
        RECT 160.130 42.395 160.360 44.230 ;
        RECT 160.650 42.395 160.880 44.230 ;
        RECT 161.080 43.905 161.310 44.560 ;
        RECT 161.585 44.230 161.845 44.560 ;
        RECT 161.065 43.575 161.325 43.905 ;
        RECT 159.685 42.060 159.945 42.395 ;
        RECT 160.115 42.060 160.375 42.395 ;
        RECT 160.635 42.060 160.895 42.395 ;
        RECT 161.080 42.060 161.310 43.575 ;
        RECT 161.600 42.395 161.830 44.230 ;
        RECT 162.030 43.135 162.260 44.560 ;
        RECT 162.535 44.230 162.795 44.560 ;
        RECT 162.015 42.805 162.275 43.135 ;
        RECT 161.585 42.060 161.845 42.395 ;
        RECT 162.030 42.060 162.260 42.805 ;
        RECT 162.550 42.395 162.780 44.230 ;
        RECT 162.980 43.135 163.210 44.560 ;
        RECT 163.485 44.230 163.745 44.560 ;
        RECT 162.965 42.805 163.225 43.135 ;
        RECT 162.535 42.060 162.795 42.395 ;
        RECT 162.980 42.060 163.210 42.805 ;
        RECT 163.500 42.395 163.730 44.230 ;
        RECT 163.930 43.905 164.160 44.560 ;
        RECT 164.435 44.230 164.695 44.560 ;
        RECT 163.915 43.575 164.175 43.905 ;
        RECT 163.485 42.060 163.745 42.395 ;
        RECT 163.930 42.060 164.160 43.575 ;
        RECT 164.450 42.395 164.680 44.230 ;
        RECT 164.880 43.905 165.110 44.560 ;
        RECT 165.385 44.230 165.645 44.560 ;
        RECT 164.865 43.575 165.125 43.905 ;
        RECT 164.435 42.060 164.695 42.395 ;
        RECT 164.880 42.060 165.110 43.575 ;
        RECT 165.400 42.395 165.630 44.230 ;
        RECT 165.830 43.135 166.060 44.560 ;
        RECT 166.335 44.230 166.595 44.560 ;
        RECT 165.815 42.805 166.075 43.135 ;
        RECT 165.385 42.060 165.645 42.395 ;
        RECT 165.830 42.060 166.060 42.805 ;
        RECT 166.350 42.395 166.580 44.230 ;
        RECT 166.780 43.135 167.010 44.560 ;
        RECT 167.285 44.230 167.545 44.560 ;
        RECT 166.765 42.805 167.025 43.135 ;
        RECT 166.335 42.060 166.595 42.395 ;
        RECT 166.780 42.060 167.010 42.805 ;
        RECT 167.300 42.395 167.530 44.230 ;
        RECT 167.730 43.905 167.960 44.560 ;
        RECT 168.235 44.230 168.495 44.560 ;
        RECT 168.665 44.230 168.925 44.560 ;
        RECT 167.715 43.575 167.975 43.905 ;
        RECT 167.285 42.060 167.545 42.395 ;
        RECT 167.730 42.060 167.960 43.575 ;
        RECT 168.250 42.395 168.480 44.230 ;
        RECT 168.680 42.395 168.910 44.230 ;
        RECT 168.235 42.060 168.495 42.395 ;
        RECT 168.665 42.060 168.925 42.395 ;
        RECT 159.745 41.870 159.885 42.060 ;
        RECT 160.130 41.870 160.360 42.060 ;
        RECT 168.250 41.870 168.480 42.060 ;
        RECT 168.725 41.870 168.865 42.060 ;
        RECT 159.745 41.600 160.360 41.870 ;
        RECT 160.815 41.600 161.145 41.870 ;
        RECT 161.765 41.600 163.045 41.870 ;
        RECT 163.665 41.600 164.945 41.870 ;
        RECT 165.565 41.600 166.845 41.870 ;
        RECT 161.765 41.335 162.095 41.600 ;
        RECT 163.665 41.335 163.995 41.600 ;
        RECT 165.565 41.335 165.895 41.600 ;
        RECT 167.465 41.335 167.795 41.870 ;
        RECT 168.250 41.600 168.865 41.870 ;
        RECT 160.815 41.005 162.095 41.335 ;
        RECT 162.715 41.005 163.995 41.335 ;
        RECT 164.615 41.005 165.895 41.335 ;
        RECT 166.515 41.005 167.795 41.335 ;
        RECT 159.745 40.290 160.315 40.750 ;
        RECT 160.815 40.480 161.145 41.005 ;
        RECT 162.715 40.750 163.045 41.005 ;
        RECT 164.615 40.750 164.945 41.005 ;
        RECT 166.515 40.750 166.845 41.005 ;
        RECT 161.765 40.480 163.045 40.750 ;
        RECT 163.665 40.480 164.945 40.750 ;
        RECT 165.565 40.480 166.845 40.750 ;
        RECT 167.465 40.480 167.795 40.750 ;
        RECT 168.250 40.290 168.910 40.750 ;
        RECT 159.685 39.960 160.375 40.290 ;
        RECT 160.635 39.960 160.895 40.290 ;
        RECT 159.700 38.125 160.360 39.960 ;
        RECT 160.650 38.125 160.880 39.960 ;
        RECT 161.080 39.635 161.310 40.290 ;
        RECT 161.585 39.960 161.845 40.290 ;
        RECT 161.065 39.305 161.325 39.635 ;
        RECT 159.685 37.795 160.375 38.125 ;
        RECT 160.635 37.795 160.895 38.125 ;
        RECT 159.700 37.790 160.360 37.795 ;
        RECT 160.650 37.790 160.880 37.795 ;
        RECT 161.080 37.790 161.310 39.305 ;
        RECT 161.600 38.125 161.830 39.960 ;
        RECT 162.030 38.865 162.260 40.290 ;
        RECT 162.535 39.960 162.795 40.290 ;
        RECT 162.015 38.535 162.275 38.865 ;
        RECT 161.585 37.795 161.845 38.125 ;
        RECT 161.600 37.790 161.830 37.795 ;
        RECT 162.030 37.790 162.260 38.535 ;
        RECT 162.550 38.125 162.780 39.960 ;
        RECT 162.980 38.865 163.210 40.290 ;
        RECT 163.485 39.960 163.745 40.290 ;
        RECT 162.965 38.535 163.225 38.865 ;
        RECT 162.535 37.795 162.795 38.125 ;
        RECT 162.550 37.790 162.780 37.795 ;
        RECT 162.980 37.790 163.210 38.535 ;
        RECT 163.500 38.125 163.730 39.960 ;
        RECT 163.930 39.635 164.160 40.290 ;
        RECT 164.435 39.960 164.695 40.290 ;
        RECT 163.915 39.305 164.175 39.635 ;
        RECT 163.485 37.795 163.745 38.125 ;
        RECT 163.500 37.790 163.730 37.795 ;
        RECT 163.930 37.790 164.160 39.305 ;
        RECT 164.450 38.125 164.680 39.960 ;
        RECT 164.880 39.635 165.110 40.290 ;
        RECT 165.385 39.960 165.645 40.290 ;
        RECT 164.865 39.305 165.125 39.635 ;
        RECT 164.435 37.795 164.695 38.125 ;
        RECT 164.450 37.790 164.680 37.795 ;
        RECT 164.880 37.790 165.110 39.305 ;
        RECT 165.400 38.125 165.630 39.960 ;
        RECT 165.830 38.865 166.060 40.290 ;
        RECT 166.335 39.960 166.595 40.290 ;
        RECT 165.815 38.535 166.075 38.865 ;
        RECT 165.385 37.795 165.645 38.125 ;
        RECT 165.400 37.790 165.630 37.795 ;
        RECT 165.830 37.790 166.060 38.535 ;
        RECT 166.350 38.125 166.580 39.960 ;
        RECT 166.780 38.865 167.010 40.290 ;
        RECT 167.285 39.960 167.545 40.290 ;
        RECT 166.765 38.535 167.025 38.865 ;
        RECT 166.335 37.795 166.595 38.125 ;
        RECT 166.350 37.790 166.580 37.795 ;
        RECT 166.780 37.790 167.010 38.535 ;
        RECT 167.300 38.125 167.530 39.960 ;
        RECT 167.730 39.635 167.960 40.290 ;
        RECT 168.235 39.960 168.925 40.290 ;
        RECT 167.715 39.305 167.975 39.635 ;
        RECT 167.285 37.795 167.545 38.125 ;
        RECT 167.300 37.790 167.530 37.795 ;
        RECT 167.730 37.790 167.960 39.305 ;
        RECT 168.250 38.125 168.910 39.960 ;
        RECT 168.235 37.795 168.925 38.125 ;
        RECT 159.745 37.330 160.315 37.790 ;
        RECT 160.815 36.940 161.145 37.600 ;
        RECT 161.765 36.530 162.095 37.600 ;
        RECT 162.715 36.530 163.045 37.600 ;
        RECT 163.665 36.940 163.995 37.600 ;
        RECT 164.615 36.940 164.945 37.600 ;
        RECT 165.565 36.530 165.895 37.600 ;
        RECT 166.515 36.530 166.845 37.600 ;
        RECT 167.465 36.940 167.795 37.600 ;
        RECT 168.250 37.330 168.910 37.795 ;
        RECT 159.685 36.000 159.945 36.330 ;
        RECT 160.115 36.000 160.375 36.330 ;
        RECT 160.635 36.000 160.895 36.330 ;
        RECT 161.065 36.000 161.325 36.330 ;
        RECT 161.585 36.000 161.845 36.330 ;
        RECT 162.015 36.000 162.275 36.330 ;
        RECT 162.535 36.000 162.795 36.330 ;
        RECT 162.965 36.000 163.225 36.330 ;
        RECT 163.485 36.000 163.745 36.330 ;
        RECT 163.915 36.000 164.175 36.330 ;
        RECT 164.435 36.000 164.695 36.330 ;
        RECT 164.865 36.000 165.125 36.330 ;
        RECT 165.385 36.000 165.645 36.330 ;
        RECT 165.815 36.000 166.075 36.330 ;
        RECT 166.335 36.000 166.595 36.330 ;
        RECT 166.765 36.000 167.025 36.330 ;
        RECT 167.285 36.000 167.545 36.330 ;
        RECT 167.715 36.000 167.975 36.330 ;
        RECT 168.235 36.000 168.495 36.330 ;
        RECT 168.665 36.000 168.925 36.330 ;
        RECT 159.700 35.675 159.930 36.000 ;
        RECT 160.130 35.675 160.360 36.000 ;
        RECT 160.650 35.675 160.880 36.000 ;
        RECT 161.080 35.675 161.310 36.000 ;
        RECT 161.600 35.675 161.830 36.000 ;
        RECT 162.030 35.675 162.260 36.000 ;
        RECT 162.550 35.675 162.780 36.000 ;
        RECT 162.980 35.675 163.210 36.000 ;
        RECT 163.500 35.675 163.730 36.000 ;
        RECT 163.930 35.675 164.160 36.000 ;
        RECT 164.450 35.675 164.680 36.000 ;
        RECT 164.880 35.675 165.110 36.000 ;
        RECT 165.400 35.675 165.630 36.000 ;
        RECT 165.830 35.675 166.060 36.000 ;
        RECT 166.350 35.675 166.580 36.000 ;
        RECT 166.780 35.675 167.010 36.000 ;
        RECT 167.300 35.675 167.530 36.000 ;
        RECT 167.730 35.675 167.960 36.000 ;
        RECT 168.250 35.675 168.480 36.000 ;
        RECT 168.680 35.675 168.910 36.000 ;
        RECT 159.685 35.345 159.945 35.675 ;
        RECT 160.115 35.345 160.375 35.675 ;
        RECT 160.635 35.345 160.895 35.675 ;
        RECT 161.065 35.345 161.325 35.675 ;
        RECT 161.585 35.345 161.845 35.675 ;
        RECT 162.015 35.345 162.275 35.675 ;
        RECT 162.535 35.345 162.795 35.675 ;
        RECT 162.965 35.345 163.225 35.675 ;
        RECT 163.485 35.345 163.745 35.675 ;
        RECT 163.915 35.345 164.175 35.675 ;
        RECT 164.435 35.345 164.695 35.675 ;
        RECT 164.865 35.345 165.125 35.675 ;
        RECT 165.385 35.345 165.645 35.675 ;
        RECT 165.815 35.345 166.075 35.675 ;
        RECT 166.335 35.345 166.595 35.675 ;
        RECT 166.765 35.345 167.025 35.675 ;
        RECT 167.285 35.345 167.545 35.675 ;
        RECT 167.715 35.345 167.975 35.675 ;
        RECT 168.235 35.345 168.495 35.675 ;
        RECT 168.665 35.345 168.925 35.675 ;
        RECT 159.700 34.905 159.930 35.345 ;
        RECT 160.130 34.905 160.360 35.345 ;
        RECT 160.650 34.905 160.880 35.345 ;
        RECT 161.080 34.905 161.310 35.345 ;
        RECT 161.600 34.905 161.830 35.345 ;
        RECT 162.030 34.905 162.260 35.345 ;
        RECT 162.550 34.905 162.780 35.345 ;
        RECT 162.980 34.905 163.210 35.345 ;
        RECT 163.500 34.905 163.730 35.345 ;
        RECT 163.930 34.905 164.160 35.345 ;
        RECT 164.450 34.905 164.680 35.345 ;
        RECT 164.880 34.905 165.110 35.345 ;
        RECT 165.400 34.905 165.630 35.345 ;
        RECT 165.830 34.905 166.060 35.345 ;
        RECT 166.350 34.905 166.580 35.345 ;
        RECT 166.780 34.905 167.010 35.345 ;
        RECT 167.300 34.905 167.530 35.345 ;
        RECT 167.730 34.905 167.960 35.345 ;
        RECT 168.250 34.905 168.480 35.345 ;
        RECT 168.680 34.905 168.910 35.345 ;
        RECT 159.685 34.575 159.945 34.905 ;
        RECT 160.115 34.575 160.375 34.905 ;
        RECT 160.635 34.575 160.895 34.905 ;
        RECT 161.065 34.575 161.325 34.905 ;
        RECT 161.585 34.575 161.845 34.905 ;
        RECT 162.015 34.575 162.275 34.905 ;
        RECT 162.535 34.575 162.795 34.905 ;
        RECT 162.965 34.575 163.225 34.905 ;
        RECT 163.485 34.575 163.745 34.905 ;
        RECT 163.915 34.575 164.175 34.905 ;
        RECT 164.435 34.575 164.695 34.905 ;
        RECT 164.865 34.575 165.125 34.905 ;
        RECT 165.385 34.575 165.645 34.905 ;
        RECT 165.815 34.575 166.075 34.905 ;
        RECT 166.335 34.575 166.595 34.905 ;
        RECT 166.765 34.575 167.025 34.905 ;
        RECT 167.285 34.575 167.545 34.905 ;
        RECT 167.715 34.575 167.975 34.905 ;
        RECT 168.235 34.575 168.495 34.905 ;
        RECT 168.665 34.575 168.925 34.905 ;
        RECT 159.700 34.165 159.930 34.575 ;
        RECT 160.130 34.165 160.360 34.575 ;
        RECT 160.650 34.165 160.880 34.575 ;
        RECT 161.080 34.165 161.310 34.575 ;
        RECT 161.600 34.165 161.830 34.575 ;
        RECT 162.030 34.165 162.260 34.575 ;
        RECT 162.550 34.165 162.780 34.575 ;
        RECT 162.980 34.165 163.210 34.575 ;
        RECT 163.500 34.165 163.730 34.575 ;
        RECT 163.930 34.165 164.160 34.575 ;
        RECT 164.450 34.165 164.680 34.575 ;
        RECT 164.880 34.165 165.110 34.575 ;
        RECT 165.400 34.165 165.630 34.575 ;
        RECT 165.830 34.165 166.060 34.575 ;
        RECT 166.350 34.165 166.580 34.575 ;
        RECT 166.780 34.165 167.010 34.575 ;
        RECT 167.300 34.165 167.530 34.575 ;
        RECT 167.730 34.165 167.960 34.575 ;
        RECT 168.250 34.165 168.480 34.575 ;
        RECT 168.680 34.165 168.910 34.575 ;
        RECT 159.685 33.835 159.945 34.165 ;
        RECT 160.115 33.835 160.375 34.165 ;
        RECT 160.635 33.835 160.895 34.165 ;
        RECT 161.065 33.835 161.325 34.165 ;
        RECT 161.585 33.835 161.845 34.165 ;
        RECT 162.015 33.835 162.275 34.165 ;
        RECT 162.535 33.835 162.795 34.165 ;
        RECT 162.965 33.835 163.225 34.165 ;
        RECT 163.485 33.835 163.745 34.165 ;
        RECT 163.915 33.835 164.175 34.165 ;
        RECT 164.435 33.835 164.695 34.165 ;
        RECT 164.865 33.835 165.125 34.165 ;
        RECT 165.385 33.835 165.645 34.165 ;
        RECT 165.815 33.835 166.075 34.165 ;
        RECT 166.335 33.835 166.595 34.165 ;
        RECT 166.765 33.835 167.025 34.165 ;
        RECT 167.285 33.835 167.545 34.165 ;
        RECT 167.715 33.835 167.975 34.165 ;
        RECT 168.235 33.835 168.495 34.165 ;
        RECT 168.665 33.835 168.925 34.165 ;
        RECT 159.700 33.640 159.930 33.835 ;
        RECT 160.130 33.640 160.360 33.835 ;
        RECT 159.700 33.370 160.360 33.640 ;
        RECT 160.650 33.640 160.880 33.835 ;
        RECT 161.080 33.640 161.310 33.835 ;
        RECT 160.650 33.370 161.310 33.640 ;
        RECT 161.600 33.640 161.830 33.835 ;
        RECT 162.030 33.640 162.260 33.835 ;
        RECT 161.600 33.370 162.260 33.640 ;
        RECT 162.550 33.640 162.780 33.835 ;
        RECT 162.980 33.640 163.210 33.835 ;
        RECT 162.550 33.370 163.210 33.640 ;
        RECT 163.500 33.640 163.730 33.835 ;
        RECT 163.930 33.640 164.160 33.835 ;
        RECT 163.500 33.370 164.160 33.640 ;
        RECT 164.450 33.640 164.680 33.835 ;
        RECT 164.880 33.640 165.110 33.835 ;
        RECT 164.450 33.370 165.110 33.640 ;
        RECT 165.400 33.640 165.630 33.835 ;
        RECT 165.830 33.640 166.060 33.835 ;
        RECT 165.400 33.370 166.060 33.640 ;
        RECT 166.350 33.640 166.580 33.835 ;
        RECT 166.780 33.640 167.010 33.835 ;
        RECT 166.350 33.370 167.010 33.640 ;
        RECT 167.300 33.640 167.530 33.835 ;
        RECT 167.730 33.640 167.960 33.835 ;
        RECT 167.300 33.370 167.960 33.640 ;
        RECT 168.250 33.640 168.480 33.835 ;
        RECT 168.680 33.640 168.910 33.835 ;
        RECT 168.250 33.370 168.910 33.640 ;
        RECT 169.310 33.120 169.600 49.240 ;
        RECT 159.600 33.110 169.600 33.120 ;
        RECT 159.010 32.820 169.600 33.110 ;
        RECT 113.390 29.150 113.620 29.355 ;
        RECT 113.390 28.920 114.460 29.150 ;
        RECT 115.130 28.990 115.420 29.150 ;
        RECT 116.090 28.990 116.380 29.150 ;
        RECT 117.050 28.990 117.340 29.150 ;
        RECT 115.125 28.920 115.420 28.990 ;
        RECT 116.085 28.920 116.380 28.990 ;
        RECT 117.045 28.920 117.340 28.990 ;
        RECT 113.390 28.330 113.620 28.920 ;
        RECT 75.950 27.920 76.180 28.150 ;
        RECT 85.080 27.920 85.310 28.150 ;
        RECT 75.950 27.640 85.310 27.920 ;
        RECT 115.125 27.815 115.415 28.920 ;
        RECT 116.085 27.815 116.375 28.920 ;
        RECT 117.045 27.815 117.335 28.920 ;
        RECT 118.010 27.815 118.300 29.150 ;
        RECT 118.970 27.815 119.260 29.150 ;
        RECT 119.930 27.815 120.220 29.150 ;
        RECT 120.890 27.815 121.180 29.150 ;
        RECT 121.850 27.815 122.140 29.150 ;
        RECT 122.810 27.815 123.100 29.150 ;
        RECT 123.770 27.815 124.060 29.150 ;
        RECT 124.730 27.815 125.020 29.150 ;
        RECT 125.690 27.815 125.980 29.150 ;
        RECT 126.650 28.190 126.940 29.150 ;
        RECT 127.610 28.190 127.900 29.150 ;
        RECT 128.570 28.190 128.860 29.150 ;
        RECT 129.530 28.190 129.820 29.150 ;
        RECT 130.490 28.190 130.780 29.150 ;
        RECT 131.450 28.190 131.740 29.150 ;
        RECT 126.650 27.875 126.945 28.190 ;
        RECT 127.610 27.875 127.905 28.190 ;
        RECT 128.570 27.875 128.865 28.190 ;
        RECT 126.655 27.815 126.945 27.875 ;
        RECT 127.615 27.815 127.905 27.875 ;
        RECT 128.575 27.815 128.865 27.875 ;
        RECT 129.530 27.855 129.825 28.190 ;
        RECT 130.490 27.855 130.785 28.190 ;
        RECT 131.450 27.855 131.745 28.190 ;
        RECT 129.535 27.815 129.825 27.855 ;
        RECT 130.495 27.815 130.785 27.855 ;
        RECT 131.455 27.815 131.745 27.855 ;
        RECT 132.410 27.815 132.700 29.150 ;
        RECT 133.370 27.815 133.660 29.150 ;
        RECT 134.330 27.815 134.620 29.150 ;
        RECT 135.290 28.190 135.580 29.150 ;
        RECT 136.250 28.190 136.540 29.150 ;
        RECT 137.210 28.190 137.500 29.150 ;
        RECT 138.170 28.190 138.460 29.150 ;
        RECT 139.490 28.860 139.720 29.355 ;
        RECT 135.290 27.855 135.585 28.190 ;
        RECT 136.250 27.855 136.545 28.190 ;
        RECT 135.295 27.815 135.585 27.855 ;
        RECT 136.255 27.815 136.545 27.855 ;
        RECT 137.210 27.815 137.505 28.190 ;
        RECT 138.170 27.815 138.465 28.190 ;
        RECT 52.995 27.205 72.660 27.360 ;
        RECT 53.025 26.920 72.660 27.205 ;
        RECT 31.375 24.970 88.735 25.200 ;
        RECT 31.375 24.690 32.250 24.970 ;
        RECT 48.505 24.690 48.735 24.970 ;
        RECT 87.860 24.690 88.735 24.970 ;
        RECT 31.375 24.460 36.185 24.690 ;
        RECT 36.720 24.460 43.035 24.690 ;
        RECT 43.925 24.460 55.315 24.690 ;
        RECT 56.205 24.460 62.165 24.690 ;
        RECT 62.495 24.460 68.455 24.690 ;
        RECT 68.785 24.460 74.745 24.690 ;
        RECT 75.075 24.460 81.035 24.690 ;
        RECT 81.925 24.460 88.735 24.690 ;
        RECT 31.375 14.140 32.250 24.460 ;
        RECT 36.235 24.240 36.465 24.300 ;
        RECT 36.040 14.360 36.465 24.240 ;
        RECT 36.720 14.360 37.100 24.460 ;
        RECT 43.085 24.240 43.315 24.300 ;
        RECT 43.645 24.240 43.875 24.300 ;
        RECT 43.065 14.360 43.895 24.240 ;
        RECT 36.235 14.300 36.465 14.360 ;
        RECT 36.795 14.300 37.025 14.360 ;
        RECT 43.085 14.300 43.315 14.360 ;
        RECT 43.645 14.300 43.875 14.360 ;
        RECT 47.860 14.140 49.380 24.460 ;
        RECT 57.760 24.410 60.540 24.460 ;
        RECT 64.195 24.410 66.975 24.460 ;
        RECT 70.465 24.410 73.245 24.460 ;
        RECT 76.510 24.410 79.290 24.460 ;
        RECT 55.365 24.245 55.595 24.300 ;
        RECT 55.165 14.360 55.595 24.245 ;
        RECT 55.925 24.240 56.155 24.300 ;
        RECT 62.215 24.240 62.445 24.300 ;
        RECT 68.505 24.240 68.735 24.300 ;
        RECT 74.795 24.240 75.025 24.300 ;
        RECT 81.085 24.240 81.315 24.300 ;
        RECT 81.645 24.245 81.875 24.300 ;
        RECT 55.365 14.300 55.595 14.360 ;
        RECT 55.850 14.355 56.230 24.240 ;
        RECT 62.140 14.360 62.520 24.240 ;
        RECT 68.430 14.360 68.810 24.240 ;
        RECT 74.720 14.360 75.100 24.240 ;
        RECT 81.010 14.360 81.390 24.240 ;
        RECT 81.645 14.360 82.070 24.245 ;
        RECT 55.925 14.300 56.155 14.355 ;
        RECT 62.215 14.300 62.445 14.360 ;
        RECT 68.505 14.300 68.735 14.360 ;
        RECT 74.795 14.300 75.025 14.360 ;
        RECT 81.085 14.300 81.315 14.360 ;
        RECT 81.645 14.300 81.875 14.360 ;
        RECT 87.860 14.140 88.735 24.460 ;
        RECT 89.795 24.020 127.805 24.250 ;
        RECT 89.795 23.740 90.025 24.020 ;
        RECT 93.525 23.740 94.305 23.760 ;
        RECT 95.815 23.740 96.595 23.745 ;
        RECT 98.105 23.740 98.885 23.745 ;
        RECT 100.395 23.740 101.175 23.745 ;
        RECT 102.685 23.740 103.465 23.745 ;
        RECT 104.975 23.740 105.755 23.745 ;
        RECT 107.265 23.740 108.045 23.745 ;
        RECT 109.555 23.740 110.335 23.745 ;
        RECT 111.845 23.740 112.625 23.745 ;
        RECT 114.135 23.740 114.915 23.745 ;
        RECT 116.425 23.740 117.205 23.745 ;
        RECT 118.715 23.740 119.495 23.745 ;
        RECT 121.005 23.740 121.785 23.745 ;
        RECT 123.295 23.740 124.075 23.745 ;
        RECT 89.795 23.510 92.605 23.740 ;
        RECT 92.935 23.510 94.895 23.740 ;
        RECT 95.225 23.510 97.185 23.740 ;
        RECT 97.515 23.510 99.475 23.740 ;
        RECT 99.805 23.510 101.765 23.740 ;
        RECT 102.095 23.510 104.055 23.740 ;
        RECT 104.385 23.510 106.345 23.740 ;
        RECT 106.675 23.510 108.635 23.740 ;
        RECT 108.965 23.510 110.925 23.740 ;
        RECT 111.255 23.510 113.215 23.740 ;
        RECT 113.545 23.510 115.505 23.740 ;
        RECT 115.835 23.510 117.795 23.740 ;
        RECT 118.125 23.510 120.085 23.740 ;
        RECT 120.415 23.510 122.375 23.740 ;
        RECT 122.705 23.510 124.665 23.740 ;
        RECT 124.995 23.735 126.955 23.740 ;
        RECT 127.575 23.735 127.805 24.020 ;
        RECT 124.995 23.510 127.805 23.735 ;
        RECT 89.795 23.350 90.025 23.510 ;
        RECT 93.525 23.480 94.305 23.510 ;
        RECT 95.815 23.465 96.595 23.510 ;
        RECT 98.105 23.465 98.885 23.510 ;
        RECT 100.395 23.465 101.175 23.510 ;
        RECT 102.685 23.465 103.465 23.510 ;
        RECT 104.975 23.465 105.755 23.510 ;
        RECT 107.265 23.465 108.045 23.510 ;
        RECT 109.555 23.465 110.335 23.510 ;
        RECT 111.845 23.465 112.625 23.510 ;
        RECT 114.135 23.465 114.915 23.510 ;
        RECT 116.425 23.465 117.205 23.510 ;
        RECT 118.715 23.465 119.495 23.510 ;
        RECT 121.005 23.465 121.785 23.510 ;
        RECT 123.295 23.465 124.075 23.510 ;
        RECT 127.575 23.350 127.805 23.510 ;
        RECT 89.795 22.100 90.670 23.350 ;
        RECT 92.655 23.290 92.885 23.350 ;
        RECT 92.580 22.165 92.960 23.290 ;
        RECT 94.945 23.285 95.175 23.350 ;
        RECT 97.235 23.285 97.465 23.350 ;
        RECT 99.525 23.285 99.755 23.350 ;
        RECT 101.815 23.285 102.045 23.350 ;
        RECT 104.105 23.285 104.335 23.350 ;
        RECT 106.395 23.285 106.625 23.350 ;
        RECT 108.685 23.285 108.915 23.350 ;
        RECT 110.975 23.285 111.205 23.350 ;
        RECT 113.265 23.285 113.495 23.350 ;
        RECT 115.555 23.285 115.785 23.350 ;
        RECT 117.845 23.285 118.075 23.350 ;
        RECT 120.135 23.285 120.365 23.350 ;
        RECT 122.425 23.285 122.655 23.350 ;
        RECT 124.715 23.285 124.945 23.350 ;
        RECT 92.655 22.100 92.885 22.165 ;
        RECT 94.870 22.160 95.250 23.285 ;
        RECT 97.160 22.160 97.540 23.285 ;
        RECT 99.450 22.160 99.830 23.285 ;
        RECT 101.740 22.160 102.120 23.285 ;
        RECT 104.030 22.160 104.410 23.285 ;
        RECT 106.320 22.160 106.700 23.285 ;
        RECT 108.610 22.160 108.990 23.285 ;
        RECT 110.900 22.160 111.280 23.285 ;
        RECT 113.190 22.160 113.570 23.285 ;
        RECT 115.480 22.160 115.860 23.285 ;
        RECT 117.770 22.160 118.150 23.285 ;
        RECT 120.060 22.160 120.440 23.285 ;
        RECT 122.350 22.160 122.730 23.285 ;
        RECT 124.640 22.160 125.020 23.285 ;
        RECT 94.945 22.100 95.175 22.160 ;
        RECT 97.235 22.100 97.465 22.160 ;
        RECT 99.525 22.100 99.755 22.160 ;
        RECT 101.815 22.100 102.045 22.160 ;
        RECT 104.105 22.100 104.335 22.160 ;
        RECT 106.395 22.100 106.625 22.160 ;
        RECT 108.685 22.100 108.915 22.160 ;
        RECT 110.975 22.100 111.205 22.160 ;
        RECT 113.265 22.100 113.495 22.160 ;
        RECT 115.555 22.100 115.785 22.160 ;
        RECT 117.845 22.100 118.075 22.160 ;
        RECT 120.135 22.100 120.365 22.160 ;
        RECT 122.425 22.100 122.655 22.160 ;
        RECT 124.715 22.100 124.945 22.160 ;
        RECT 126.930 22.100 127.805 23.350 ;
        RECT 89.795 21.940 90.025 22.100 ;
        RECT 93.525 21.940 94.305 21.985 ;
        RECT 95.815 21.940 96.595 21.985 ;
        RECT 98.105 21.940 98.885 21.985 ;
        RECT 100.395 21.940 101.175 21.985 ;
        RECT 102.685 21.940 103.465 21.985 ;
        RECT 104.975 21.940 105.755 21.985 ;
        RECT 107.265 21.940 108.045 21.985 ;
        RECT 109.555 21.940 110.335 21.985 ;
        RECT 111.845 21.940 112.625 21.985 ;
        RECT 114.130 21.940 114.910 21.985 ;
        RECT 116.425 21.940 117.205 21.985 ;
        RECT 118.715 21.940 119.495 21.985 ;
        RECT 121.005 21.940 121.785 21.985 ;
        RECT 123.295 21.940 124.075 21.985 ;
        RECT 89.795 21.710 92.605 21.940 ;
        RECT 92.935 21.710 94.895 21.940 ;
        RECT 95.225 21.710 97.185 21.940 ;
        RECT 97.515 21.710 99.475 21.940 ;
        RECT 99.805 21.710 101.765 21.940 ;
        RECT 102.095 21.710 104.055 21.940 ;
        RECT 104.385 21.710 106.345 21.940 ;
        RECT 106.675 21.710 108.635 21.940 ;
        RECT 108.965 21.710 110.925 21.940 ;
        RECT 111.255 21.710 113.215 21.940 ;
        RECT 113.545 21.710 115.505 21.940 ;
        RECT 115.835 21.710 117.795 21.940 ;
        RECT 118.125 21.710 120.085 21.940 ;
        RECT 120.415 21.710 122.375 21.940 ;
        RECT 122.705 21.710 124.665 21.940 ;
        RECT 124.995 21.935 126.955 21.940 ;
        RECT 127.575 21.935 127.805 22.100 ;
        RECT 124.995 21.710 127.805 21.935 ;
        RECT 89.795 21.430 90.025 21.710 ;
        RECT 93.525 21.705 94.305 21.710 ;
        RECT 95.815 21.705 96.595 21.710 ;
        RECT 98.105 21.705 98.885 21.710 ;
        RECT 100.395 21.705 101.175 21.710 ;
        RECT 102.685 21.705 103.465 21.710 ;
        RECT 104.975 21.705 105.755 21.710 ;
        RECT 107.265 21.705 108.045 21.710 ;
        RECT 109.555 21.705 110.335 21.710 ;
        RECT 111.845 21.705 112.625 21.710 ;
        RECT 114.130 21.705 114.910 21.710 ;
        RECT 116.425 21.705 117.205 21.710 ;
        RECT 118.715 21.705 119.495 21.710 ;
        RECT 121.005 21.705 121.785 21.710 ;
        RECT 123.295 21.705 124.075 21.710 ;
        RECT 127.575 21.430 127.805 21.710 ;
        RECT 89.795 21.200 127.805 21.430 ;
        RECT 31.375 13.910 36.185 14.140 ;
        RECT 37.075 13.910 43.035 14.140 ;
        RECT 43.925 13.910 55.315 14.140 ;
        RECT 56.205 13.910 62.165 14.140 ;
        RECT 62.495 13.910 68.455 14.140 ;
        RECT 68.785 13.910 74.745 14.140 ;
        RECT 75.075 13.910 81.035 14.140 ;
        RECT 81.925 13.910 88.735 14.140 ;
        RECT 31.375 13.630 31.605 13.910 ;
        RECT 48.505 13.630 48.735 13.910 ;
        RECT 88.505 13.630 88.735 13.910 ;
        RECT 31.375 13.400 88.735 13.630 ;
      LAYER met2 ;
        RECT 31.555 74.850 65.725 75.830 ;
        RECT 31.775 73.675 32.245 74.850 ;
        RECT 35.810 73.675 36.280 74.850 ;
        RECT 42.115 73.675 42.585 74.850 ;
        RECT 48.405 73.875 48.875 74.850 ;
        RECT 48.355 73.695 48.925 73.875 ;
        RECT 54.700 73.675 55.170 74.850 ;
        RECT 60.995 73.675 61.465 74.850 ;
        RECT 64.890 73.675 65.360 74.850 ;
        RECT 67.515 74.300 79.630 74.670 ;
        RECT 67.515 73.900 67.885 74.300 ;
        RECT 68.260 73.790 83.370 74.160 ;
        RECT 89.005 73.700 103.805 74.070 ;
        RECT 92.585 73.690 103.290 73.700 ;
        RECT 29.475 73.025 49.030 73.395 ;
        RECT 72.010 73.280 72.780 73.650 ;
        RECT 74.295 73.280 75.065 73.650 ;
        RECT 76.540 73.280 77.310 73.650 ;
        RECT 78.860 73.280 79.630 73.650 ;
        RECT 113.600 73.375 115.650 73.745 ;
        RECT 104.045 73.165 109.040 73.190 ;
        RECT 29.475 72.625 29.845 73.025 ;
        RECT 31.555 72.515 65.725 72.885 ;
        RECT 66.840 72.375 67.210 72.775 ;
        RECT 30.145 72.005 67.215 72.375 ;
        RECT 30.145 71.605 30.515 72.005 ;
        RECT 31.795 70.080 32.265 71.310 ;
        RECT 35.810 70.140 36.280 71.370 ;
        RECT 42.115 70.140 42.585 71.370 ;
        RECT 48.405 70.140 48.875 71.370 ;
        RECT 54.700 70.140 55.170 71.370 ;
        RECT 60.990 70.140 61.460 71.370 ;
        RECT 64.870 70.140 65.340 71.370 ;
        RECT 31.555 69.135 65.725 69.505 ;
        RECT 66.840 68.995 67.210 69.395 ;
        RECT 30.145 68.625 67.215 68.995 ;
        RECT 68.805 68.900 69.085 73.130 ;
        RECT 71.095 68.900 71.375 73.130 ;
        RECT 73.385 68.900 73.665 73.130 ;
        RECT 75.675 68.900 75.955 73.130 ;
        RECT 77.965 68.900 78.245 73.130 ;
        RECT 80.255 68.900 80.535 73.130 ;
        RECT 82.545 68.900 82.825 73.130 ;
        RECT 92.725 70.560 93.005 73.040 ;
        RECT 94.015 70.560 94.295 73.040 ;
        RECT 95.305 70.560 95.585 73.040 ;
        RECT 96.595 70.560 96.875 73.040 ;
        RECT 97.885 70.560 98.165 73.040 ;
        RECT 99.175 70.560 99.455 73.040 ;
        RECT 100.465 70.560 100.745 73.040 ;
        RECT 101.755 70.560 102.035 73.040 ;
        RECT 103.045 70.560 103.325 73.040 ;
        RECT 104.040 72.820 109.040 73.165 ;
        RECT 111.350 72.865 115.720 73.235 ;
        RECT 104.040 72.420 104.420 72.820 ;
        RECT 104.720 72.310 111.050 72.680 ;
        RECT 111.355 72.465 111.725 72.865 ;
        RECT 104.720 70.225 106.175 72.310 ;
        RECT 106.465 70.830 106.745 71.700 ;
        RECT 107.105 70.225 107.385 72.310 ;
        RECT 107.745 70.830 108.025 71.690 ;
        RECT 108.385 70.225 108.665 72.310 ;
        RECT 109.595 72.245 111.050 72.310 ;
        RECT 112.000 72.355 117.210 72.725 ;
        RECT 112.000 72.330 113.515 72.355 ;
        RECT 112.000 72.245 112.825 72.330 ;
        RECT 109.025 70.830 109.305 71.700 ;
        RECT 109.595 70.225 112.825 72.245 ;
        RECT 104.720 70.180 112.825 70.225 ;
        RECT 113.135 70.180 113.515 72.330 ;
        RECT 113.825 70.830 114.105 71.690 ;
        RECT 114.415 70.180 114.795 72.355 ;
        RECT 115.105 70.830 115.385 71.690 ;
        RECT 115.695 70.180 116.075 72.355 ;
        RECT 116.385 70.180 117.210 72.355 ;
        RECT 104.045 70.090 104.415 70.115 ;
        RECT 92.480 69.910 103.185 69.930 ;
        RECT 89.005 69.540 103.805 69.910 ;
        RECT 104.040 69.715 104.420 70.090 ;
        RECT 104.720 69.855 117.210 70.180 ;
        RECT 112.000 69.810 117.210 69.855 ;
        RECT 96.545 69.030 99.285 69.400 ;
        RECT 104.040 69.345 109.040 69.715 ;
        RECT 111.350 69.300 115.720 69.670 ;
        RECT 111.350 69.205 111.730 69.300 ;
        RECT 104.720 68.835 111.730 69.205 ;
        RECT 30.145 68.225 30.515 68.625 ;
        RECT 30.885 68.115 61.585 68.485 ;
        RECT 72.010 68.360 72.780 68.730 ;
        RECT 74.295 68.360 75.065 68.730 ;
        RECT 76.540 68.360 77.310 68.730 ;
        RECT 78.860 68.360 79.630 68.730 ;
        RECT 93.945 68.430 104.420 68.800 ;
        RECT 104.720 68.440 105.100 68.835 ;
        RECT 111.870 68.790 115.630 69.160 ;
        RECT 116.335 68.825 139.720 69.195 ;
        RECT 111.870 68.695 112.240 68.790 ;
        RECT 104.725 68.435 105.095 68.440 ;
        RECT 30.885 67.715 31.255 68.115 ;
        RECT 67.515 67.710 67.885 68.110 ;
        RECT 68.260 67.850 83.370 68.220 ;
        RECT 104.045 68.030 104.415 68.430 ;
        RECT 106.215 68.325 109.560 68.695 ;
        RECT 110.625 68.325 112.240 68.695 ;
        RECT 107.190 68.080 107.560 68.085 ;
        RECT 110.625 68.080 110.995 68.325 ;
        RECT 107.175 67.710 110.995 68.080 ;
        RECT 31.940 66.250 32.410 67.480 ;
        RECT 35.810 66.250 36.280 67.480 ;
        RECT 42.115 66.250 42.585 67.480 ;
        RECT 48.405 66.250 48.875 67.480 ;
        RECT 54.700 66.250 55.170 67.480 ;
        RECT 61.000 66.250 61.470 67.480 ;
        RECT 64.875 66.250 65.345 67.480 ;
        RECT 67.515 67.340 83.370 67.710 ;
        RECT 67.515 66.670 89.065 67.040 ;
        RECT 67.515 66.270 67.885 66.670 ;
        RECT 68.255 66.160 92.035 66.530 ;
        RECT 93.510 66.390 103.740 67.270 ;
        RECT 105.400 67.200 111.890 67.570 ;
        RECT 30.885 65.615 31.255 66.015 ;
        RECT 72.550 65.635 73.320 66.005 ;
        RECT 74.835 65.650 75.605 66.020 ;
        RECT 77.120 65.650 77.890 66.020 ;
        RECT 79.395 65.650 80.165 66.020 ;
        RECT 81.690 65.650 82.460 66.020 ;
        RECT 84.000 65.650 84.770 66.020 ;
        RECT 30.145 65.105 30.515 65.505 ;
        RECT 30.885 65.245 61.605 65.615 ;
        RECT 66.840 65.105 67.210 65.505 ;
        RECT 30.145 64.735 67.215 65.105 ;
        RECT 31.555 64.225 65.725 64.595 ;
        RECT 31.940 62.360 32.410 63.590 ;
        RECT 35.810 62.360 36.280 63.590 ;
        RECT 42.115 62.360 42.585 63.590 ;
        RECT 48.405 62.360 48.875 63.590 ;
        RECT 54.700 62.360 55.170 63.590 ;
        RECT 60.995 62.360 61.465 63.590 ;
        RECT 64.890 62.360 65.360 63.590 ;
        RECT 30.145 61.725 30.515 62.125 ;
        RECT 66.840 61.725 67.210 62.125 ;
        RECT 30.145 61.355 67.215 61.725 ;
        RECT 68.800 61.275 69.080 65.505 ;
        RECT 70.970 61.275 71.250 65.505 ;
        RECT 71.650 61.275 71.930 65.505 ;
        RECT 73.940 61.275 74.220 65.505 ;
        RECT 76.230 61.275 76.510 65.505 ;
        RECT 78.520 61.275 78.800 65.505 ;
        RECT 80.810 61.275 81.090 65.505 ;
        RECT 83.100 61.275 83.380 65.505 ;
        RECT 85.390 61.275 85.670 65.505 ;
        RECT 86.070 61.275 86.350 65.505 ;
        RECT 88.240 61.275 88.520 65.505 ;
        RECT 92.335 65.370 100.965 66.250 ;
        RECT 105.400 65.235 106.855 67.200 ;
        RECT 103.245 65.230 106.855 65.235 ;
        RECT 93.510 64.860 106.855 65.230 ;
        RECT 93.510 62.385 94.385 64.860 ;
        RECT 95.210 63.010 95.490 64.240 ;
        RECT 95.905 63.010 96.185 64.240 ;
        RECT 97.195 63.010 97.475 64.240 ;
        RECT 98.485 63.010 98.765 64.240 ;
        RECT 99.775 63.005 100.055 64.235 ;
        RECT 101.065 63.010 101.345 64.240 ;
        RECT 101.755 63.010 102.035 64.240 ;
        RECT 102.865 62.390 103.740 64.860 ;
        RECT 105.400 62.495 106.855 64.860 ;
        RECT 107.225 63.105 107.505 66.585 ;
        RECT 107.875 63.105 108.135 67.200 ;
        RECT 108.505 63.105 108.785 66.585 ;
        RECT 109.155 62.495 109.415 67.200 ;
        RECT 109.785 63.140 110.065 66.620 ;
        RECT 110.435 62.495 111.890 67.200 ;
        RECT 112.030 67.035 139.720 68.075 ;
        RECT 112.035 66.595 112.405 67.035 ;
        RECT 112.030 66.220 112.410 66.595 ;
        RECT 112.710 66.520 138.145 66.895 ;
        RECT 112.035 65.780 112.405 66.220 ;
        RECT 112.030 65.405 112.410 65.780 ;
        RECT 112.035 64.965 112.405 65.405 ;
        RECT 112.715 64.795 113.085 66.520 ;
        RECT 113.390 66.005 139.720 66.380 ;
        RECT 140.155 66.185 146.675 66.555 ;
        RECT 113.390 65.345 114.670 66.005 ;
        RECT 105.400 62.390 111.890 62.495 ;
        RECT 102.865 62.385 111.890 62.390 ;
        RECT 93.510 62.125 111.890 62.385 ;
        RECT 93.510 62.015 106.010 62.125 ;
        RECT 29.475 60.705 29.845 61.105 ;
        RECT 31.555 60.845 65.725 61.215 ;
        RECT 72.550 60.730 73.320 61.100 ;
        RECT 74.835 60.730 75.605 61.100 ;
        RECT 77.120 60.730 77.890 61.100 ;
        RECT 79.395 60.730 80.165 61.100 ;
        RECT 81.690 60.730 82.460 61.100 ;
        RECT 84.000 60.730 84.770 61.100 ;
        RECT 92.335 60.995 103.740 61.875 ;
        RECT 104.725 61.475 105.100 61.875 ;
        RECT 107.175 61.615 110.140 61.985 ;
        RECT 29.475 60.335 61.620 60.705 ;
        RECT 31.920 58.885 32.390 60.055 ;
        RECT 35.760 59.855 36.330 59.995 ;
        RECT 35.810 58.885 36.280 59.855 ;
        RECT 42.115 58.885 42.585 60.055 ;
        RECT 48.405 58.885 48.875 60.055 ;
        RECT 54.700 58.885 55.170 60.055 ;
        RECT 60.940 59.945 61.510 60.085 ;
        RECT 67.515 60.080 67.885 60.480 ;
        RECT 68.315 60.220 92.035 60.590 ;
        RECT 60.990 58.885 61.460 59.945 ;
        RECT 64.885 58.885 65.355 60.055 ;
        RECT 67.510 59.710 84.770 60.080 ;
        RECT 93.510 59.975 103.740 60.855 ;
        RECT 104.045 60.850 104.420 61.250 ;
        RECT 104.720 61.105 110.990 61.475 ;
        RECT 104.045 60.480 110.310 60.850 ;
        RECT 110.610 60.705 110.990 61.105 ;
        RECT 109.930 60.080 110.310 60.480 ;
        RECT 71.395 59.200 83.625 59.570 ;
        RECT 31.555 57.900 65.725 58.885 ;
        RECT 67.515 58.550 67.885 58.950 ;
        RECT 71.600 58.690 85.720 59.060 ;
        RECT 113.390 58.820 114.700 65.345 ;
        RECT 115.385 58.820 115.650 66.005 ;
        RECT 116.345 58.820 116.605 66.005 ;
        RECT 117.305 58.820 117.565 66.005 ;
        RECT 118.265 58.820 118.525 66.005 ;
        RECT 119.225 58.820 119.485 66.005 ;
        RECT 120.185 58.820 120.445 66.005 ;
        RECT 121.145 58.820 121.405 66.005 ;
        RECT 122.105 58.820 122.365 66.005 ;
        RECT 123.065 58.820 123.325 66.005 ;
        RECT 124.025 58.820 124.285 66.005 ;
        RECT 124.985 58.820 125.245 66.005 ;
        RECT 125.945 58.820 126.205 66.005 ;
        RECT 126.905 58.820 127.165 66.005 ;
        RECT 127.865 58.820 128.125 66.005 ;
        RECT 128.825 58.820 129.085 66.005 ;
        RECT 66.840 58.040 67.210 58.440 ;
        RECT 67.515 58.180 74.570 58.550 ;
        RECT 97.145 58.445 111.670 58.815 ;
        RECT 113.390 58.760 114.670 58.820 ;
        RECT 129.785 58.810 130.045 66.005 ;
        RECT 130.745 58.810 131.005 66.005 ;
        RECT 131.705 58.810 131.965 66.005 ;
        RECT 132.665 58.810 132.925 66.005 ;
        RECT 133.625 58.810 133.885 66.005 ;
        RECT 134.585 58.810 134.845 66.005 ;
        RECT 135.545 58.810 135.805 66.005 ;
        RECT 136.505 58.810 136.765 66.005 ;
        RECT 137.465 58.810 137.725 66.005 ;
        RECT 138.440 65.335 139.720 66.005 ;
        RECT 146.305 65.785 146.675 66.185 ;
        RECT 141.430 65.400 145.240 65.770 ;
        RECT 138.415 58.810 139.720 65.335 ;
        RECT 149.935 65.105 151.885 65.175 ;
        RECT 153.010 65.105 154.980 65.175 ;
        RECT 156.130 65.105 158.100 65.175 ;
        RECT 160.675 65.105 162.645 65.175 ;
        RECT 165.175 65.105 167.125 65.175 ;
        RECT 142.790 65.090 143.160 65.100 ;
        RECT 144.185 65.090 144.555 65.100 ;
        RECT 147.100 65.090 147.470 65.100 ;
        RECT 148.500 65.090 148.870 65.100 ;
        RECT 142.700 64.830 144.555 65.090 ;
        RECT 146.310 65.030 149.130 65.090 ;
        RECT 149.935 65.030 167.125 65.105 ;
        RECT 146.310 64.965 167.125 65.030 ;
        RECT 142.790 64.820 143.160 64.830 ;
        RECT 144.185 64.820 144.555 64.830 ;
        RECT 144.890 64.870 145.260 64.940 ;
        RECT 146.310 64.895 151.885 64.965 ;
        RECT 153.010 64.895 154.980 64.965 ;
        RECT 156.130 64.895 158.100 64.965 ;
        RECT 160.675 64.895 162.645 64.965 ;
        RECT 165.175 64.895 167.125 64.965 ;
        RECT 146.310 64.890 150.000 64.895 ;
        RECT 144.890 64.730 145.975 64.870 ;
        RECT 146.310 64.830 149.130 64.890 ;
        RECT 147.100 64.820 147.470 64.830 ;
        RECT 148.500 64.820 148.870 64.830 ;
        RECT 163.345 64.755 164.245 64.825 ;
        RECT 144.890 64.660 145.260 64.730 ;
        RECT 144.795 64.460 145.145 64.520 ;
        RECT 145.835 64.460 145.975 64.730 ;
        RECT 159.325 64.615 164.245 64.755 ;
        RECT 146.685 64.460 147.035 64.520 ;
        RECT 144.795 64.320 147.035 64.460 ;
        RECT 159.325 64.365 159.465 64.615 ;
        RECT 163.345 64.545 164.245 64.615 ;
        RECT 144.795 64.260 145.145 64.320 ;
        RECT 146.685 64.260 147.035 64.320 ;
        RECT 154.420 64.305 155.420 64.365 ;
        RECT 158.260 64.305 160.540 64.365 ;
        RECT 163.380 64.305 164.380 64.365 ;
        RECT 154.420 64.165 164.380 64.305 ;
        RECT 154.420 64.105 155.420 64.165 ;
        RECT 158.260 64.105 160.540 64.165 ;
        RECT 163.380 64.105 164.380 64.165 ;
        RECT 146.305 64.085 146.675 64.095 ;
        RECT 145.440 64.020 145.760 64.085 ;
        RECT 146.070 64.020 146.675 64.085 ;
        RECT 145.440 63.880 146.675 64.020 ;
        RECT 145.440 63.825 145.760 63.880 ;
        RECT 146.070 63.825 146.675 63.880 ;
        RECT 146.305 63.815 146.675 63.825 ;
        RECT 155.705 63.870 156.695 63.930 ;
        RECT 156.980 63.870 157.980 63.930 ;
        RECT 158.965 63.870 159.865 63.940 ;
        RECT 160.820 63.870 161.820 63.930 ;
        RECT 162.100 63.870 163.100 63.930 ;
        RECT 155.705 63.730 163.100 63.870 ;
        RECT 155.705 63.670 156.695 63.730 ;
        RECT 156.980 63.670 157.980 63.730 ;
        RECT 158.965 63.660 159.865 63.730 ;
        RECT 160.820 63.670 161.820 63.730 ;
        RECT 162.100 63.670 163.100 63.730 ;
        RECT 142.700 62.825 149.535 63.465 ;
        RECT 149.935 62.450 167.130 63.465 ;
        RECT 142.700 61.495 149.130 62.135 ;
        RECT 154.140 61.650 164.700 62.290 ;
        RECT 142.700 59.865 149.130 60.505 ;
        RECT 149.940 60.325 167.125 61.490 ;
        RECT 155.295 59.525 164.245 60.165 ;
        RECT 149.940 59.225 167.125 59.365 ;
        RECT 66.840 57.670 76.375 58.040 ;
        RECT 74.555 57.130 74.935 57.530 ;
        RECT 75.995 57.270 76.375 57.670 ;
        RECT 81.840 57.270 89.065 58.020 ;
        RECT 92.295 57.835 104.205 58.205 ;
        RECT 111.290 58.045 111.670 58.445 ;
        RECT 108.595 57.605 108.965 58.005 ;
        RECT 112.710 57.605 113.080 57.840 ;
        RECT 98.860 57.235 113.090 57.605 ;
        RECT 39.300 56.760 90.215 57.130 ;
        RECT 112.710 57.070 113.080 57.235 ;
        RECT 31.400 56.250 57.855 56.620 ;
        RECT 89.245 56.585 90.120 56.760 ;
        RECT 91.390 56.685 110.990 57.055 ;
        RECT 60.400 56.185 75.695 56.555 ;
        RECT 34.900 55.740 57.525 56.110 ;
        RECT 58.125 55.675 72.335 56.045 ;
        RECT 75.315 55.785 75.685 56.185 ;
        RECT 90.370 56.170 107.095 56.540 ;
        RECT 110.610 56.285 110.990 56.685 ;
        RECT 90.405 56.130 106.725 56.170 ;
        RECT 105.175 55.795 105.495 55.805 ;
        RECT 31.920 53.625 32.200 55.105 ;
        RECT 34.210 53.625 34.490 55.105 ;
        RECT 36.500 53.625 36.780 55.105 ;
        RECT 38.670 53.625 39.075 55.105 ;
        RECT 39.350 53.625 39.630 55.105 ;
        RECT 41.695 53.625 42.425 55.105 ;
        RECT 44.490 53.625 44.770 55.105 ;
        RECT 46.660 53.625 47.065 55.105 ;
        RECT 47.340 53.625 47.620 55.105 ;
        RECT 49.685 53.625 50.415 55.105 ;
        RECT 52.480 53.625 52.760 55.105 ;
        RECT 54.770 53.625 55.050 55.105 ;
        RECT 57.060 53.625 57.340 55.105 ;
        RECT 58.640 53.810 58.920 55.040 ;
        RECT 59.930 53.810 60.210 55.040 ;
        RECT 61.220 53.810 61.500 55.040 ;
        RECT 62.510 53.810 62.790 55.040 ;
        RECT 63.800 53.810 64.080 55.040 ;
        RECT 65.090 53.810 65.370 55.040 ;
        RECT 66.380 53.810 66.660 55.040 ;
        RECT 67.670 53.810 67.950 55.040 ;
        RECT 68.960 53.810 69.240 55.040 ;
        RECT 70.250 53.810 70.530 55.040 ;
        RECT 71.540 53.810 71.820 55.040 ;
        RECT 78.520 53.670 78.800 55.755 ;
        RECT 91.440 53.665 91.720 55.750 ;
        RECT 98.910 53.670 99.190 55.755 ;
        RECT 102.015 53.660 105.505 55.795 ;
        RECT 102.030 53.630 102.350 53.660 ;
        RECT 105.175 53.640 105.495 53.660 ;
        RECT 52.230 52.990 53.015 52.995 ;
        RECT 34.900 52.620 57.840 52.990 ;
        RECT 58.125 52.805 72.365 53.175 ;
        RECT 75.315 52.665 75.685 53.065 ;
        RECT 31.405 52.110 57.855 52.480 ;
        RECT 60.400 52.295 75.695 52.665 ;
        RECT 114.895 52.095 115.175 58.780 ;
        RECT 115.855 52.095 116.135 58.780 ;
        RECT 116.815 52.095 117.095 58.780 ;
        RECT 117.780 52.095 118.060 58.780 ;
        RECT 118.735 52.095 119.015 58.780 ;
        RECT 119.700 52.095 119.980 58.780 ;
        RECT 120.655 52.095 120.935 58.780 ;
        RECT 121.620 52.095 121.900 58.780 ;
        RECT 122.575 52.095 122.855 58.780 ;
        RECT 123.540 52.095 123.820 58.780 ;
        RECT 124.495 52.095 124.775 58.780 ;
        RECT 125.460 52.095 125.740 58.780 ;
        RECT 126.415 52.095 126.695 58.780 ;
        RECT 127.380 52.095 127.660 58.780 ;
        RECT 128.335 52.095 128.615 58.780 ;
        RECT 129.300 52.095 129.580 58.780 ;
        RECT 130.255 52.095 130.535 58.780 ;
        RECT 131.220 52.095 131.500 58.780 ;
        RECT 132.175 52.095 132.455 58.780 ;
        RECT 133.140 52.095 133.420 58.780 ;
        RECT 134.095 52.095 134.375 58.780 ;
        RECT 135.060 52.095 135.340 58.780 ;
        RECT 136.015 52.095 136.295 58.780 ;
        RECT 136.980 52.095 137.260 58.780 ;
        RECT 137.935 52.070 138.215 58.755 ;
        RECT 142.700 58.585 167.125 59.225 ;
        RECT 149.940 58.485 167.125 58.585 ;
        RECT 155.705 58.220 157.980 58.280 ;
        RECT 158.965 58.220 159.865 58.290 ;
        RECT 160.820 58.220 161.820 58.280 ;
        RECT 162.100 58.220 163.100 58.280 ;
        RECT 155.705 58.080 163.100 58.220 ;
        RECT 155.705 58.020 157.980 58.080 ;
        RECT 158.965 58.010 159.865 58.080 ;
        RECT 160.820 58.020 161.820 58.080 ;
        RECT 162.100 58.020 163.100 58.080 ;
        RECT 142.700 57.270 149.130 57.910 ;
        RECT 154.420 57.785 155.420 57.840 ;
        RECT 158.260 57.785 160.540 57.840 ;
        RECT 163.380 57.785 164.380 57.840 ;
        RECT 154.420 57.645 164.380 57.785 ;
        RECT 154.420 57.580 155.420 57.645 ;
        RECT 158.260 57.580 160.540 57.645 ;
        RECT 163.380 57.580 164.380 57.645 ;
        RECT 149.935 57.000 151.885 57.070 ;
        RECT 153.020 57.000 154.970 57.400 ;
        RECT 156.620 57.350 156.990 57.420 ;
        RECT 158.115 57.350 158.485 57.420 ;
        RECT 159.160 57.350 159.680 57.580 ;
        RECT 163.345 57.350 164.245 57.420 ;
        RECT 156.620 57.210 167.125 57.350 ;
        RECT 156.620 57.140 156.990 57.210 ;
        RECT 158.115 57.140 158.485 57.210 ;
        RECT 163.345 57.140 164.245 57.210 ;
        RECT 161.080 57.060 162.650 57.070 ;
        RECT 161.015 57.000 162.935 57.060 ;
        RECT 165.165 57.000 167.135 57.070 ;
        RECT 149.935 56.860 167.135 57.000 ;
        RECT 146.305 56.835 146.675 56.845 ;
        RECT 145.430 56.775 145.750 56.835 ;
        RECT 146.070 56.775 146.675 56.835 ;
        RECT 149.935 56.790 151.885 56.860 ;
        RECT 161.015 56.800 162.935 56.860 ;
        RECT 161.080 56.790 162.650 56.800 ;
        RECT 165.165 56.790 167.135 56.860 ;
        RECT 145.430 56.635 146.675 56.775 ;
        RECT 145.430 56.575 145.750 56.635 ;
        RECT 146.070 56.575 146.675 56.635 ;
        RECT 146.305 56.565 146.675 56.575 ;
        RECT 153.525 56.640 153.895 56.710 ;
        RECT 158.965 56.640 159.865 56.710 ;
        RECT 153.525 56.500 159.865 56.640 ;
        RECT 153.525 56.430 153.895 56.500 ;
        RECT 158.965 56.430 159.865 56.500 ;
        RECT 144.795 56.340 145.145 56.400 ;
        RECT 146.685 56.340 147.035 56.400 ;
        RECT 144.795 56.200 147.035 56.340 ;
        RECT 149.200 56.215 149.570 56.285 ;
        RECT 151.630 56.215 152.000 56.285 ;
        RECT 163.360 56.215 163.730 56.285 ;
        RECT 144.795 56.140 145.145 56.200 ;
        RECT 144.890 55.975 145.260 56.000 ;
        RECT 145.745 55.975 145.885 56.200 ;
        RECT 146.685 56.140 147.035 56.200 ;
        RECT 147.830 56.075 163.730 56.215 ;
        RECT 149.200 56.005 149.570 56.075 ;
        RECT 151.630 56.005 152.000 56.075 ;
        RECT 163.360 56.005 163.730 56.075 ;
        RECT 142.790 55.935 143.160 55.945 ;
        RECT 144.185 55.935 144.555 55.945 ;
        RECT 142.700 55.675 144.555 55.935 ;
        RECT 144.890 55.835 145.885 55.975 ;
        RECT 147.100 55.925 147.470 55.935 ;
        RECT 148.495 55.925 148.865 55.935 ;
        RECT 146.230 55.865 148.865 55.925 ;
        RECT 144.890 55.720 145.260 55.835 ;
        RECT 146.230 55.725 151.110 55.865 ;
        RECT 166.095 55.760 166.465 55.830 ;
        RECT 142.790 55.665 143.160 55.675 ;
        RECT 144.185 55.665 144.555 55.675 ;
        RECT 146.230 55.665 148.865 55.725 ;
        RECT 147.100 55.655 147.470 55.665 ;
        RECT 148.495 55.655 148.865 55.665 ;
        RECT 151.370 55.620 167.300 55.760 ;
        RECT 147.840 55.410 148.210 55.485 ;
        RECT 150.260 55.410 150.630 55.480 ;
        RECT 151.370 55.410 151.510 55.620 ;
        RECT 166.095 55.550 166.465 55.620 ;
        RECT 143.530 55.240 143.900 55.315 ;
        RECT 144.580 55.240 144.950 55.315 ;
        RECT 143.530 55.100 144.950 55.240 ;
        RECT 147.840 55.270 151.510 55.410 ;
        RECT 152.695 55.350 153.155 55.360 ;
        RECT 154.260 55.350 154.680 55.360 ;
        RECT 155.780 55.350 156.255 55.360 ;
        RECT 157.355 55.350 157.790 55.360 ;
        RECT 159.355 55.350 159.725 55.420 ;
        RECT 160.750 55.410 161.120 55.420 ;
        RECT 162.010 55.410 162.380 55.420 ;
        RECT 160.750 55.350 163.780 55.410 ;
        RECT 147.840 55.205 148.210 55.270 ;
        RECT 150.260 55.200 150.630 55.270 ;
        RECT 143.530 55.035 143.900 55.100 ;
        RECT 144.580 55.035 144.950 55.100 ;
        RECT 152.500 55.090 157.950 55.350 ;
        RECT 159.355 55.210 163.785 55.350 ;
        RECT 166.095 55.300 166.465 55.370 ;
        RECT 159.355 55.140 159.725 55.210 ;
        RECT 160.750 55.150 163.780 55.210 ;
        RECT 164.125 55.160 166.465 55.300 ;
        RECT 167.355 55.180 167.495 55.320 ;
        RECT 160.750 55.140 161.120 55.150 ;
        RECT 162.010 55.140 162.380 55.150 ;
        RECT 152.695 55.080 153.155 55.090 ;
        RECT 154.260 55.080 154.680 55.090 ;
        RECT 155.780 55.080 156.255 55.090 ;
        RECT 157.355 55.080 157.790 55.090 ;
        RECT 162.595 54.945 162.925 54.995 ;
        RECT 164.125 54.945 164.265 55.160 ;
        RECT 166.095 55.090 166.465 55.160 ;
        RECT 165.445 54.945 165.775 54.995 ;
        RECT 162.595 54.805 165.775 54.945 ;
        RECT 162.595 54.735 162.925 54.805 ;
        RECT 165.445 54.735 165.775 54.805 ;
        RECT 142.930 54.665 144.005 54.675 ;
        RECT 145.335 54.665 146.305 54.675 ;
        RECT 147.435 54.665 148.325 54.675 ;
        RECT 149.540 54.665 149.910 54.675 ;
        RECT 150.940 54.665 151.310 54.675 ;
        RECT 142.700 54.605 151.310 54.665 ;
        RECT 159.355 54.615 159.725 54.685 ;
        RECT 160.735 54.615 161.105 54.685 ;
        RECT 142.700 54.465 151.425 54.605 ;
        RECT 159.300 54.475 161.105 54.615 ;
        RECT 163.350 54.570 163.720 54.580 ;
        RECT 142.700 54.405 151.310 54.465 ;
        RECT 159.355 54.405 159.725 54.475 ;
        RECT 160.735 54.405 161.105 54.475 ;
        RECT 142.930 54.395 144.005 54.405 ;
        RECT 145.335 54.395 146.305 54.405 ;
        RECT 147.435 54.395 148.325 54.405 ;
        RECT 149.540 54.395 149.910 54.405 ;
        RECT 150.940 54.395 151.310 54.405 ;
        RECT 153.145 54.340 153.465 54.385 ;
        RECT 152.695 54.330 153.465 54.340 ;
        RECT 152.485 54.270 153.465 54.330 ;
        RECT 153.845 54.270 154.165 54.385 ;
        RECT 155.780 54.330 156.255 54.340 ;
        RECT 157.440 54.330 157.810 54.340 ;
        RECT 155.065 54.270 155.385 54.330 ;
        RECT 155.780 54.270 156.605 54.330 ;
        RECT 156.985 54.270 157.965 54.330 ;
        RECT 162.600 54.310 162.920 54.570 ;
        RECT 163.350 54.510 163.870 54.570 ;
        RECT 164.500 54.510 164.820 54.570 ;
        RECT 163.350 54.370 164.820 54.510 ;
        RECT 163.350 54.310 163.870 54.370 ;
        RECT 164.500 54.310 164.820 54.370 ;
        RECT 165.450 54.310 165.770 54.570 ;
        RECT 163.350 54.300 163.720 54.310 ;
        RECT 152.485 54.130 157.965 54.270 ;
        RECT 152.485 54.125 153.465 54.130 ;
        RECT 153.845 54.125 154.165 54.130 ;
        RECT 152.485 54.070 153.160 54.125 ;
        RECT 155.065 54.070 155.385 54.130 ;
        RECT 155.780 54.070 156.605 54.130 ;
        RECT 156.985 54.070 157.965 54.130 ;
        RECT 152.695 54.060 153.160 54.070 ;
        RECT 155.780 54.060 156.255 54.070 ;
        RECT 157.440 54.060 157.810 54.070 ;
        RECT 158.655 54.005 159.025 54.075 ;
        RECT 163.765 54.005 164.085 54.065 ;
        RECT 164.715 54.005 165.035 54.065 ;
        RECT 153.525 53.880 153.895 53.950 ;
        RECT 154.365 53.880 154.685 53.940 ;
        RECT 144.580 53.490 144.950 53.770 ;
        RECT 153.525 53.740 154.685 53.880 ;
        RECT 158.655 53.865 166.425 54.005 ;
        RECT 158.655 53.795 159.025 53.865 ;
        RECT 163.765 53.805 164.085 53.865 ;
        RECT 164.715 53.805 165.035 53.865 ;
        RECT 167.295 53.860 167.555 55.180 ;
        RECT 153.525 53.670 153.895 53.740 ;
        RECT 154.365 53.680 154.685 53.740 ;
        RECT 167.355 53.695 167.495 53.860 ;
        RECT 142.930 53.470 144.005 53.490 ;
        RECT 145.505 53.470 146.305 53.490 ;
        RECT 142.685 53.350 144.280 53.470 ;
        RECT 145.185 53.350 146.305 53.470 ;
        RECT 142.685 53.210 146.305 53.350 ;
        RECT 146.540 53.255 148.475 53.590 ;
        RECT 148.735 53.260 149.015 53.630 ;
        RECT 149.410 53.580 151.460 53.590 ;
        RECT 152.695 53.580 153.160 53.590 ;
        RECT 155.780 53.580 156.255 53.590 ;
        RECT 157.305 53.580 157.810 53.590 ;
        RECT 149.350 53.320 151.460 53.580 ;
        RECT 152.485 53.520 153.160 53.580 ;
        RECT 155.065 53.520 155.385 53.580 ;
        RECT 155.780 53.520 156.605 53.580 ;
        RECT 156.985 53.520 157.965 53.580 ;
        RECT 152.485 53.380 157.965 53.520 ;
        RECT 152.485 53.320 154.165 53.380 ;
        RECT 155.065 53.320 155.385 53.380 ;
        RECT 155.780 53.320 156.605 53.380 ;
        RECT 156.985 53.320 157.965 53.380 ;
        RECT 162.385 53.520 162.705 53.580 ;
        RECT 165.235 53.520 165.555 53.580 ;
        RECT 168.185 53.520 168.555 53.590 ;
        RECT 162.385 53.380 168.555 53.520 ;
        RECT 162.385 53.320 162.705 53.380 ;
        RECT 165.235 53.320 165.555 53.380 ;
        RECT 149.410 53.260 151.460 53.320 ;
        RECT 152.695 53.310 154.165 53.320 ;
        RECT 155.780 53.310 156.255 53.320 ;
        RECT 157.440 53.310 157.810 53.320 ;
        RECT 168.185 53.310 168.555 53.380 ;
        RECT 153.145 53.260 154.165 53.310 ;
        RECT 149.410 53.255 151.310 53.260 ;
        RECT 155.765 53.105 156.085 53.165 ;
        RECT 156.620 53.105 156.990 53.175 ;
        RECT 155.765 52.965 156.990 53.105 ;
        RECT 155.765 52.905 156.085 52.965 ;
        RECT 156.620 52.895 156.990 52.965 ;
        RECT 159.355 53.100 159.725 53.170 ;
        RECT 160.765 53.100 161.135 53.170 ;
        RECT 162.010 53.160 162.380 53.170 ;
        RECT 161.480 53.100 162.380 53.160 ;
        RECT 164.665 53.100 165.035 53.170 ;
        RECT 166.230 53.100 166.890 53.160 ;
        RECT 159.355 52.960 167.585 53.100 ;
        RECT 159.355 52.890 159.725 52.960 ;
        RECT 160.765 52.890 161.135 52.960 ;
        RECT 161.480 52.900 162.380 52.960 ;
        RECT 162.010 52.890 162.380 52.900 ;
        RECT 164.665 52.890 165.035 52.960 ;
        RECT 166.230 52.900 166.890 52.960 ;
        RECT 160.055 52.685 160.425 52.755 ;
        RECT 162.815 52.685 163.135 52.745 ;
        RECT 160.055 52.680 163.135 52.685 ;
        RECT 165.665 52.680 165.985 52.740 ;
        RECT 160.055 52.545 165.985 52.680 ;
        RECT 142.930 52.475 144.005 52.535 ;
        RECT 145.335 52.475 146.305 52.495 ;
        RECT 147.435 52.475 148.325 52.495 ;
        RECT 149.540 52.475 149.910 52.535 ;
        RECT 150.940 52.475 151.310 52.495 ;
        RECT 160.055 52.475 160.425 52.545 ;
        RECT 162.815 52.540 165.985 52.545 ;
        RECT 162.815 52.485 163.135 52.540 ;
        RECT 165.665 52.480 165.985 52.540 ;
        RECT 142.700 52.215 151.310 52.475 ;
        RECT 152.695 52.245 153.155 52.255 ;
        RECT 154.260 52.245 154.680 52.255 ;
        RECT 155.780 52.245 156.255 52.255 ;
        RECT 157.355 52.245 157.790 52.255 ;
        RECT 152.500 51.985 157.950 52.245 ;
        RECT 160.750 52.230 161.120 52.300 ;
        RECT 162.010 52.290 162.380 52.300 ;
        RECT 161.435 52.230 162.380 52.290 ;
        RECT 166.185 52.230 166.935 52.280 ;
        RECT 167.235 52.230 167.605 52.300 ;
        RECT 160.750 52.090 167.605 52.230 ;
        RECT 160.750 52.020 161.120 52.090 ;
        RECT 161.435 52.030 162.380 52.090 ;
        RECT 162.010 52.020 162.380 52.030 ;
        RECT 166.185 52.020 166.935 52.090 ;
        RECT 167.235 52.020 167.605 52.090 ;
        RECT 152.695 51.975 153.155 51.985 ;
        RECT 154.260 51.975 154.680 51.985 ;
        RECT 155.780 51.975 156.255 51.985 ;
        RECT 157.355 51.975 157.790 51.985 ;
        RECT 39.300 51.600 74.935 51.970 ;
        RECT 143.605 51.835 143.975 51.905 ;
        RECT 149.475 51.835 149.845 51.905 ;
        RECT 163.365 51.860 163.625 51.950 ;
        RECT 164.315 51.860 164.575 51.950 ;
        RECT 169.125 51.860 169.495 51.930 ;
        RECT 161.365 51.835 161.735 51.855 ;
        RECT 143.605 51.695 161.735 51.835 ;
        RECT 143.605 51.625 143.975 51.695 ;
        RECT 149.475 51.625 149.845 51.695 ;
        RECT 45.605 51.410 49.765 51.415 ;
        RECT 44.440 51.040 49.765 51.410 ;
        RECT 74.555 51.200 74.925 51.600 ;
        RECT 105.245 51.570 112.410 51.580 ;
        RECT 161.365 51.575 161.735 51.695 ;
        RECT 163.365 51.720 169.495 51.860 ;
        RECT 163.365 51.620 163.625 51.720 ;
        RECT 164.315 51.620 164.575 51.720 ;
        RECT 169.125 51.650 169.495 51.720 ;
        RECT 76.930 50.740 77.255 50.790 ;
        RECT 31.375 49.870 77.255 50.740 ;
        RECT 31.375 49.350 72.660 49.870 ;
        RECT 76.930 49.820 77.255 49.870 ;
        RECT 105.170 49.405 112.410 51.570 ;
        RECT 148.705 51.485 149.075 51.555 ;
        RECT 152.660 51.485 153.030 51.555 ;
        RECT 148.705 51.345 153.030 51.485 ;
        RECT 162.650 51.360 163.020 51.430 ;
        RECT 148.705 51.275 149.075 51.345 ;
        RECT 152.660 51.275 153.030 51.345 ;
        RECT 159.800 51.220 163.020 51.360 ;
        RECT 145.475 51.135 145.845 51.205 ;
        RECT 151.035 51.135 151.405 51.205 ;
        RECT 159.800 51.135 159.945 51.220 ;
        RECT 162.650 51.150 163.020 51.220 ;
        RECT 163.360 51.420 163.730 51.430 ;
        RECT 163.360 51.360 163.870 51.420 ;
        RECT 164.500 51.360 164.820 51.420 ;
        RECT 163.360 51.220 164.820 51.360 ;
        RECT 163.360 51.160 163.870 51.220 ;
        RECT 164.500 51.160 164.820 51.220 ;
        RECT 163.360 51.150 163.730 51.160 ;
        RECT 145.475 50.995 159.945 51.135 ;
        RECT 145.475 50.925 145.845 50.995 ;
        RECT 151.035 50.925 151.405 50.995 ;
        RECT 162.595 50.925 162.925 50.975 ;
        RECT 165.445 50.925 165.775 50.975 ;
        RECT 162.595 50.785 165.775 50.925 ;
        RECT 162.595 50.715 162.925 50.785 ;
        RECT 142.850 50.575 143.300 50.585 ;
        RECT 146.650 50.575 147.020 50.585 ;
        RECT 31.835 47.445 32.205 49.350 ;
        RECT 34.695 47.445 35.065 49.350 ;
        RECT 36.985 47.445 37.355 49.350 ;
        RECT 39.275 47.445 39.645 49.350 ;
        RECT 41.565 47.445 41.935 49.350 ;
        RECT 43.860 47.445 44.230 49.350 ;
        RECT 46.695 47.430 47.065 49.350 ;
        RECT 53.500 47.605 53.870 49.350 ;
        RECT 55.790 47.610 56.160 49.350 ;
        RECT 58.080 47.610 58.450 49.350 ;
        RECT 60.370 47.610 60.740 49.350 ;
        RECT 62.660 47.610 63.030 49.350 ;
        RECT 64.950 47.610 65.320 49.350 ;
        RECT 67.240 47.610 67.610 49.350 ;
        RECT 69.530 47.610 69.900 49.350 ;
        RECT 71.820 47.610 72.190 49.350 ;
        RECT 105.355 48.680 106.865 49.090 ;
        RECT 49.395 47.100 49.765 47.500 ;
        RECT 32.605 46.730 49.765 47.100 ;
        RECT 52.285 47.105 52.655 47.505 ;
        RECT 53.450 47.465 53.920 47.605 ;
        RECT 55.740 47.470 56.210 47.610 ;
        RECT 58.030 47.470 58.500 47.610 ;
        RECT 60.320 47.470 60.790 47.610 ;
        RECT 62.610 47.470 63.080 47.610 ;
        RECT 64.900 47.470 65.370 47.610 ;
        RECT 67.190 47.470 67.660 47.610 ;
        RECT 69.480 47.470 69.950 47.610 ;
        RECT 71.770 47.470 72.240 47.610 ;
        RECT 90.400 47.550 100.280 47.940 ;
        RECT 73.800 47.105 74.170 47.505 ;
        RECT 52.285 46.735 74.180 47.105 ;
        RECT 76.930 46.595 77.255 46.645 ;
        RECT 50.435 46.590 77.255 46.595 ;
        RECT 30.615 46.080 30.985 46.480 ;
        RECT 31.375 46.225 77.255 46.590 ;
        RECT 31.375 46.220 50.435 46.225 ;
        RECT 30.615 45.710 49.025 46.080 ;
        RECT 50.065 45.820 50.435 46.220 ;
        RECT 76.930 46.175 77.255 46.225 ;
        RECT 48.655 45.680 49.025 45.710 ;
        RECT 51.545 45.715 73.420 46.085 ;
        RECT 48.655 45.310 51.175 45.680 ;
        RECT 51.545 45.315 51.915 45.715 ;
        RECT 73.040 45.315 73.410 45.715 ;
        RECT 31.840 42.725 32.210 45.100 ;
        RECT 34.695 42.700 35.065 45.075 ;
        RECT 36.985 42.700 37.355 45.075 ;
        RECT 39.275 42.700 39.645 45.075 ;
        RECT 41.565 42.700 41.935 45.075 ;
        RECT 43.860 42.700 44.230 45.075 ;
        RECT 46.690 42.680 47.060 45.055 ;
        RECT 50.805 44.910 51.175 45.310 ;
        RECT 53.495 42.580 53.865 45.180 ;
        RECT 55.795 42.580 56.165 45.180 ;
        RECT 58.075 42.580 58.445 45.180 ;
        RECT 60.370 42.580 60.740 45.180 ;
        RECT 62.650 42.580 63.020 45.180 ;
        RECT 64.950 42.580 65.320 45.180 ;
        RECT 67.235 42.580 67.605 45.180 ;
        RECT 69.530 42.580 69.900 45.180 ;
        RECT 71.815 42.580 72.185 45.180 ;
        RECT 81.840 42.925 82.120 45.010 ;
        RECT 88.300 42.925 88.580 45.010 ;
        RECT 30.615 41.540 30.985 41.940 ;
        RECT 32.325 41.680 49.765 42.050 ;
        RECT 30.615 41.170 49.025 41.540 ;
        RECT 49.395 41.280 49.765 41.680 ;
        RECT 50.805 41.680 72.660 42.050 ;
        RECT 48.655 41.140 49.025 41.170 ;
        RECT 50.805 41.140 51.175 41.680 ;
        RECT 73.040 41.540 73.410 41.940 ;
        RECT 74.560 41.790 74.930 42.190 ;
        RECT 76.975 42.135 90.125 42.515 ;
        RECT 32.325 40.660 48.285 41.030 ;
        RECT 48.655 40.770 51.175 41.140 ;
        RECT 51.545 41.170 73.420 41.540 ;
        RECT 74.555 41.420 90.120 41.790 ;
        RECT 51.545 40.770 51.915 41.170 ;
        RECT 47.915 40.260 48.285 40.660 ;
        RECT 52.285 40.660 72.660 41.030 ;
        RECT 52.285 40.260 52.655 40.660 ;
        RECT 73.800 40.280 74.170 40.680 ;
        RECT 74.555 40.600 74.935 41.420 ;
        RECT 75.995 40.790 76.365 41.190 ;
        RECT 75.995 40.420 81.635 40.790 ;
        RECT 115.375 40.540 115.655 50.520 ;
        RECT 116.335 40.540 116.615 50.520 ;
        RECT 117.295 40.540 117.575 50.520 ;
        RECT 118.255 40.540 118.535 50.520 ;
        RECT 119.215 40.540 119.495 50.520 ;
        RECT 120.175 40.540 120.455 50.520 ;
        RECT 121.135 40.540 121.415 50.520 ;
        RECT 122.095 40.540 122.375 50.520 ;
        RECT 123.055 40.540 123.335 50.520 ;
        RECT 124.015 40.540 124.295 50.520 ;
        RECT 124.975 40.540 125.255 50.520 ;
        RECT 125.935 40.540 126.215 50.520 ;
        RECT 126.895 40.540 127.175 50.520 ;
        RECT 127.855 40.540 128.135 50.520 ;
        RECT 128.815 40.540 129.095 50.520 ;
        RECT 129.775 40.540 130.055 50.520 ;
        RECT 130.735 40.540 131.015 50.520 ;
        RECT 131.695 40.540 131.975 50.520 ;
        RECT 132.655 40.540 132.935 50.520 ;
        RECT 133.615 40.540 133.895 50.520 ;
        RECT 134.575 40.540 134.855 50.520 ;
        RECT 135.535 40.540 135.815 50.520 ;
        RECT 136.495 40.540 136.775 50.520 ;
        RECT 137.455 40.540 137.735 50.520 ;
        RECT 142.850 50.315 147.175 50.575 ;
        RECT 161.365 50.545 161.735 50.615 ;
        RECT 164.125 50.545 164.265 50.785 ;
        RECT 165.445 50.715 165.775 50.785 ;
        RECT 166.080 50.545 166.450 50.615 ;
        RECT 161.365 50.405 166.450 50.545 ;
        RECT 142.850 50.305 143.300 50.315 ;
        RECT 144.285 50.295 145.225 50.315 ;
        RECT 146.650 50.305 147.020 50.315 ;
        RECT 148.625 50.295 149.115 50.365 ;
        RECT 150.215 50.295 150.705 50.365 ;
        RECT 151.805 50.295 152.295 50.365 ;
        RECT 153.395 50.295 153.885 50.365 ;
        RECT 161.365 50.335 161.735 50.405 ;
        RECT 166.080 50.335 166.450 50.405 ;
        RECT 148.625 50.155 153.925 50.295 ;
        RECT 157.555 50.175 157.925 50.245 ;
        RECT 159.010 50.175 161.180 50.235 ;
        RECT 162.990 50.175 165.870 50.235 ;
        RECT 166.660 50.175 168.010 50.235 ;
        RECT 168.825 50.175 169.600 50.235 ;
        RECT 143.635 50.035 144.005 50.045 ;
        RECT 143.630 49.775 144.005 50.035 ;
        RECT 145.950 49.775 146.320 50.055 ;
        RECT 143.635 49.765 144.005 49.775 ;
        RECT 147.965 49.740 148.335 50.095 ;
        RECT 148.625 50.085 149.115 50.155 ;
        RECT 150.215 50.085 150.705 50.155 ;
        RECT 151.805 50.085 152.295 50.155 ;
        RECT 153.395 50.085 153.885 50.155 ;
        RECT 149.480 49.945 149.850 50.015 ;
        RECT 149.480 49.805 151.320 49.945 ;
        RECT 149.480 49.735 149.850 49.805 ;
        RECT 150.130 49.535 150.480 49.595 ;
        RECT 151.180 49.535 151.320 49.805 ;
        RECT 152.020 49.535 152.370 49.595 ;
        RECT 142.685 49.140 148.335 49.460 ;
        RECT 150.130 49.395 152.370 49.535 ;
        RECT 150.130 49.335 150.480 49.395 ;
        RECT 152.020 49.335 152.370 49.395 ;
        RECT 151.075 49.145 151.445 49.155 ;
        RECT 150.780 48.885 151.725 49.145 ;
        RECT 154.205 48.900 154.580 50.095 ;
        RECT 157.555 50.035 169.600 50.175 ;
        RECT 157.555 49.965 157.925 50.035 ;
        RECT 159.010 49.975 161.180 50.035 ;
        RECT 162.990 49.975 165.870 50.035 ;
        RECT 166.660 49.975 168.010 50.035 ;
        RECT 168.825 49.975 169.600 50.035 ;
        RECT 161.705 49.805 162.605 49.875 ;
        RECT 168.185 49.805 168.555 49.855 ;
        RECT 161.705 49.665 168.600 49.805 ;
        RECT 161.705 49.595 162.605 49.665 ;
        RECT 168.185 49.575 168.555 49.665 ;
        RECT 166.000 49.435 166.900 49.505 ;
        RECT 169.125 49.435 169.495 49.505 ;
        RECT 166.000 49.295 169.495 49.435 ;
        RECT 166.000 49.225 166.900 49.295 ;
        RECT 169.125 49.225 169.495 49.295 ;
        RECT 157.570 48.985 157.940 48.995 ;
        RECT 159.010 48.985 161.200 48.995 ;
        RECT 163.240 48.985 165.430 48.995 ;
        RECT 151.075 48.875 151.445 48.885 ;
        RECT 143.605 48.835 143.975 48.845 ;
        RECT 143.605 48.575 143.980 48.835 ;
        RECT 143.605 48.565 143.975 48.575 ;
        RECT 145.935 48.570 146.305 48.850 ;
        RECT 142.850 48.285 143.305 48.305 ;
        RECT 146.650 48.295 147.020 48.315 ;
        RECT 144.285 48.285 147.020 48.295 ;
        RECT 142.850 48.035 147.020 48.285 ;
        RECT 148.010 48.250 149.115 48.730 ;
        RECT 150.460 48.630 150.780 48.710 ;
        RECT 151.660 48.630 152.040 48.690 ;
        RECT 152.660 48.630 153.030 48.700 ;
        RECT 150.460 48.490 153.030 48.630 ;
        RECT 150.460 48.450 150.780 48.490 ;
        RECT 151.660 48.445 152.040 48.490 ;
        RECT 151.720 48.430 152.040 48.445 ;
        RECT 152.660 48.420 153.030 48.490 ;
        RECT 149.480 48.255 149.850 48.395 ;
        RECT 151.090 48.255 151.410 48.305 ;
        RECT 149.480 48.115 152.130 48.255 ;
        RECT 153.400 48.250 154.580 48.730 ;
        RECT 157.570 48.725 169.615 48.985 ;
        RECT 157.570 48.715 157.940 48.725 ;
        RECT 159.010 48.715 161.200 48.725 ;
        RECT 163.240 48.715 165.430 48.725 ;
        RECT 157.570 48.520 159.540 48.525 ;
        RECT 157.570 48.185 169.600 48.520 ;
        RECT 151.090 48.045 151.410 48.115 ;
        RECT 142.850 48.025 145.260 48.035 ;
        RECT 144.285 48.015 145.225 48.025 ;
        RECT 144.440 47.480 145.380 47.490 ;
        RECT 142.820 47.220 146.975 47.480 ;
        RECT 142.820 47.200 143.340 47.220 ;
        RECT 144.440 47.210 145.380 47.220 ;
        RECT 146.605 47.200 146.975 47.220 ;
        RECT 143.700 46.665 144.070 46.945 ;
        RECT 144.845 46.625 145.215 47.010 ;
        RECT 145.795 46.665 146.165 46.945 ;
        RECT 142.825 45.845 147.005 46.485 ;
        RECT 148.010 46.285 148.290 47.970 ;
        RECT 149.830 47.890 150.150 47.930 ;
        RECT 152.350 47.890 152.670 47.930 ;
        RECT 149.830 47.750 152.670 47.890 ;
        RECT 149.830 47.670 150.150 47.750 ;
        RECT 151.150 47.505 151.290 47.750 ;
        RECT 152.350 47.670 152.670 47.750 ;
        RECT 151.035 47.495 151.405 47.505 ;
        RECT 150.780 47.430 151.725 47.495 ;
        RECT 150.105 47.290 152.565 47.430 ;
        RECT 150.780 47.235 151.725 47.290 ;
        RECT 151.035 47.225 151.405 47.235 ;
        RECT 150.130 46.985 150.480 47.045 ;
        RECT 152.020 46.985 152.370 47.090 ;
        RECT 150.130 46.845 152.370 46.985 ;
        RECT 150.130 46.785 150.480 46.845 ;
        RECT 149.480 46.645 149.850 46.715 ;
        RECT 151.180 46.645 151.320 46.845 ;
        RECT 152.020 46.830 152.370 46.845 ;
        RECT 148.625 46.285 149.115 46.590 ;
        RECT 149.480 46.505 151.320 46.645 ;
        RECT 149.480 46.435 149.850 46.505 ;
        RECT 151.805 46.285 152.295 46.590 ;
        RECT 153.395 46.285 153.885 46.590 ;
        RECT 154.205 46.285 154.580 48.080 ;
        RECT 157.570 47.865 159.565 47.870 ;
        RECT 157.570 47.530 169.600 47.865 ;
        RECT 157.570 47.095 159.540 47.100 ;
        RECT 157.570 46.760 169.600 47.095 ;
        RECT 157.570 46.355 159.540 46.360 ;
        RECT 157.570 46.020 169.600 46.355 ;
        RECT 148.115 45.925 148.835 45.955 ;
        RECT 153.210 45.925 153.930 45.960 ;
        RECT 155.670 45.925 156.390 45.995 ;
        RECT 148.115 45.785 156.390 45.925 ;
        RECT 144.845 45.225 145.215 45.705 ;
        RECT 148.115 45.675 148.835 45.785 ;
        RECT 153.210 45.680 153.930 45.785 ;
        RECT 155.670 45.715 156.390 45.785 ;
        RECT 156.835 45.715 157.205 45.785 ;
        RECT 161.765 45.715 162.095 45.775 ;
        RECT 162.715 45.715 163.045 45.775 ;
        RECT 165.565 45.715 165.895 45.775 ;
        RECT 166.515 45.715 166.845 45.775 ;
        RECT 156.835 45.575 166.845 45.715 ;
        RECT 151.035 45.485 151.405 45.555 ;
        RECT 154.450 45.485 154.820 45.555 ;
        RECT 156.835 45.505 157.205 45.575 ;
        RECT 161.765 45.515 162.095 45.575 ;
        RECT 162.715 45.515 163.045 45.575 ;
        RECT 165.565 45.515 165.895 45.575 ;
        RECT 166.515 45.515 166.845 45.575 ;
        RECT 151.035 45.345 154.820 45.485 ;
        RECT 151.035 45.275 151.405 45.345 ;
        RECT 154.450 45.275 154.820 45.345 ;
        RECT 158.230 45.290 158.600 45.360 ;
        RECT 160.815 45.290 161.145 45.350 ;
        RECT 163.665 45.290 163.995 45.350 ;
        RECT 164.615 45.290 164.945 45.350 ;
        RECT 167.465 45.290 167.795 45.350 ;
        RECT 158.230 45.150 167.795 45.290 ;
        RECT 142.825 45.045 146.935 45.085 ;
        RECT 148.115 45.045 148.835 45.115 ;
        RECT 153.240 45.045 153.920 45.115 ;
        RECT 155.675 45.045 156.390 45.115 ;
        RECT 158.230 45.080 158.600 45.150 ;
        RECT 160.815 45.090 161.145 45.150 ;
        RECT 163.665 45.090 163.995 45.150 ;
        RECT 164.615 45.090 164.945 45.150 ;
        RECT 167.465 45.090 167.795 45.150 ;
        RECT 142.825 44.905 156.390 45.045 ;
        RECT 142.825 44.445 146.935 44.905 ;
        RECT 148.115 44.835 148.835 44.905 ;
        RECT 153.240 44.835 153.920 44.905 ;
        RECT 155.675 44.835 156.390 44.905 ;
        RECT 149.480 44.605 149.850 44.675 ;
        RECT 150.535 44.605 150.905 44.675 ;
        RECT 149.480 44.465 150.905 44.605 ;
        RECT 149.480 44.395 149.850 44.465 ;
        RECT 150.535 44.395 150.905 44.465 ;
        RECT 144.845 43.750 145.215 44.305 ;
        RECT 148.115 44.165 148.835 44.235 ;
        RECT 153.215 44.165 153.930 44.235 ;
        RECT 155.675 44.165 156.390 44.235 ;
        RECT 157.570 44.225 169.600 44.560 ;
        RECT 157.570 44.220 159.545 44.225 ;
        RECT 148.115 44.025 156.390 44.165 ;
        RECT 148.115 43.955 148.835 44.025 ;
        RECT 153.215 43.955 153.930 44.025 ;
        RECT 155.675 43.955 156.390 44.025 ;
        RECT 142.825 43.285 146.980 43.610 ;
        RECT 159.550 43.570 169.065 43.905 ;
        RECT 148.115 43.345 148.835 43.355 ;
        RECT 149.400 43.345 150.115 43.355 ;
        RECT 151.270 43.345 151.985 43.355 ;
        RECT 153.215 43.345 153.930 43.355 ;
        RECT 155.675 43.345 156.385 43.355 ;
        RECT 148.115 43.285 156.555 43.345 ;
        RECT 142.825 43.145 156.555 43.285 ;
        RECT 142.825 42.970 146.980 43.145 ;
        RECT 148.115 43.085 156.555 43.145 ;
        RECT 148.115 43.075 148.835 43.085 ;
        RECT 149.400 43.075 150.115 43.085 ;
        RECT 151.270 43.075 151.985 43.085 ;
        RECT 153.215 43.075 153.930 43.085 ;
        RECT 155.675 43.075 156.385 43.085 ;
        RECT 144.845 42.265 145.215 42.830 ;
        RECT 159.540 42.800 169.065 43.135 ;
        RECT 148.115 42.375 148.835 42.445 ;
        RECT 149.400 42.435 150.115 42.445 ;
        RECT 149.280 42.375 150.115 42.435 ;
        RECT 152.370 42.375 152.690 42.425 ;
        RECT 155.675 42.405 156.390 42.415 ;
        RECT 155.675 42.400 157.720 42.405 ;
        RECT 155.675 42.395 159.540 42.400 ;
        RECT 155.445 42.375 169.600 42.395 ;
        RECT 148.115 42.235 169.600 42.375 ;
        RECT 148.115 42.165 148.835 42.235 ;
        RECT 149.280 42.175 150.115 42.235 ;
        RECT 149.400 42.165 150.115 42.175 ;
        RECT 152.370 42.165 152.690 42.235 ;
        RECT 155.445 42.145 169.600 42.235 ;
        RECT 155.445 42.135 156.390 42.145 ;
        RECT 142.825 41.485 146.980 42.125 ;
        RECT 150.535 42.090 150.905 42.095 ;
        RECT 150.535 42.085 151.080 42.090 ;
        RECT 150.535 41.825 151.400 42.085 ;
        RECT 153.640 42.025 153.960 42.085 ;
        RECT 154.450 42.025 154.820 42.095 ;
        RECT 157.460 42.060 169.600 42.145 ;
        RECT 153.640 41.885 154.820 42.025 ;
        RECT 153.640 41.825 153.960 41.885 ;
        RECT 150.535 41.815 151.080 41.825 ;
        RECT 154.450 41.815 154.820 41.885 ;
        RECT 158.230 41.805 158.600 41.875 ;
        RECT 160.820 41.805 161.140 41.865 ;
        RECT 158.230 41.665 161.140 41.805 ;
        RECT 158.230 41.595 158.600 41.665 ;
        RECT 160.820 41.605 161.140 41.665 ;
        RECT 162.720 41.605 163.040 41.865 ;
        RECT 164.620 41.605 164.940 41.865 ;
        RECT 166.520 41.605 166.840 41.865 ;
        RECT 143.700 41.030 144.070 41.310 ;
        RECT 144.845 40.920 145.215 41.345 ;
        RECT 145.795 41.030 146.165 41.310 ;
        RECT 160.910 41.240 161.050 41.605 ;
        RECT 162.810 41.240 162.950 41.605 ;
        RECT 164.710 41.240 164.850 41.605 ;
        RECT 166.610 41.240 166.750 41.605 ;
        RECT 148.115 41.145 148.835 41.155 ;
        RECT 149.400 41.145 150.115 41.155 ;
        RECT 151.270 41.145 151.985 41.155 ;
        RECT 153.215 41.145 153.930 41.155 ;
        RECT 148.115 41.085 155.520 41.145 ;
        RECT 155.675 41.085 156.390 41.155 ;
        RECT 160.910 41.100 162.000 41.240 ;
        RECT 162.810 41.100 163.900 41.240 ;
        RECT 164.710 41.100 165.800 41.240 ;
        RECT 166.610 41.100 167.700 41.240 ;
        RECT 148.115 40.945 156.550 41.085 ;
        RECT 148.115 40.885 155.520 40.945 ;
        RECT 148.115 40.875 148.835 40.885 ;
        RECT 149.400 40.875 150.115 40.885 ;
        RECT 151.270 40.875 151.985 40.885 ;
        RECT 153.215 40.875 153.930 40.885 ;
        RECT 155.675 40.875 156.390 40.945 ;
        RECT 142.820 40.750 143.340 40.770 ;
        RECT 146.605 40.750 146.975 40.770 ;
        RECT 142.820 40.490 146.975 40.750 ;
        RECT 156.835 40.685 157.205 40.755 ;
        RECT 161.860 40.745 162.000 41.100 ;
        RECT 163.760 40.745 163.900 41.100 ;
        RECT 165.660 40.745 165.800 41.100 ;
        RECT 167.560 40.745 167.700 41.100 ;
        RECT 160.820 40.685 161.140 40.745 ;
        RECT 156.835 40.545 161.140 40.685 ;
        RECT 156.835 40.475 157.205 40.545 ;
        RECT 160.820 40.485 161.140 40.545 ;
        RECT 161.770 40.485 162.090 40.745 ;
        RECT 163.670 40.485 163.990 40.745 ;
        RECT 165.570 40.485 165.890 40.745 ;
        RECT 167.470 40.485 167.790 40.745 ;
        RECT 157.570 40.290 159.545 40.295 ;
        RECT 31.830 37.680 32.200 40.055 ;
        RECT 34.695 37.640 35.065 40.015 ;
        RECT 36.985 37.645 37.355 40.020 ;
        RECT 39.275 37.645 39.645 40.020 ;
        RECT 41.565 37.645 41.935 40.020 ;
        RECT 43.860 37.645 44.230 40.020 ;
        RECT 46.695 37.645 47.065 40.020 ;
        RECT 53.490 37.530 53.860 40.130 ;
        RECT 55.800 37.530 56.170 40.130 ;
        RECT 58.075 37.530 58.445 40.130 ;
        RECT 60.355 37.690 60.740 40.130 ;
        RECT 62.645 37.690 63.030 40.130 ;
        RECT 64.935 37.690 65.320 40.130 ;
        RECT 67.220 37.690 67.605 40.130 ;
        RECT 60.370 37.530 60.740 37.690 ;
        RECT 62.660 37.530 63.030 37.690 ;
        RECT 64.950 37.530 65.320 37.690 ;
        RECT 67.235 37.530 67.605 37.690 ;
        RECT 69.530 37.530 69.900 40.130 ;
        RECT 71.815 39.770 72.185 40.130 ;
        RECT 73.800 39.910 79.160 40.280 ;
        RECT 157.570 39.955 169.600 40.290 ;
        RECT 71.815 39.400 83.665 39.770 ;
        RECT 71.815 37.530 72.185 39.400 ;
        RECT 159.545 39.300 169.035 39.635 ;
        RECT 75.315 38.890 80.830 39.260 ;
        RECT 81.130 39.250 83.665 39.260 ;
        RECT 81.130 38.890 87.845 39.250 ;
        RECT 75.325 38.490 75.695 38.890 ;
        RECT 81.220 38.880 87.845 38.890 ;
        RECT 159.545 38.530 169.035 38.865 ;
        RECT 76.075 38.235 78.170 38.280 ;
        RECT 76.075 38.230 78.190 38.235 ;
        RECT 75.985 37.915 78.190 38.230 ;
        RECT 75.985 37.910 78.170 37.915 ;
        RECT 76.075 37.875 78.170 37.910 ;
        RECT 76.845 37.835 78.170 37.875 ;
        RECT 78.440 37.820 78.720 38.300 ;
        RECT 79.730 37.820 80.010 38.300 ;
        RECT 81.020 37.820 81.300 38.300 ;
        RECT 81.575 37.870 83.665 38.315 ;
        RECT 159.010 38.125 159.885 38.130 ;
        RECT 157.570 37.790 169.600 38.125 ;
        RECT 157.570 37.785 159.670 37.790 ;
        RECT 47.915 37.000 48.285 37.400 ;
        RECT 30.615 36.490 30.985 36.890 ;
        RECT 32.720 36.630 48.285 37.000 ;
        RECT 52.285 37.000 52.655 37.400 ;
        RECT 73.805 37.000 74.180 37.400 ;
        RECT 48.655 36.520 51.175 36.890 ;
        RECT 48.655 36.490 49.025 36.520 ;
        RECT 30.615 36.120 49.025 36.490 ;
        RECT 49.395 35.980 49.765 36.380 ;
        RECT 32.720 35.610 49.765 35.980 ;
        RECT 50.805 35.980 51.175 36.520 ;
        RECT 51.545 36.490 51.915 36.890 ;
        RECT 52.285 36.630 74.180 37.000 ;
        RECT 75.315 37.235 75.685 37.635 ;
        RECT 75.315 37.230 76.260 37.235 ;
        RECT 75.315 36.865 80.830 37.230 ;
        RECT 76.075 36.860 80.830 36.865 ;
        RECT 80.970 36.860 87.845 37.230 ;
        RECT 156.835 37.140 157.205 37.210 ;
        RECT 160.815 37.140 161.145 37.200 ;
        RECT 163.665 37.140 163.995 37.200 ;
        RECT 164.615 37.140 164.945 37.200 ;
        RECT 167.465 37.140 167.795 37.200 ;
        RECT 156.835 37.000 167.795 37.140 ;
        RECT 156.835 36.930 157.205 37.000 ;
        RECT 160.815 36.940 161.145 37.000 ;
        RECT 163.665 36.940 163.995 37.000 ;
        RECT 164.615 36.940 164.945 37.000 ;
        RECT 167.465 36.940 167.795 37.000 ;
        RECT 158.230 36.730 158.600 36.800 ;
        RECT 161.765 36.730 162.095 36.790 ;
        RECT 162.715 36.730 163.045 36.790 ;
        RECT 165.565 36.730 165.895 36.790 ;
        RECT 166.515 36.730 166.845 36.790 ;
        RECT 51.545 36.120 73.420 36.490 ;
        RECT 50.805 35.610 70.135 35.980 ;
        RECT 73.040 35.720 73.410 36.120 ;
        RECT 75.315 36.050 75.685 36.450 ;
        RECT 76.075 36.350 83.665 36.720 ;
        RECT 158.230 36.590 166.845 36.730 ;
        RECT 158.230 36.520 158.600 36.590 ;
        RECT 161.765 36.530 162.095 36.590 ;
        RECT 162.715 36.530 163.045 36.590 ;
        RECT 165.565 36.530 165.895 36.590 ;
        RECT 166.515 36.530 166.845 36.590 ;
        RECT 75.315 35.680 82.175 36.050 ;
        RECT 159.010 35.995 169.600 36.330 ;
        RECT 31.825 32.695 32.195 35.070 ;
        RECT 34.695 32.575 35.065 34.950 ;
        RECT 36.985 32.575 37.355 34.950 ;
        RECT 39.275 32.575 39.645 34.950 ;
        RECT 41.565 32.575 41.935 34.950 ;
        RECT 43.860 32.575 44.230 34.950 ;
        RECT 46.700 32.600 47.070 34.975 ;
        RECT 50.805 32.350 51.175 32.750 ;
        RECT 53.480 32.585 53.865 35.025 ;
        RECT 55.790 32.585 56.175 35.025 ;
        RECT 58.070 32.580 58.455 35.020 ;
        RECT 60.365 32.580 60.750 35.020 ;
        RECT 62.650 32.580 63.035 35.020 ;
        RECT 64.940 32.580 65.325 35.020 ;
        RECT 67.225 32.580 67.610 35.020 ;
        RECT 69.520 32.580 69.905 35.020 ;
        RECT 71.815 32.480 72.185 35.080 ;
        RECT 74.555 34.940 90.120 35.310 ;
        RECT 74.555 34.540 74.925 34.940 ;
        RECT 75.980 34.430 87.845 34.800 ;
        RECT 75.980 32.610 78.065 33.840 ;
        RECT 79.075 32.610 79.355 33.840 ;
        RECT 80.365 32.610 80.645 33.840 ;
        RECT 81.655 32.610 81.935 33.840 ;
        RECT 82.945 32.610 85.030 33.840 ;
        RECT 30.615 31.950 30.985 32.350 ;
        RECT 48.655 31.980 51.175 32.350 ;
        RECT 48.655 31.950 49.025 31.980 ;
        RECT 30.615 31.580 49.025 31.950 ;
        RECT 51.545 31.950 51.915 32.350 ;
        RECT 73.040 31.980 73.415 32.350 ;
        RECT 73.040 31.950 73.410 31.980 ;
        RECT 50.065 31.440 50.435 31.840 ;
        RECT 51.545 31.580 73.410 31.950 ;
        RECT 74.560 31.510 74.930 31.910 ;
        RECT 75.980 31.650 87.845 32.020 ;
        RECT 31.375 31.405 72.660 31.440 ;
        RECT 31.370 31.085 72.660 31.405 ;
        RECT 31.375 31.070 72.660 31.085 ;
        RECT 33.370 30.560 49.765 30.930 ;
        RECT 31.835 28.310 32.205 30.290 ;
        RECT 34.695 28.310 35.065 30.235 ;
        RECT 36.985 28.310 37.355 30.235 ;
        RECT 39.275 28.310 39.645 30.235 ;
        RECT 41.565 28.310 41.935 30.235 ;
        RECT 43.860 28.310 44.230 30.235 ;
        RECT 46.705 28.310 47.075 30.260 ;
        RECT 49.395 30.160 49.765 30.560 ;
        RECT 50.805 30.560 72.660 30.930 ;
        RECT 74.555 30.630 90.120 31.510 ;
        RECT 50.805 30.160 51.175 30.560 ;
        RECT 74.560 30.230 74.930 30.630 ;
        RECT 53.390 30.060 53.960 30.205 ;
        RECT 53.440 28.310 53.910 30.060 ;
        RECT 55.735 30.040 56.205 30.205 ;
        RECT 58.025 30.040 58.495 30.205 ;
        RECT 60.320 30.040 60.790 30.205 ;
        RECT 62.605 30.040 63.075 30.205 ;
        RECT 64.900 30.040 65.370 30.205 ;
        RECT 67.190 30.040 67.650 30.205 ;
        RECT 69.480 30.040 69.950 30.205 ;
        RECT 71.765 30.040 72.235 30.205 ;
        RECT 75.980 30.120 87.845 30.490 ;
        RECT 55.785 28.310 56.155 30.040 ;
        RECT 58.075 28.310 58.445 30.040 ;
        RECT 60.370 28.310 60.740 30.040 ;
        RECT 62.655 28.310 63.025 30.040 ;
        RECT 64.950 28.310 65.320 30.040 ;
        RECT 67.235 28.310 67.605 30.040 ;
        RECT 69.530 28.310 69.900 30.040 ;
        RECT 71.815 28.310 72.185 30.040 ;
        RECT 76.060 28.550 78.945 29.530 ;
        RECT 79.345 28.550 79.625 29.530 ;
        RECT 81.690 28.550 82.420 29.530 ;
        RECT 84.540 28.550 85.170 29.530 ;
        RECT 31.375 26.920 72.660 28.310 ;
        RECT 112.715 28.190 113.085 29.425 ;
        RECT 113.390 28.705 114.670 35.890 ;
        RECT 115.385 28.705 115.645 35.890 ;
        RECT 116.345 28.705 116.605 35.890 ;
        RECT 117.305 28.705 117.565 35.890 ;
        RECT 118.265 28.705 118.525 35.890 ;
        RECT 119.225 28.705 119.485 35.890 ;
        RECT 120.185 28.705 120.445 35.890 ;
        RECT 121.145 28.705 121.405 35.890 ;
        RECT 122.105 28.705 122.365 35.890 ;
        RECT 123.065 28.705 123.325 35.890 ;
        RECT 124.025 28.705 124.285 35.890 ;
        RECT 124.985 28.705 125.245 35.890 ;
        RECT 125.945 28.705 126.205 35.890 ;
        RECT 126.905 28.705 127.165 35.890 ;
        RECT 127.865 28.705 128.125 35.890 ;
        RECT 128.825 28.705 129.085 35.890 ;
        RECT 129.785 28.705 130.045 35.890 ;
        RECT 130.745 28.705 131.005 35.890 ;
        RECT 131.705 28.705 131.965 35.890 ;
        RECT 132.665 28.705 132.925 35.890 ;
        RECT 133.625 28.705 133.885 35.890 ;
        RECT 134.585 28.705 134.845 35.890 ;
        RECT 135.545 28.705 135.805 35.890 ;
        RECT 136.505 28.705 136.765 35.890 ;
        RECT 137.465 28.705 137.725 35.890 ;
        RECT 138.440 28.705 139.720 35.890 ;
        RECT 159.010 35.340 169.600 35.675 ;
        RECT 159.010 34.570 169.600 34.905 ;
        RECT 159.010 33.830 169.600 34.165 ;
        RECT 159.010 32.870 169.600 33.205 ;
        RECT 159.600 32.860 169.310 32.870 ;
        RECT 113.390 28.330 139.720 28.705 ;
        RECT 76.145 27.960 84.990 27.970 ;
        RECT 74.555 27.450 74.925 27.850 ;
        RECT 75.980 27.590 85.280 27.960 ;
        RECT 112.710 27.815 138.495 28.190 ;
        RECT 74.555 27.080 90.120 27.450 ;
        RECT 29.935 26.270 30.305 26.670 ;
        RECT 61.555 26.410 88.945 26.780 ;
        RECT 29.250 25.760 29.620 26.160 ;
        RECT 29.935 25.900 88.735 26.270 ;
        RECT 103.840 25.960 113.775 26.330 ;
        RECT 29.250 25.390 89.495 25.760 ;
        RECT 94.675 25.450 122.935 25.820 ;
        RECT 31.375 24.880 88.735 25.250 ;
        RECT 89.115 24.990 89.485 25.390 ;
        RECT 38.650 24.370 41.420 24.740 ;
        RECT 57.765 24.370 60.535 24.740 ;
        RECT 64.200 24.370 66.970 24.740 ;
        RECT 70.470 24.370 73.240 24.740 ;
        RECT 76.515 24.370 79.285 24.740 ;
        RECT 90.970 24.465 124.065 25.310 ;
        RECT 57.810 24.360 60.490 24.370 ;
        RECT 64.245 24.360 66.925 24.370 ;
        RECT 70.515 24.360 73.195 24.370 ;
        RECT 76.560 24.360 79.240 24.370 ;
        RECT 31.920 14.310 32.200 24.290 ;
        RECT 36.090 14.310 36.370 24.290 ;
        RECT 36.770 14.310 37.050 24.290 ;
        RECT 43.115 14.310 43.845 24.290 ;
        RECT 47.910 14.310 48.190 24.290 ;
        RECT 49.050 14.310 49.330 24.290 ;
        RECT 55.215 14.310 55.495 24.295 ;
        RECT 55.900 14.305 56.180 24.290 ;
        RECT 62.190 14.310 62.470 24.290 ;
        RECT 68.480 14.310 68.760 24.290 ;
        RECT 74.770 14.310 75.050 24.290 ;
        RECT 81.060 14.310 81.340 24.290 ;
        RECT 81.740 14.310 82.020 24.295 ;
        RECT 87.910 23.955 127.805 24.325 ;
        RECT 87.910 21.500 88.190 23.955 ;
        RECT 93.575 23.805 94.255 23.810 ;
        RECT 93.530 23.435 94.300 23.805 ;
        RECT 95.865 23.790 96.545 23.795 ;
        RECT 98.155 23.790 98.835 23.795 ;
        RECT 100.445 23.790 101.125 23.795 ;
        RECT 102.735 23.790 103.415 23.795 ;
        RECT 105.025 23.790 105.705 23.795 ;
        RECT 107.315 23.790 107.995 23.795 ;
        RECT 109.605 23.790 110.285 23.795 ;
        RECT 111.895 23.790 112.575 23.795 ;
        RECT 114.185 23.790 114.865 23.795 ;
        RECT 116.475 23.790 117.155 23.795 ;
        RECT 118.765 23.790 119.445 23.795 ;
        RECT 121.055 23.790 121.735 23.795 ;
        RECT 123.345 23.790 124.025 23.795 ;
        RECT 93.575 23.430 94.255 23.435 ;
        RECT 95.820 23.420 96.590 23.790 ;
        RECT 98.110 23.420 98.880 23.790 ;
        RECT 100.400 23.420 101.170 23.790 ;
        RECT 102.690 23.420 103.460 23.790 ;
        RECT 104.980 23.420 105.750 23.790 ;
        RECT 107.270 23.420 108.040 23.790 ;
        RECT 109.560 23.420 110.330 23.790 ;
        RECT 111.850 23.420 112.620 23.790 ;
        RECT 114.140 23.420 114.910 23.790 ;
        RECT 116.430 23.420 117.200 23.790 ;
        RECT 118.720 23.420 119.490 23.790 ;
        RECT 121.010 23.420 121.780 23.790 ;
        RECT 123.300 23.420 124.070 23.790 ;
        RECT 95.865 23.415 96.545 23.420 ;
        RECT 98.155 23.415 98.835 23.420 ;
        RECT 100.445 23.415 101.125 23.420 ;
        RECT 102.735 23.415 103.415 23.420 ;
        RECT 105.025 23.415 105.705 23.420 ;
        RECT 107.315 23.415 107.995 23.420 ;
        RECT 109.605 23.415 110.285 23.420 ;
        RECT 111.895 23.415 112.575 23.420 ;
        RECT 114.185 23.415 114.865 23.420 ;
        RECT 116.475 23.415 117.155 23.420 ;
        RECT 118.765 23.415 119.445 23.420 ;
        RECT 121.055 23.415 121.735 23.420 ;
        RECT 123.345 23.415 124.025 23.420 ;
        RECT 90.340 22.110 90.620 23.335 ;
        RECT 92.630 22.115 92.910 23.340 ;
        RECT 94.920 22.110 95.200 23.335 ;
        RECT 97.210 22.110 97.490 23.335 ;
        RECT 99.500 22.110 99.780 23.335 ;
        RECT 101.790 22.110 102.070 23.335 ;
        RECT 104.080 22.110 104.360 23.335 ;
        RECT 106.370 22.110 106.650 23.335 ;
        RECT 108.660 22.110 108.940 23.335 ;
        RECT 110.950 22.110 111.230 23.335 ;
        RECT 113.240 22.110 113.520 23.335 ;
        RECT 115.530 22.110 115.810 23.335 ;
        RECT 117.820 22.110 118.100 23.335 ;
        RECT 120.110 22.110 120.390 23.335 ;
        RECT 122.400 22.110 122.680 23.335 ;
        RECT 124.690 22.110 124.970 23.335 ;
        RECT 126.980 22.110 127.260 23.335 ;
        RECT 93.575 22.030 94.255 22.035 ;
        RECT 95.865 22.030 96.545 22.035 ;
        RECT 98.155 22.030 98.835 22.035 ;
        RECT 100.445 22.030 101.125 22.035 ;
        RECT 102.735 22.030 103.415 22.035 ;
        RECT 105.025 22.030 105.705 22.035 ;
        RECT 107.315 22.030 107.995 22.035 ;
        RECT 109.605 22.030 110.285 22.035 ;
        RECT 111.895 22.030 112.575 22.035 ;
        RECT 114.180 22.030 114.860 22.035 ;
        RECT 116.475 22.030 117.155 22.035 ;
        RECT 118.765 22.030 119.445 22.035 ;
        RECT 121.055 22.030 121.735 22.035 ;
        RECT 123.345 22.030 124.025 22.035 ;
        RECT 93.530 21.660 94.300 22.030 ;
        RECT 95.820 21.660 96.590 22.030 ;
        RECT 98.110 21.660 98.880 22.030 ;
        RECT 100.400 21.660 101.170 22.030 ;
        RECT 102.690 21.660 103.460 22.030 ;
        RECT 104.980 21.660 105.750 22.030 ;
        RECT 107.270 21.660 108.040 22.030 ;
        RECT 109.560 21.660 110.330 22.030 ;
        RECT 111.850 21.660 112.620 22.030 ;
        RECT 114.135 21.660 114.905 22.030 ;
        RECT 116.430 21.660 117.200 22.030 ;
        RECT 118.720 21.660 119.490 22.030 ;
        RECT 121.010 21.660 121.780 22.030 ;
        RECT 123.300 21.660 124.070 22.030 ;
        RECT 93.575 21.655 94.255 21.660 ;
        RECT 95.865 21.655 96.545 21.660 ;
        RECT 98.155 21.655 98.835 21.660 ;
        RECT 100.445 21.655 101.125 21.660 ;
        RECT 102.735 21.655 103.415 21.660 ;
        RECT 105.025 21.655 105.705 21.660 ;
        RECT 107.315 21.655 107.995 21.660 ;
        RECT 109.605 21.655 110.285 21.660 ;
        RECT 111.895 21.655 112.575 21.660 ;
        RECT 114.180 21.655 114.860 21.660 ;
        RECT 116.475 21.655 117.155 21.660 ;
        RECT 118.765 21.655 119.445 21.660 ;
        RECT 121.055 21.655 121.735 21.660 ;
        RECT 123.345 21.655 124.025 21.660 ;
        RECT 87.910 21.130 127.805 21.500 ;
        RECT 87.910 14.310 88.190 21.130 ;
        RECT 90.970 20.145 124.065 20.990 ;
        RECT 38.650 13.820 41.420 14.190 ;
        RECT 57.765 13.820 60.535 14.190 ;
        RECT 64.200 13.820 66.970 14.190 ;
        RECT 70.470 13.820 73.240 14.190 ;
        RECT 76.515 13.820 79.285 14.190 ;
        RECT 29.255 13.170 29.625 13.570 ;
        RECT 31.375 13.310 88.735 13.680 ;
        RECT 89.115 13.170 89.485 13.570 ;
        RECT 29.255 12.800 89.495 13.170 ;
      LAYER met3 ;
        RECT 126.945 212.520 181.165 214.525 ;
        RECT 29.475 58.575 29.845 73.395 ;
        RECT 29.255 58.205 29.845 58.575 ;
        RECT 29.255 26.160 29.635 58.205 ;
        RECT 30.145 57.905 30.515 72.375 ;
        RECT 29.250 25.390 29.635 26.160 ;
        RECT 29.935 57.535 30.515 57.905 ;
        RECT 29.935 25.900 30.315 57.535 ;
        RECT 30.885 57.250 31.255 68.485 ;
        RECT 30.615 56.880 31.255 57.250 ;
        RECT 30.615 31.580 30.995 56.880 ;
        RECT 31.555 56.620 32.465 75.830 ;
        RECT 33.680 57.900 34.590 75.830 ;
        RECT 35.760 73.675 36.330 75.830 ;
        RECT 42.065 72.885 42.635 75.830 ;
        RECT 48.355 73.695 48.925 75.830 ;
        RECT 48.260 73.025 49.030 73.395 ;
        RECT 41.965 72.515 42.735 72.885 ;
        RECT 35.655 72.005 36.425 72.375 ;
        RECT 35.760 70.140 36.330 72.005 ;
        RECT 42.065 69.505 42.635 72.515 ;
        RECT 48.355 70.140 48.925 73.025 ;
        RECT 54.650 72.885 55.220 75.830 ;
        RECT 60.945 73.675 61.515 75.830 ;
        RECT 54.555 72.515 55.325 72.885 ;
        RECT 54.650 69.505 55.220 72.515 ;
        RECT 60.840 72.005 61.610 72.375 ;
        RECT 60.945 71.345 61.515 72.005 ;
        RECT 60.940 70.165 61.515 71.345 ;
        RECT 60.945 70.140 61.515 70.165 ;
        RECT 41.970 69.135 42.740 69.505 ;
        RECT 54.550 69.135 55.320 69.505 ;
        RECT 35.650 68.115 36.420 68.485 ;
        RECT 35.760 65.615 36.330 68.115 ;
        RECT 35.655 65.245 36.425 65.615 ;
        RECT 42.065 64.595 42.635 69.135 ;
        RECT 48.255 68.115 49.025 68.485 ;
        RECT 48.355 65.615 48.925 68.115 ;
        RECT 48.230 65.245 49.000 65.615 ;
        RECT 54.650 64.595 55.220 69.135 ;
        RECT 60.815 68.115 61.585 68.485 ;
        RECT 60.945 67.455 61.515 68.115 ;
        RECT 60.945 66.275 61.520 67.455 ;
        RECT 60.945 65.615 61.515 66.275 ;
        RECT 60.835 65.245 61.605 65.615 ;
        RECT 41.960 64.225 42.730 64.595 ;
        RECT 54.550 64.225 55.320 64.595 ;
        RECT 35.760 60.705 36.330 63.590 ;
        RECT 42.065 61.215 42.635 64.225 ;
        RECT 48.355 61.725 48.925 63.590 ;
        RECT 48.265 61.355 49.035 61.725 ;
        RECT 54.650 61.215 55.220 64.225 ;
        RECT 41.940 60.845 42.710 61.215 ;
        RECT 54.525 60.845 55.295 61.215 ;
        RECT 35.660 60.335 36.430 60.705 ;
        RECT 35.760 57.900 36.330 59.995 ;
        RECT 34.160 56.620 34.540 57.900 ;
        RECT 38.620 56.620 39.000 58.885 ;
        RECT 31.405 56.465 32.465 56.620 ;
        RECT 31.405 52.110 32.250 56.465 ;
        RECT 33.965 56.250 34.735 56.620 ;
        RECT 38.220 56.250 39.000 56.620 ;
        RECT 34.160 52.480 34.540 56.250 ;
        RECT 36.245 55.740 37.015 56.110 ;
        RECT 36.450 52.990 36.830 55.740 ;
        RECT 36.240 52.620 37.025 52.990 ;
        RECT 38.620 52.480 39.000 56.250 ;
        RECT 33.970 52.110 34.755 52.480 ;
        RECT 38.215 52.110 39.000 52.480 ;
        RECT 39.300 56.760 40.070 57.130 ;
        RECT 39.300 51.970 39.680 56.760 ;
        RECT 42.065 56.620 42.635 60.845 ;
        RECT 48.355 57.900 48.925 60.055 ;
        RECT 54.650 57.900 55.220 60.845 ;
        RECT 60.945 60.705 61.515 63.590 ;
        RECT 60.850 60.335 61.620 60.705 ;
        RECT 60.940 59.960 61.510 60.005 ;
        RECT 60.940 59.135 61.515 59.960 ;
        RECT 60.940 57.900 61.510 59.135 ;
        RECT 62.730 57.900 63.640 75.830 ;
        RECT 64.815 72.885 65.670 75.830 ;
        RECT 64.815 72.515 65.725 72.885 ;
        RECT 64.815 57.900 65.670 72.515 ;
        RECT 47.290 56.760 48.060 57.130 ;
        RECT 41.645 56.250 42.635 56.620 ;
        RECT 46.210 56.250 46.990 56.620 ;
        RECT 41.645 52.110 42.475 56.250 ;
        RECT 44.230 55.740 45.015 56.110 ;
        RECT 44.440 52.990 44.820 55.740 ;
        RECT 44.235 52.620 45.020 52.990 ;
        RECT 39.300 51.600 40.085 51.970 ;
        RECT 44.440 51.410 44.820 52.620 ;
        RECT 46.610 52.480 46.990 56.250 ;
        RECT 46.205 52.110 46.990 52.480 ;
        RECT 47.290 51.970 47.670 56.760 ;
        RECT 54.720 56.620 55.100 57.900 ;
        RECT 66.840 57.850 67.215 72.775 ;
        RECT 67.515 58.180 67.885 74.670 ;
        RECT 68.260 73.790 69.330 74.160 ;
        RECT 70.840 73.790 71.610 74.160 ;
        RECT 68.260 68.220 69.135 73.790 ;
        RECT 71.045 68.220 71.425 73.790 ;
        RECT 72.010 73.265 72.780 74.670 ;
        RECT 73.130 74.300 73.900 74.670 ;
        RECT 68.260 67.850 69.330 68.220 ;
        RECT 70.845 67.850 71.615 68.220 ;
        RECT 72.010 67.340 72.780 68.730 ;
        RECT 73.335 67.710 73.715 74.300 ;
        RECT 74.295 73.265 75.065 74.670 ;
        RECT 75.430 73.790 76.200 74.160 ;
        RECT 73.145 67.340 73.915 67.710 ;
        RECT 74.295 67.340 75.065 68.730 ;
        RECT 75.625 68.220 76.005 73.790 ;
        RECT 76.540 73.265 77.310 74.670 ;
        RECT 77.705 74.300 78.475 74.670 ;
        RECT 75.430 67.850 76.200 68.220 ;
        RECT 76.540 67.340 77.310 68.730 ;
        RECT 77.915 67.710 78.295 74.300 ;
        RECT 78.860 73.265 79.630 74.670 ;
        RECT 80.015 73.790 80.785 74.160 ;
        RECT 82.295 73.790 83.370 74.160 ;
        RECT 77.725 67.340 78.495 67.710 ;
        RECT 78.860 67.340 79.630 68.730 ;
        RECT 80.205 68.220 80.585 73.790 ;
        RECT 80.010 67.850 80.780 68.220 ;
        RECT 82.495 67.850 83.370 73.790 ;
        RECT 89.005 69.240 89.880 76.010 ;
        RECT 92.115 69.540 93.055 74.070 ;
        RECT 89.005 68.660 92.035 69.240 ;
        RECT 93.965 68.800 94.345 73.015 ;
        RECT 95.255 69.540 95.635 74.070 ;
        RECT 96.545 69.400 96.925 73.040 ;
        RECT 97.835 69.540 98.215 74.070 ;
        RECT 99.125 69.400 99.505 73.040 ;
        RECT 100.415 69.540 100.795 74.070 ;
        RECT 96.545 69.030 97.315 69.400 ;
        RECT 98.515 69.030 99.505 69.400 ;
        RECT 68.255 66.160 69.325 66.530 ;
        RECT 70.530 66.160 71.300 66.530 ;
        RECT 68.255 60.220 69.130 66.160 ;
        RECT 70.920 60.590 71.300 66.160 ;
        RECT 72.550 65.635 73.320 67.040 ;
        RECT 74.835 65.635 75.605 67.040 ;
        RECT 77.120 65.635 77.890 67.040 ;
        RECT 79.395 65.635 80.165 67.040 ;
        RECT 81.690 65.635 82.460 67.040 ;
        RECT 84.000 65.635 84.770 67.040 ;
        RECT 86.020 66.160 86.790 66.530 ;
        RECT 70.530 60.220 71.300 60.590 ;
        RECT 71.600 59.060 71.980 65.505 ;
        RECT 72.550 59.710 73.320 61.100 ;
        RECT 73.890 59.570 74.270 65.505 ;
        RECT 74.835 59.710 75.605 61.100 ;
        RECT 73.690 59.200 74.460 59.570 ;
        RECT 76.180 59.060 76.560 65.505 ;
        RECT 77.120 59.690 77.890 61.100 ;
        RECT 78.470 59.570 78.850 65.505 ;
        RECT 79.395 59.710 80.165 61.100 ;
        RECT 78.280 59.200 79.050 59.570 ;
        RECT 71.600 58.690 73.420 59.060 ;
        RECT 75.990 58.690 76.760 59.060 ;
        RECT 66.840 57.670 67.210 57.850 ;
        RECT 49.635 52.110 50.465 56.620 ;
        RECT 54.515 56.250 55.300 56.620 ;
        RECT 52.215 55.740 53.000 56.110 ;
        RECT 52.430 52.995 52.810 55.740 ;
        RECT 52.230 52.625 53.015 52.995 ;
        RECT 52.430 52.620 52.810 52.625 ;
        RECT 54.720 52.480 55.100 56.250 ;
        RECT 54.515 52.110 55.300 52.480 ;
        RECT 57.010 52.110 57.855 56.620 ;
        RECT 58.195 55.675 58.980 56.045 ;
        RECT 59.675 55.675 60.460 56.045 ;
        RECT 60.965 55.675 61.750 56.045 ;
        RECT 62.265 55.675 63.050 56.045 ;
        RECT 63.550 55.675 64.335 56.045 ;
        RECT 64.835 55.675 65.620 56.045 ;
        RECT 66.130 55.675 66.915 56.045 ;
        RECT 67.415 55.675 68.200 56.045 ;
        RECT 68.715 55.675 69.500 56.045 ;
        RECT 69.995 55.675 70.780 56.045 ;
        RECT 71.480 55.675 72.265 56.045 ;
        RECT 58.210 53.175 58.970 55.675 ;
        RECT 59.880 53.175 60.260 55.675 ;
        RECT 61.170 53.175 61.550 55.675 ;
        RECT 62.460 53.175 62.840 55.675 ;
        RECT 63.750 53.175 64.130 55.675 ;
        RECT 65.040 53.175 65.420 55.675 ;
        RECT 66.330 53.175 66.710 55.675 ;
        RECT 67.620 53.175 68.000 55.675 ;
        RECT 68.910 53.175 69.290 55.675 ;
        RECT 70.200 53.175 70.580 55.675 ;
        RECT 71.490 53.175 72.250 55.675 ;
        RECT 58.200 52.805 58.985 53.175 ;
        RECT 59.690 52.805 60.475 53.175 ;
        RECT 60.990 52.805 61.775 53.175 ;
        RECT 62.280 52.805 63.065 53.175 ;
        RECT 63.540 52.805 64.325 53.175 ;
        RECT 64.840 52.805 65.625 53.175 ;
        RECT 66.120 52.805 66.905 53.175 ;
        RECT 67.410 52.805 68.195 53.175 ;
        RECT 68.715 52.805 69.500 53.175 ;
        RECT 69.995 52.805 70.780 53.175 ;
        RECT 71.480 52.805 72.265 53.175 ;
        RECT 47.290 51.600 48.285 51.970 ;
        RECT 44.440 51.040 45.225 51.410 ;
        RECT 31.375 45.075 32.255 50.740 ;
        RECT 31.375 42.750 32.260 45.075 ;
        RECT 31.375 25.970 32.255 42.750 ;
        RECT 32.975 26.920 33.865 50.740 ;
        RECT 34.695 49.795 35.065 49.935 ;
        RECT 36.985 49.795 37.355 49.905 ;
        RECT 39.275 49.795 39.645 49.915 ;
        RECT 41.565 49.795 41.935 49.870 ;
        RECT 43.860 49.795 44.230 50.005 ;
        RECT 34.645 47.470 35.115 49.795 ;
        RECT 36.935 47.470 37.405 49.795 ;
        RECT 39.225 47.470 39.695 49.795 ;
        RECT 41.515 47.470 41.985 49.795 ;
        RECT 43.810 47.470 44.280 49.795 ;
        RECT 36.985 46.590 37.355 47.470 ;
        RECT 39.065 46.730 39.835 47.100 ;
        RECT 36.785 46.220 37.555 46.590 ;
        RECT 34.485 45.710 35.255 46.080 ;
        RECT 34.695 45.050 35.065 45.710 ;
        RECT 36.985 45.050 37.355 46.220 ;
        RECT 39.275 45.050 39.645 46.730 ;
        RECT 41.565 46.590 41.935 47.470 ;
        RECT 41.370 46.220 42.140 46.590 ;
        RECT 41.565 45.050 41.935 46.220 ;
        RECT 43.660 45.710 44.430 46.080 ;
        RECT 43.860 45.050 44.230 45.710 ;
        RECT 34.645 42.725 35.115 45.050 ;
        RECT 36.935 42.725 37.405 45.050 ;
        RECT 39.225 42.725 39.695 45.050 ;
        RECT 41.515 42.725 41.985 45.050 ;
        RECT 43.810 42.725 44.280 45.050 ;
        RECT 34.490 41.680 35.260 42.050 ;
        RECT 34.695 39.990 35.065 41.680 ;
        RECT 36.985 39.995 37.355 42.725 ;
        RECT 39.060 40.660 39.830 41.030 ;
        RECT 39.275 39.995 39.645 40.660 ;
        RECT 41.565 39.995 41.935 42.725 ;
        RECT 43.655 41.680 44.425 42.050 ;
        RECT 43.860 39.995 44.230 41.680 ;
        RECT 34.645 37.665 35.115 39.990 ;
        RECT 36.935 37.670 37.405 39.995 ;
        RECT 39.225 37.670 39.695 39.995 ;
        RECT 41.515 37.670 41.985 39.995 ;
        RECT 43.810 37.670 44.280 39.995 ;
        RECT 34.695 35.980 35.065 37.665 ;
        RECT 34.485 35.610 35.255 35.980 ;
        RECT 36.985 34.925 37.355 37.670 ;
        RECT 39.275 37.000 39.645 37.670 ;
        RECT 39.070 36.630 39.840 37.000 ;
        RECT 41.565 34.925 41.935 37.670 ;
        RECT 43.860 35.980 44.230 37.670 ;
        RECT 43.650 35.610 44.420 35.980 ;
        RECT 34.645 32.600 35.115 34.925 ;
        RECT 36.935 32.600 37.405 34.925 ;
        RECT 39.225 32.600 39.695 34.925 ;
        RECT 41.515 32.600 41.985 34.925 ;
        RECT 43.810 32.600 44.280 34.925 ;
        RECT 34.695 31.950 35.065 32.600 ;
        RECT 34.495 31.580 35.265 31.950 ;
        RECT 34.695 31.575 35.065 31.580 ;
        RECT 36.985 31.440 37.355 32.600 ;
        RECT 36.780 31.070 37.550 31.440 ;
        RECT 36.985 30.210 37.355 31.070 ;
        RECT 39.275 30.930 39.645 32.600 ;
        RECT 41.565 31.440 41.935 32.600 ;
        RECT 43.860 31.950 44.230 32.600 ;
        RECT 43.650 31.580 44.420 31.950 ;
        RECT 41.365 31.070 42.135 31.440 ;
        RECT 39.075 30.560 39.845 30.930 ;
        RECT 41.565 30.210 41.935 31.070 ;
        RECT 43.860 30.210 44.230 30.235 ;
        RECT 34.645 27.885 35.115 30.210 ;
        RECT 36.935 27.885 37.405 30.210 ;
        RECT 39.225 27.885 39.695 30.210 ;
        RECT 41.515 27.885 41.985 30.210 ;
        RECT 43.810 27.885 44.280 30.210 ;
        RECT 29.255 12.800 29.635 25.390 ;
        RECT 31.375 13.310 32.300 25.970 ;
        RECT 34.695 25.250 35.065 27.885 ;
        RECT 36.985 26.920 37.355 27.885 ;
        RECT 39.275 26.920 39.645 27.885 ;
        RECT 41.565 26.920 41.935 27.885 ;
        RECT 43.860 27.475 44.230 27.885 ;
        RECT 43.275 26.920 44.230 27.475 ;
        RECT 36.720 25.390 37.890 25.760 ;
        RECT 33.650 24.880 36.420 25.250 ;
        RECT 36.035 24.755 36.420 24.880 ;
        RECT 36.040 13.680 36.420 24.755 ;
        RECT 33.650 13.310 36.420 13.680 ;
        RECT 36.720 13.170 37.100 25.390 ;
        RECT 38.650 24.370 41.420 25.760 ;
        RECT 43.275 25.250 43.745 26.920 ;
        RECT 44.755 25.250 45.645 50.740 ;
        RECT 46.655 49.780 47.545 50.740 ;
        RECT 46.645 47.455 47.545 49.780 ;
        RECT 46.655 45.030 47.545 47.455 ;
        RECT 46.640 42.705 47.545 45.030 ;
        RECT 46.655 39.995 47.545 42.705 ;
        RECT 46.645 37.670 47.545 39.995 ;
        RECT 46.655 34.950 47.545 37.670 ;
        RECT 47.915 36.630 48.285 51.600 ;
        RECT 49.395 51.410 49.765 51.415 ;
        RECT 48.980 51.040 49.765 51.410 ;
        RECT 46.650 32.625 47.545 34.950 ;
        RECT 46.655 26.920 47.545 32.625 ;
        RECT 48.655 31.580 49.025 46.080 ;
        RECT 49.395 30.160 49.765 51.040 ;
        RECT 50.065 31.070 50.435 46.590 ;
        RECT 50.805 30.025 51.175 45.680 ;
        RECT 51.545 31.580 51.915 46.085 ;
        RECT 52.285 36.630 52.655 47.505 ;
        RECT 53.025 46.595 53.920 50.740 ;
        RECT 55.730 49.885 56.210 50.740 ;
        RECT 55.735 46.595 56.210 49.885 ;
        RECT 58.030 47.470 58.500 50.740 ;
        RECT 60.320 47.470 60.790 50.740 ;
        RECT 62.610 47.470 63.080 50.740 ;
        RECT 64.900 47.470 65.370 50.740 ;
        RECT 67.190 49.720 68.030 50.740 ;
        RECT 67.190 47.470 67.660 49.720 ;
        RECT 57.875 46.735 58.645 47.105 ;
        RECT 53.085 46.225 53.920 46.595 ;
        RECT 55.595 46.225 56.365 46.595 ;
        RECT 53.025 30.205 53.920 46.225 ;
        RECT 55.735 45.155 56.210 46.225 ;
        RECT 55.735 42.605 56.215 45.155 ;
        RECT 58.025 42.605 58.495 46.735 ;
        RECT 60.370 46.595 60.740 47.470 ;
        RECT 64.950 46.595 65.320 47.470 ;
        RECT 67.030 46.735 67.800 47.105 ;
        RECT 60.165 46.225 60.935 46.595 ;
        RECT 64.735 46.225 65.505 46.595 ;
        RECT 60.370 45.155 60.740 46.225 ;
        RECT 62.425 45.715 63.195 46.085 ;
        RECT 60.320 42.605 60.790 45.155 ;
        RECT 62.600 42.605 63.070 45.715 ;
        RECT 64.950 45.155 65.320 46.225 ;
        RECT 64.900 42.605 65.370 45.155 ;
        RECT 67.185 42.605 67.655 46.735 ;
        RECT 69.475 46.595 69.950 50.740 ;
        RECT 71.765 50.260 72.690 50.740 ;
        RECT 69.330 46.225 70.100 46.595 ;
        RECT 55.735 40.105 56.210 42.605 ;
        RECT 57.870 41.680 58.640 42.050 ;
        RECT 55.735 37.555 56.220 40.105 ;
        RECT 55.735 35.000 56.210 37.555 ;
        RECT 58.015 35.980 58.495 41.680 ;
        RECT 60.370 40.105 60.740 42.605 ;
        RECT 62.465 40.660 63.235 41.030 ;
        RECT 60.320 37.555 60.790 40.105 ;
        RECT 57.855 35.610 58.625 35.980 ;
        RECT 55.735 32.610 56.225 35.000 ;
        RECT 60.370 34.995 60.740 37.555 ;
        RECT 62.610 37.000 63.080 40.660 ;
        RECT 64.950 40.105 65.320 42.605 ;
        RECT 67.040 41.680 67.810 42.050 ;
        RECT 64.900 37.555 65.370 40.105 ;
        RECT 62.460 36.630 63.230 37.000 ;
        RECT 64.950 34.995 65.320 37.555 ;
        RECT 67.175 35.980 67.655 41.680 ;
        RECT 67.015 35.610 67.785 35.980 ;
        RECT 69.475 34.995 69.950 46.225 ;
        RECT 55.735 31.440 56.210 32.610 ;
        RECT 58.020 31.950 58.505 34.995 ;
        RECT 60.315 32.605 60.800 34.995 ;
        RECT 57.875 31.580 58.645 31.950 ;
        RECT 60.370 31.440 60.740 32.605 ;
        RECT 55.665 31.070 56.435 31.440 ;
        RECT 60.175 31.070 60.945 31.440 ;
        RECT 53.025 27.765 53.960 30.205 ;
        RECT 53.025 25.250 53.920 27.765 ;
        RECT 55.735 26.920 56.210 31.070 ;
        RECT 60.370 30.205 60.740 31.070 ;
        RECT 62.600 30.930 63.085 34.995 ;
        RECT 64.890 32.605 65.375 34.995 ;
        RECT 64.950 31.440 65.320 32.605 ;
        RECT 67.175 31.950 67.660 34.995 ;
        RECT 69.470 32.605 69.955 34.995 ;
        RECT 67.020 31.580 67.790 31.950 ;
        RECT 69.475 31.440 69.950 32.605 ;
        RECT 64.755 31.070 65.525 31.440 ;
        RECT 69.320 31.070 70.090 31.440 ;
        RECT 62.450 30.560 63.220 30.930 ;
        RECT 64.950 30.205 65.320 31.070 ;
        RECT 58.025 27.765 58.495 30.205 ;
        RECT 60.320 27.765 60.790 30.205 ;
        RECT 62.605 27.765 63.075 30.205 ;
        RECT 64.900 27.765 65.370 30.205 ;
        RECT 67.185 27.765 67.655 30.205 ;
        RECT 69.475 26.920 69.950 31.070 ;
        RECT 71.765 26.920 72.660 50.260 ;
        RECT 73.040 31.580 73.420 58.690 ;
        RECT 73.800 58.180 74.570 58.550 ;
        RECT 73.800 36.630 74.180 58.180 ;
        RECT 74.555 27.080 74.935 57.530 ;
        RECT 75.315 35.680 75.695 56.555 ;
        RECT 75.995 40.420 76.375 58.040 ;
        RECT 78.470 53.695 78.850 59.200 ;
        RECT 80.760 59.060 81.140 65.505 ;
        RECT 81.690 59.710 82.460 61.100 ;
        RECT 83.050 59.570 83.430 65.505 ;
        RECT 84.000 59.710 84.770 61.100 ;
        RECT 82.855 59.200 83.625 59.570 ;
        RECT 85.340 59.060 85.720 65.505 ;
        RECT 86.020 60.590 86.400 66.160 ;
        RECT 86.020 60.220 86.790 60.590 ;
        RECT 80.570 58.690 81.340 59.060 ;
        RECT 84.950 58.690 85.720 59.060 ;
        RECT 81.840 44.985 83.220 58.020 ;
        RECT 88.190 57.270 89.065 66.530 ;
        RECT 91.160 60.220 92.035 68.660 ;
        RECT 93.945 68.430 94.720 68.800 ;
        RECT 95.460 68.430 96.235 68.800 ;
        RECT 92.335 57.835 93.210 66.280 ;
        RECT 81.790 42.975 83.220 44.985 ;
        RECT 81.790 42.950 82.170 42.975 ;
        RECT 86.665 42.435 87.835 42.510 ;
        RECT 86.665 42.190 87.845 42.435 ;
        RECT 80.745 40.420 81.635 40.790 ;
        RECT 78.390 39.910 79.160 40.280 ;
        RECT 76.075 36.350 76.870 39.770 ;
        RECT 77.255 39.400 78.090 39.770 ;
        RECT 77.705 36.720 78.085 39.400 ;
        RECT 78.390 37.845 78.770 39.910 ;
        RECT 79.445 39.400 80.335 39.770 ;
        RECT 79.680 37.870 80.060 39.400 ;
        RECT 79.670 36.720 80.050 37.870 ;
        RECT 80.970 37.820 81.350 40.420 ;
        RECT 81.650 36.720 82.030 39.770 ;
        RECT 77.505 36.350 78.275 36.720 ;
        RECT 79.440 36.350 80.330 36.720 ;
        RECT 81.475 36.350 82.245 36.720 ;
        RECT 82.870 36.350 83.665 39.770 ;
        RECT 78.840 35.680 79.610 36.050 ;
        RECT 81.405 35.680 82.175 36.050 ;
        RECT 75.980 31.650 76.825 34.800 ;
        RECT 77.470 34.430 78.360 34.800 ;
        RECT 77.735 32.020 78.115 34.430 ;
        RECT 79.025 32.610 79.405 35.680 ;
        RECT 80.040 34.430 80.930 34.800 ;
        RECT 80.315 32.020 80.695 34.430 ;
        RECT 81.605 32.610 81.985 35.680 ;
        RECT 82.650 34.430 83.540 34.800 ;
        RECT 82.895 32.020 83.275 34.430 ;
        RECT 77.535 31.650 78.305 32.020 ;
        RECT 80.125 31.650 80.895 32.020 ;
        RECT 82.690 31.650 83.460 32.020 ;
        RECT 84.185 31.650 85.030 34.800 ;
        RECT 79.295 30.630 80.065 31.000 ;
        RECT 76.000 30.475 76.770 30.490 ;
        RECT 75.980 27.590 76.810 30.475 ;
        RECT 78.225 30.120 78.995 30.490 ;
        RECT 78.615 27.960 78.995 30.120 ;
        RECT 78.225 27.590 78.995 27.960 ;
        RECT 79.295 27.450 79.675 30.630 ;
        RECT 81.640 27.590 82.470 30.490 ;
        RECT 84.450 27.960 85.280 30.490 ;
        RECT 86.660 28.220 87.845 42.190 ;
        RECT 86.660 27.960 87.855 28.220 ;
        RECT 84.395 27.590 87.855 27.960 ;
        RECT 79.295 27.080 80.065 27.450 ;
        RECT 61.555 26.410 63.125 26.780 ;
        RECT 74.125 26.410 75.695 26.780 ;
        RECT 55.850 25.900 57.420 26.270 ;
        RECT 42.140 24.880 45.645 25.250 ;
        RECT 47.860 24.880 49.430 25.250 ;
        RECT 53.025 24.880 55.545 25.250 ;
        RECT 36.720 12.800 37.890 13.170 ;
        RECT 38.650 12.800 41.420 14.300 ;
        RECT 43.065 13.680 43.895 24.880 ;
        RECT 47.860 13.680 49.380 24.880 ;
        RECT 55.165 13.680 55.545 24.880 ;
        RECT 55.850 14.305 56.230 25.900 ;
        RECT 57.765 24.370 60.535 25.760 ;
        RECT 62.140 14.310 62.520 26.410 ;
        RECT 68.430 26.270 68.810 26.290 ;
        RECT 67.840 25.900 69.410 26.270 ;
        RECT 64.200 24.370 66.970 25.760 ;
        RECT 68.430 14.310 68.810 25.900 ;
        RECT 70.470 24.370 73.240 25.760 ;
        RECT 74.720 14.310 75.100 26.410 ;
        RECT 79.820 25.900 81.390 26.270 ;
        RECT 76.515 24.370 79.285 25.760 ;
        RECT 81.010 14.310 81.390 25.900 ;
        RECT 86.660 25.250 87.855 27.590 ;
        RECT 88.250 26.410 88.945 44.985 ;
        RECT 89.245 27.285 90.120 56.970 ;
        RECT 91.390 56.685 92.175 57.055 ;
        RECT 91.390 53.690 91.770 56.685 ;
        RECT 93.510 47.525 94.385 67.275 ;
        RECT 95.160 59.950 95.540 67.270 ;
        RECT 95.855 63.010 96.235 68.430 ;
        RECT 98.435 68.000 98.895 69.030 ;
        RECT 101.705 68.800 102.085 73.015 ;
        RECT 102.995 69.540 103.740 74.070 ;
        RECT 113.600 73.375 114.370 73.745 ;
        RECT 114.880 73.375 115.650 73.745 ;
        RECT 100.620 68.430 101.395 68.800 ;
        RECT 101.705 68.430 102.475 68.800 ;
        RECT 97.145 58.815 97.525 64.240 ;
        RECT 98.435 63.010 98.815 68.000 ;
        RECT 99.725 58.815 100.105 64.235 ;
        RECT 101.015 63.010 101.395 68.430 ;
        RECT 101.705 59.975 102.085 67.295 ;
        RECT 102.865 59.970 103.740 67.270 ;
        RECT 104.040 60.480 104.420 73.190 ;
        RECT 104.720 69.855 105.595 72.680 ;
        RECT 104.720 61.105 105.100 69.205 ;
        RECT 106.415 68.695 106.795 71.700 ;
        RECT 107.695 69.205 108.075 71.700 ;
        RECT 107.305 68.835 108.075 69.205 ;
        RECT 108.975 68.695 109.355 71.700 ;
        RECT 110.175 69.855 111.050 72.680 ;
        RECT 111.350 69.260 111.730 73.235 ;
        RECT 112.030 69.905 112.875 72.725 ;
        RECT 111.355 68.870 111.725 69.260 ;
        RECT 113.775 69.160 114.155 73.375 ;
        RECT 115.055 69.160 115.435 73.375 ;
        RECT 113.580 68.790 114.350 69.160 ;
        RECT 114.860 68.790 115.630 69.160 ;
        RECT 116.335 68.825 117.210 72.725 ;
        RECT 106.215 68.325 106.985 68.695 ;
        RECT 108.455 68.325 109.560 68.695 ;
        RECT 107.190 68.080 107.560 68.085 ;
        RECT 107.175 67.710 107.975 68.080 ;
        RECT 105.400 67.410 105.700 67.570 ;
        RECT 97.145 58.445 97.925 58.815 ;
        RECT 99.325 58.445 100.105 58.815 ;
        RECT 98.860 57.235 99.645 57.605 ;
        RECT 98.860 53.695 99.240 57.235 ;
        RECT 103.330 53.660 104.205 58.205 ;
        RECT 105.400 51.545 106.710 67.410 ;
        RECT 107.175 61.985 107.555 67.710 ;
        RECT 108.455 63.130 108.835 68.325 ;
        RECT 109.735 67.710 110.530 68.080 ;
        RECT 107.175 61.980 107.605 61.985 ;
        RECT 108.430 61.980 108.970 61.985 ;
        RECT 107.175 61.615 107.970 61.980 ;
        RECT 108.430 61.615 109.215 61.980 ;
        RECT 108.590 57.240 108.970 61.615 ;
        RECT 109.735 61.610 110.115 67.710 ;
        RECT 110.615 62.285 111.705 67.370 ;
        RECT 108.590 57.235 108.965 57.240 ;
        RECT 105.120 49.430 106.710 51.545 ;
        RECT 105.400 49.065 106.710 49.430 ;
        RECT 105.305 48.705 106.915 49.065 ;
        RECT 109.930 46.390 110.310 60.850 ;
        RECT 108.175 46.385 110.310 46.390 ;
        RECT 91.330 44.505 110.310 46.385 ;
        RECT 91.330 41.550 109.190 44.505 ;
        RECT 109.930 41.550 110.310 44.505 ;
        RECT 91.330 39.665 110.310 41.550 ;
        RECT 91.330 36.210 109.190 39.665 ;
        RECT 109.930 36.210 110.310 39.665 ;
        RECT 91.330 34.325 110.310 36.210 ;
        RECT 91.330 33.215 109.190 34.325 ;
        RECT 109.930 33.215 110.310 34.325 ;
        RECT 91.330 31.335 110.310 33.215 ;
        RECT 91.330 31.330 109.555 31.335 ;
        RECT 91.330 29.985 109.190 31.330 ;
        RECT 110.610 27.565 110.990 61.475 ;
        RECT 89.245 26.410 91.845 27.285 ;
        RECT 81.690 24.880 84.690 25.250 ;
        RECT 42.060 13.310 44.830 13.680 ;
        RECT 47.250 13.310 50.020 13.680 ;
        RECT 54.045 13.310 56.815 13.680 ;
        RECT 57.765 12.800 60.535 14.190 ;
        RECT 64.200 12.800 66.970 14.190 ;
        RECT 70.470 12.800 73.240 14.190 ;
        RECT 76.515 12.800 79.285 14.190 ;
        RECT 81.690 13.680 82.070 24.880 ;
        RECT 86.660 24.580 88.735 25.250 ;
        RECT 80.485 13.310 83.255 13.680 ;
        RECT 87.860 13.310 88.735 24.580 ;
        RECT 89.115 12.800 89.495 25.760 ;
        RECT 89.795 21.130 90.670 24.325 ;
        RECT 90.970 20.145 91.845 26.410 ;
        RECT 109.885 27.185 110.990 27.565 ;
        RECT 109.885 26.330 110.380 27.185 ;
        RECT 111.290 26.885 111.670 58.815 ;
        RECT 112.030 49.405 112.410 67.410 ;
        RECT 112.710 27.815 113.090 66.895 ;
        RECT 113.390 28.330 114.545 66.380 ;
        RECT 114.845 52.120 115.225 68.075 ;
        RECT 115.805 52.120 116.185 68.075 ;
        RECT 116.765 52.120 117.145 68.075 ;
        RECT 117.730 52.120 118.110 68.075 ;
        RECT 118.690 58.755 119.070 68.075 ;
        RECT 118.685 52.120 119.065 58.755 ;
        RECT 119.650 52.120 120.030 68.075 ;
        RECT 120.610 58.755 120.990 68.075 ;
        RECT 120.605 52.120 120.985 58.755 ;
        RECT 121.570 52.120 121.950 68.075 ;
        RECT 122.530 58.755 122.910 68.075 ;
        RECT 122.525 52.120 122.905 58.755 ;
        RECT 123.490 52.120 123.870 68.075 ;
        RECT 124.450 58.755 124.830 68.075 ;
        RECT 124.445 52.120 124.825 58.755 ;
        RECT 125.410 52.120 125.790 68.075 ;
        RECT 126.370 58.755 126.750 68.075 ;
        RECT 126.365 52.120 126.745 58.755 ;
        RECT 127.330 52.120 127.710 68.075 ;
        RECT 128.290 58.755 128.670 68.075 ;
        RECT 128.285 52.120 128.665 58.755 ;
        RECT 129.250 52.120 129.630 68.075 ;
        RECT 130.210 58.755 130.590 68.075 ;
        RECT 130.205 52.120 130.585 58.755 ;
        RECT 131.170 52.120 131.550 68.075 ;
        RECT 132.130 58.755 132.510 68.075 ;
        RECT 132.125 52.120 132.505 58.755 ;
        RECT 133.090 52.120 133.470 68.075 ;
        RECT 134.050 58.755 134.430 68.075 ;
        RECT 134.045 52.120 134.425 58.755 ;
        RECT 135.010 52.120 135.390 68.075 ;
        RECT 135.970 58.755 136.350 68.075 ;
        RECT 135.965 52.120 136.345 58.755 ;
        RECT 136.930 52.120 137.310 68.075 ;
        RECT 137.890 58.810 138.270 68.075 ;
        RECT 137.885 58.710 138.270 58.810 ;
        RECT 137.885 52.095 138.265 58.710 ;
        RECT 115.325 40.565 115.705 50.495 ;
        RECT 116.285 40.565 116.665 50.495 ;
        RECT 117.245 40.565 117.625 50.495 ;
        RECT 118.205 40.565 118.585 50.495 ;
        RECT 119.165 40.565 119.545 50.495 ;
        RECT 120.125 40.565 120.505 50.495 ;
        RECT 121.085 40.565 121.465 50.495 ;
        RECT 122.045 40.565 122.425 50.495 ;
        RECT 123.005 40.565 123.385 50.495 ;
        RECT 123.965 40.565 124.345 50.495 ;
        RECT 124.925 40.565 125.305 50.495 ;
        RECT 125.885 40.565 126.265 50.495 ;
        RECT 126.845 40.565 127.225 50.495 ;
        RECT 127.805 40.565 128.185 50.495 ;
        RECT 128.765 40.565 129.145 50.495 ;
        RECT 129.725 40.565 130.105 50.495 ;
        RECT 130.685 40.565 131.065 50.495 ;
        RECT 131.645 40.565 132.025 50.495 ;
        RECT 132.605 40.565 132.985 50.495 ;
        RECT 133.565 40.565 133.945 50.495 ;
        RECT 134.525 40.565 134.905 50.495 ;
        RECT 135.485 40.565 135.865 50.495 ;
        RECT 136.445 40.565 136.825 50.495 ;
        RECT 137.405 40.565 137.785 50.495 ;
        RECT 138.570 28.330 139.720 69.195 ;
        RECT 110.970 26.540 111.670 26.885 ;
        RECT 103.840 25.960 104.610 26.330 ;
        RECT 109.745 25.960 110.520 26.330 ;
        RECT 94.675 25.450 95.445 25.820 ;
        RECT 99.270 25.450 100.040 25.820 ;
        RECT 92.580 21.130 92.960 24.325 ;
        RECT 93.530 23.805 94.295 25.310 ;
        RECT 93.530 23.435 94.300 23.805 ;
        RECT 93.530 22.030 94.295 23.435 ;
        RECT 94.870 22.135 95.250 25.450 ;
        RECT 95.820 23.790 96.585 25.310 ;
        RECT 95.820 23.420 96.590 23.790 ;
        RECT 95.820 22.030 96.585 23.420 ;
        RECT 93.530 21.660 94.300 22.030 ;
        RECT 95.820 21.660 96.590 22.030 ;
        RECT 93.530 20.145 94.295 21.660 ;
        RECT 95.820 20.145 96.585 21.660 ;
        RECT 97.160 21.130 97.540 24.325 ;
        RECT 98.110 23.790 98.875 25.310 ;
        RECT 98.110 23.420 98.880 23.790 ;
        RECT 98.110 22.030 98.875 23.420 ;
        RECT 99.450 22.135 99.830 25.450 ;
        RECT 100.400 23.790 101.165 25.310 ;
        RECT 100.400 23.420 101.170 23.790 ;
        RECT 100.400 22.030 101.165 23.420 ;
        RECT 98.110 21.660 98.880 22.030 ;
        RECT 100.400 21.660 101.170 22.030 ;
        RECT 98.110 20.145 98.875 21.660 ;
        RECT 100.400 20.145 101.165 21.660 ;
        RECT 101.740 21.130 102.120 24.325 ;
        RECT 102.690 23.790 103.455 25.310 ;
        RECT 102.690 23.420 103.460 23.790 ;
        RECT 102.690 22.030 103.455 23.420 ;
        RECT 104.030 22.135 104.410 25.960 ;
        RECT 110.970 25.820 111.350 26.540 ;
        RECT 113.005 25.960 113.775 26.330 ;
        RECT 108.430 25.450 109.200 25.820 ;
        RECT 110.805 25.450 111.580 25.820 ;
        RECT 104.980 23.790 105.745 25.310 ;
        RECT 104.980 23.420 105.750 23.790 ;
        RECT 104.980 22.030 105.745 23.420 ;
        RECT 102.690 21.660 103.460 22.030 ;
        RECT 104.980 21.660 105.750 22.030 ;
        RECT 102.690 20.145 103.455 21.660 ;
        RECT 104.980 20.145 105.745 21.660 ;
        RECT 106.320 21.130 106.700 24.325 ;
        RECT 107.270 23.790 108.035 25.310 ;
        RECT 107.270 23.420 108.040 23.790 ;
        RECT 107.270 22.030 108.035 23.420 ;
        RECT 108.610 22.135 108.990 25.450 ;
        RECT 109.560 23.790 110.325 25.310 ;
        RECT 109.560 23.420 110.330 23.790 ;
        RECT 109.560 22.030 110.325 23.420 ;
        RECT 107.270 21.660 108.040 22.030 ;
        RECT 109.560 21.660 110.330 22.030 ;
        RECT 107.270 20.145 108.035 21.660 ;
        RECT 109.560 20.145 110.325 21.660 ;
        RECT 110.900 21.130 111.280 24.325 ;
        RECT 111.850 23.790 112.615 25.310 ;
        RECT 111.850 23.420 112.620 23.790 ;
        RECT 111.850 22.030 112.615 23.420 ;
        RECT 113.190 22.135 113.570 25.960 ;
        RECT 117.560 25.450 118.330 25.820 ;
        RECT 122.150 25.450 122.920 25.820 ;
        RECT 114.140 23.790 114.905 25.310 ;
        RECT 114.140 23.420 114.910 23.790 ;
        RECT 114.140 22.030 114.905 23.420 ;
        RECT 111.850 21.660 112.620 22.030 ;
        RECT 114.135 21.660 114.905 22.030 ;
        RECT 111.850 20.145 112.615 21.660 ;
        RECT 114.140 20.145 114.905 21.660 ;
        RECT 115.480 21.130 115.860 24.325 ;
        RECT 116.430 23.790 117.195 25.310 ;
        RECT 116.430 23.420 117.200 23.790 ;
        RECT 116.430 22.030 117.195 23.420 ;
        RECT 117.770 22.135 118.150 25.450 ;
        RECT 118.720 23.790 119.485 25.310 ;
        RECT 118.720 23.420 119.490 23.790 ;
        RECT 118.720 22.030 119.485 23.420 ;
        RECT 116.430 21.660 117.200 22.030 ;
        RECT 118.720 21.660 119.490 22.030 ;
        RECT 116.430 20.145 117.195 21.660 ;
        RECT 118.720 20.145 119.485 21.660 ;
        RECT 120.060 21.130 120.440 24.325 ;
        RECT 121.010 23.790 121.775 25.310 ;
        RECT 121.010 23.420 121.780 23.790 ;
        RECT 121.010 22.030 121.775 23.420 ;
        RECT 122.350 22.135 122.730 25.450 ;
        RECT 123.300 23.790 124.065 25.310 ;
        RECT 123.300 23.420 124.070 23.790 ;
        RECT 123.300 22.030 124.065 23.420 ;
        RECT 121.010 21.660 121.780 22.030 ;
        RECT 123.300 21.660 124.070 22.030 ;
        RECT 121.010 20.145 121.775 21.660 ;
        RECT 123.300 20.145 124.065 21.660 ;
        RECT 124.640 21.130 125.020 24.325 ;
        RECT 126.930 21.130 127.805 24.325 ;
        RECT 140.155 2.045 141.040 66.515 ;
        RECT 146.305 65.785 146.675 66.555 ;
        RECT 141.430 1.525 142.315 65.745 ;
        RECT 144.870 65.400 145.240 65.770 ;
        RECT 142.810 64.795 143.140 65.125 ;
        RECT 142.825 62.135 143.125 64.795 ;
        RECT 142.810 61.495 143.140 62.135 ;
        RECT 142.825 59.225 143.125 61.495 ;
        RECT 142.795 58.585 143.125 59.225 ;
        RECT 142.825 55.970 143.125 58.585 ;
        RECT 143.525 57.910 143.825 65.105 ;
        RECT 144.205 64.795 144.535 65.125 ;
        RECT 144.225 62.135 144.525 64.795 ;
        RECT 144.910 64.635 145.240 65.400 ;
        RECT 144.210 61.495 144.540 62.135 ;
        RECT 144.225 59.225 144.525 61.495 ;
        RECT 144.210 58.585 144.540 59.225 ;
        RECT 143.510 57.270 143.840 57.910 ;
        RECT 142.810 55.640 143.140 55.970 ;
        RECT 142.840 54.700 143.140 55.640 ;
        RECT 143.525 55.340 143.825 57.270 ;
        RECT 144.225 55.970 144.525 58.585 ;
        RECT 144.925 56.025 145.225 64.635 ;
        RECT 145.625 62.135 145.925 65.105 ;
        RECT 146.340 64.120 146.640 65.785 ;
        RECT 147.120 64.795 147.450 65.125 ;
        RECT 146.325 63.790 146.655 64.120 ;
        RECT 145.610 61.495 145.940 62.135 ;
        RECT 145.625 59.225 145.925 61.495 ;
        RECT 145.610 58.585 145.940 59.225 ;
        RECT 144.205 55.640 144.535 55.970 ;
        RECT 144.910 55.695 145.240 56.025 ;
        RECT 144.925 55.640 145.225 55.695 ;
        RECT 143.525 55.025 143.880 55.340 ;
        RECT 143.550 55.010 143.880 55.025 ;
        RECT 144.600 55.010 144.930 55.340 ;
        RECT 142.840 54.690 144.000 54.700 ;
        RECT 142.840 54.390 144.005 54.690 ;
        RECT 142.930 52.410 144.005 54.390 ;
        RECT 144.615 53.795 144.915 55.010 ;
        RECT 145.625 54.710 145.925 58.585 ;
        RECT 146.340 56.870 146.640 63.790 ;
        RECT 147.135 62.135 147.435 64.795 ;
        RECT 147.120 61.495 147.450 62.135 ;
        RECT 147.135 59.225 147.435 61.495 ;
        RECT 147.835 60.505 148.135 65.100 ;
        RECT 148.520 64.795 148.850 65.125 ;
        RECT 148.535 62.135 148.835 64.795 ;
        RECT 149.235 63.465 149.535 65.105 ;
        RECT 149.220 62.825 149.550 63.465 ;
        RECT 148.520 61.495 148.850 62.135 ;
        RECT 147.820 59.865 148.150 60.505 ;
        RECT 147.120 58.585 147.450 59.225 ;
        RECT 146.325 56.540 146.655 56.870 ;
        RECT 146.340 55.640 146.640 56.540 ;
        RECT 147.135 55.960 147.435 58.585 ;
        RECT 147.120 55.630 147.450 55.960 ;
        RECT 147.835 55.510 148.135 59.865 ;
        RECT 148.535 59.225 148.835 61.495 ;
        RECT 148.520 58.585 148.850 59.225 ;
        RECT 148.535 55.960 148.835 58.585 ;
        RECT 149.235 56.310 149.535 62.825 ;
        RECT 149.935 56.765 151.885 65.200 ;
        RECT 153.020 57.095 154.970 65.200 ;
        RECT 156.140 57.790 158.090 65.200 ;
        RECT 156.640 57.115 156.970 57.445 ;
        RECT 153.545 56.405 153.875 56.735 ;
        RECT 149.220 55.980 149.550 56.310 ;
        RECT 151.650 55.980 151.980 56.310 ;
        RECT 148.515 55.630 148.845 55.960 ;
        RECT 147.835 55.180 148.190 55.510 ;
        RECT 147.835 55.170 148.135 55.180 ;
        RECT 150.280 55.175 150.610 55.505 ;
        RECT 144.600 53.465 144.930 53.795 ;
        RECT 142.930 52.230 144.000 52.410 ;
        RECT 144.615 52.230 144.915 53.465 ;
        RECT 145.335 52.190 146.305 54.710 ;
        RECT 147.435 52.190 148.325 54.710 ;
        RECT 149.575 54.700 149.875 54.705 ;
        RECT 148.745 53.610 149.045 54.670 ;
        RECT 149.560 54.370 149.890 54.700 ;
        RECT 149.575 53.620 149.875 54.370 ;
        RECT 148.710 53.280 149.045 53.610 ;
        RECT 143.625 51.600 143.955 51.930 ;
        RECT 142.850 50.575 143.300 50.610 ;
        RECT 142.790 48.025 143.305 50.575 ;
        RECT 143.640 50.070 143.940 51.600 ;
        RECT 148.745 51.580 149.045 53.280 ;
        RECT 149.525 53.235 149.935 53.620 ;
        RECT 149.575 52.560 149.875 53.235 ;
        RECT 149.560 52.230 149.890 52.560 ;
        RECT 149.495 51.915 149.825 51.930 ;
        RECT 150.295 51.915 150.595 55.175 ;
        RECT 150.975 54.700 151.275 54.705 ;
        RECT 150.960 54.370 151.290 54.700 ;
        RECT 150.975 53.610 151.275 54.370 ;
        RECT 150.960 53.240 151.290 53.610 ;
        RECT 150.975 52.520 151.275 53.240 ;
        RECT 150.960 52.190 151.290 52.520 ;
        RECT 149.495 51.615 150.595 51.915 ;
        RECT 149.495 51.600 149.825 51.615 ;
        RECT 148.725 51.250 149.055 51.580 ;
        RECT 145.495 50.900 145.825 51.230 ;
        RECT 145.525 50.600 145.825 50.900 ;
        RECT 146.685 50.610 146.985 50.710 ;
        RECT 143.640 49.740 143.985 50.070 ;
        RECT 143.640 48.870 143.940 49.740 ;
        RECT 143.625 48.540 143.955 48.870 ;
        RECT 142.850 48.000 143.305 48.025 ;
        RECT 142.820 40.465 143.340 47.505 ;
        RECT 143.640 46.970 143.940 48.540 ;
        RECT 144.285 47.990 145.225 50.600 ;
        RECT 145.525 50.515 146.255 50.600 ;
        RECT 145.525 50.300 146.285 50.515 ;
        RECT 145.970 50.080 146.285 50.300 ;
        RECT 146.670 50.280 147.000 50.610 ;
        RECT 145.970 49.915 146.300 50.080 ;
        RECT 145.940 49.750 146.300 49.915 ;
        RECT 145.940 48.875 146.240 49.750 ;
        RECT 146.685 49.465 146.985 50.280 ;
        RECT 148.000 50.095 148.300 50.215 ;
        RECT 148.625 50.095 149.115 50.390 ;
        RECT 146.670 49.135 147.000 49.465 ;
        RECT 147.985 49.135 148.315 50.095 ;
        RECT 148.625 50.060 149.120 50.095 ;
        RECT 145.940 48.545 146.285 48.875 ;
        RECT 143.640 46.665 144.050 46.970 ;
        RECT 143.720 46.640 144.050 46.665 ;
        RECT 143.735 41.335 144.035 46.640 ;
        RECT 143.720 41.005 144.050 41.335 ;
        RECT 144.440 40.490 145.380 47.515 ;
        RECT 145.940 46.970 146.240 48.545 ;
        RECT 146.685 48.340 146.985 49.135 ;
        RECT 148.000 48.730 148.300 49.135 ;
        RECT 148.630 48.730 149.120 50.060 ;
        RECT 149.515 50.040 149.815 51.600 ;
        RECT 151.665 51.230 151.965 55.980 ;
        RECT 152.695 55.380 153.155 55.385 ;
        RECT 152.695 51.965 153.160 55.380 ;
        RECT 153.560 53.975 153.860 56.405 ;
        RECT 153.545 53.645 153.875 53.975 ;
        RECT 152.695 51.950 153.155 51.965 ;
        RECT 152.680 51.250 153.010 51.580 ;
        RECT 151.055 50.910 151.965 51.230 ;
        RECT 151.055 50.900 151.385 50.910 ;
        RECT 149.500 49.710 149.830 50.040 ;
        RECT 146.670 48.010 147.000 48.340 ;
        RECT 146.625 47.175 146.955 47.505 ;
        RECT 145.815 46.665 146.240 46.970 ;
        RECT 145.815 46.640 146.145 46.665 ;
        RECT 145.830 41.335 146.130 46.640 ;
        RECT 146.655 46.485 146.955 47.175 ;
        RECT 146.640 45.845 146.970 46.485 ;
        RECT 147.985 46.290 148.315 48.730 ;
        RECT 148.625 48.250 149.120 48.730 ;
        RECT 149.515 48.420 149.815 49.710 ;
        RECT 148.630 46.615 149.120 48.250 ;
        RECT 149.500 48.090 149.830 48.420 ;
        RECT 149.515 46.740 149.815 48.090 ;
        RECT 148.000 46.280 148.300 46.290 ;
        RECT 148.625 46.285 149.120 46.615 ;
        RECT 149.500 46.410 149.830 46.740 ;
        RECT 146.655 45.085 146.955 45.845 ;
        RECT 146.625 44.445 146.955 45.085 ;
        RECT 146.655 43.610 146.955 44.445 ;
        RECT 146.640 42.970 146.970 43.610 ;
        RECT 146.655 42.125 146.955 42.970 ;
        RECT 146.640 41.485 146.970 42.125 ;
        RECT 145.815 41.005 146.145 41.335 ;
        RECT 146.655 40.795 146.955 41.485 ;
        RECT 148.115 40.850 148.835 45.980 ;
        RECT 149.515 44.700 149.815 46.410 ;
        RECT 150.215 46.285 150.705 50.390 ;
        RECT 151.070 49.180 151.370 50.900 ;
        RECT 151.070 48.850 151.425 49.180 ;
        RECT 151.070 47.530 151.370 48.850 ;
        RECT 151.055 47.200 151.385 47.530 ;
        RECT 151.070 45.580 151.370 47.200 ;
        RECT 151.805 46.285 152.295 50.390 ;
        RECT 152.695 48.725 152.995 51.250 ;
        RECT 152.680 48.395 153.010 48.725 ;
        RECT 152.695 46.280 152.995 48.395 ;
        RECT 153.395 46.285 153.885 50.390 ;
        RECT 154.260 50.095 154.680 57.095 ;
        RECT 155.780 55.380 156.250 55.385 ;
        RECT 155.780 51.860 156.255 55.380 ;
        RECT 156.655 53.200 156.955 57.115 ;
        RECT 157.350 54.780 157.790 57.790 ;
        RECT 158.135 57.115 158.465 57.445 ;
        RECT 156.640 52.870 156.970 53.200 ;
        RECT 157.355 51.860 157.790 54.780 ;
        RECT 158.150 54.900 158.450 57.115 ;
        RECT 158.965 56.720 159.865 65.815 ;
        RECT 160.685 56.835 162.635 65.200 ;
        RECT 163.345 57.115 164.245 65.105 ;
        RECT 161.095 56.765 162.635 56.835 ;
        RECT 165.175 56.765 167.125 65.200 ;
        RECT 158.965 56.405 160.390 56.720 ;
        RECT 159.390 55.445 159.690 56.075 ;
        RECT 159.375 55.115 159.705 55.445 ;
        RECT 158.150 54.600 158.990 54.900 ;
        RECT 159.390 54.710 159.690 55.115 ;
        RECT 158.690 54.100 158.990 54.600 ;
        RECT 159.375 54.380 159.705 54.710 ;
        RECT 158.675 53.770 159.005 54.100 ;
        RECT 158.690 51.540 158.990 53.770 ;
        RECT 159.390 53.195 159.690 54.380 ;
        RECT 159.375 52.865 159.705 53.195 ;
        RECT 156.690 51.240 158.990 51.540 ;
        RECT 154.275 46.285 154.765 50.095 ;
        RECT 151.055 45.250 151.385 45.580 ;
        RECT 149.500 44.370 149.830 44.700 ;
        RECT 150.555 44.370 150.885 44.700 ;
        RECT 149.400 40.865 150.115 44.025 ;
        RECT 150.570 42.120 150.870 44.370 ;
        RECT 150.555 41.790 150.885 42.120 ;
        RECT 151.270 40.865 151.985 44.750 ;
        RECT 153.210 44.665 153.930 45.985 ;
        RECT 154.470 45.250 154.800 45.580 ;
        RECT 149.400 40.850 150.110 40.865 ;
        RECT 151.270 40.850 151.980 40.865 ;
        RECT 153.215 40.850 153.930 44.665 ;
        RECT 154.485 42.120 154.785 45.250 ;
        RECT 155.670 45.045 156.390 46.020 ;
        RECT 154.470 41.790 154.800 42.120 ;
        RECT 155.675 40.850 156.390 45.045 ;
        RECT 156.690 45.810 157.170 51.240 ;
        RECT 159.390 50.755 159.690 52.865 ;
        RECT 160.090 52.780 160.390 56.405 ;
        RECT 163.380 55.980 163.710 56.310 ;
        RECT 160.785 55.445 161.085 55.500 ;
        RECT 162.045 55.445 162.345 55.505 ;
        RECT 160.770 55.115 161.100 55.445 ;
        RECT 162.030 55.115 162.360 55.445 ;
        RECT 160.785 54.710 161.085 55.115 ;
        RECT 160.755 54.380 161.085 54.710 ;
        RECT 160.785 53.195 161.085 54.380 ;
        RECT 162.045 53.195 162.345 55.115 ;
        RECT 163.395 54.605 163.695 55.980 ;
        RECT 163.370 54.275 163.700 54.605 ;
        RECT 160.785 52.865 161.115 53.195 ;
        RECT 162.030 52.865 162.360 53.195 ;
        RECT 160.075 52.450 160.405 52.780 ;
        RECT 157.590 50.455 159.690 50.755 ;
        RECT 157.590 50.270 157.905 50.455 ;
        RECT 157.575 49.940 157.905 50.270 ;
        RECT 160.090 50.055 160.390 52.450 ;
        RECT 160.785 52.325 161.085 52.865 ;
        RECT 162.045 52.325 162.345 52.865 ;
        RECT 160.770 51.995 161.100 52.325 ;
        RECT 162.030 51.995 162.360 52.325 ;
        RECT 157.590 49.020 157.890 49.940 ;
        RECT 158.265 49.755 160.390 50.055 ;
        RECT 160.785 50.035 161.085 51.995 ;
        RECT 161.385 51.550 161.715 51.880 ;
        RECT 161.400 50.640 161.700 51.550 ;
        RECT 161.385 50.310 161.715 50.640 ;
        RECT 162.045 50.240 162.345 51.995 ;
        RECT 163.395 51.455 163.695 54.275 ;
        RECT 164.700 53.195 165.000 55.760 ;
        RECT 166.115 55.065 166.445 55.855 ;
        RECT 164.685 52.865 165.015 53.195 ;
        RECT 162.670 51.155 163.710 51.455 ;
        RECT 162.670 51.125 163.000 51.155 ;
        RECT 163.380 51.125 163.710 51.155 ;
        RECT 157.590 48.185 157.920 49.020 ;
        RECT 157.590 47.870 157.890 48.185 ;
        RECT 157.590 47.530 157.920 47.870 ;
        RECT 157.590 47.100 157.890 47.530 ;
        RECT 157.590 46.760 157.920 47.100 ;
        RECT 157.590 46.360 157.890 46.760 ;
        RECT 157.590 46.020 157.920 46.360 ;
        RECT 156.690 45.480 157.185 45.810 ;
        RECT 146.625 40.465 146.955 40.795 ;
        RECT 156.690 40.780 157.170 45.480 ;
        RECT 157.590 44.560 157.890 46.020 ;
        RECT 158.265 45.385 158.565 49.755 ;
        RECT 158.250 45.055 158.580 45.385 ;
        RECT 157.590 44.220 157.920 44.560 ;
        RECT 157.590 42.400 157.890 44.220 ;
        RECT 157.590 42.060 157.920 42.400 ;
        RECT 156.690 40.450 157.185 40.780 ;
        RECT 156.690 37.235 157.170 40.450 ;
        RECT 157.590 40.295 157.890 42.060 ;
        RECT 158.265 41.900 158.565 45.055 ;
        RECT 158.250 41.570 158.580 41.900 ;
        RECT 157.590 39.955 157.920 40.295 ;
        RECT 157.590 38.125 157.890 39.955 ;
        RECT 157.590 37.785 157.920 38.125 ;
        RECT 156.690 36.905 157.185 37.235 ;
        RECT 156.690 2.170 157.170 36.905 ;
        RECT 157.590 36.535 157.890 37.785 ;
        RECT 158.265 36.825 158.565 41.570 ;
        RECT 158.250 36.495 158.580 36.825 ;
        RECT 159.010 32.690 161.205 49.270 ;
        RECT 161.705 32.700 162.605 49.900 ;
        RECT 164.700 49.270 165.000 52.865 ;
        RECT 166.130 50.640 166.430 55.065 ;
        RECT 167.285 52.325 167.585 55.500 ;
        RECT 171.100 54.640 181.160 55.970 ;
        RECT 168.205 53.285 168.535 53.615 ;
        RECT 167.255 51.995 167.585 52.325 ;
        RECT 166.100 50.310 166.430 50.640 ;
        RECT 167.285 50.035 167.585 51.995 ;
        RECT 168.220 49.880 168.520 53.285 ;
        RECT 169.145 51.625 169.475 51.955 ;
        RECT 168.205 49.550 168.535 49.880 ;
        RECT 169.160 49.530 169.460 51.625 ;
        RECT 171.100 49.745 181.160 51.075 ;
        RECT 163.240 32.690 165.435 49.270 ;
        RECT 166.000 32.820 166.900 49.530 ;
        RECT 169.145 49.200 169.475 49.530 ;
        RECT 167.405 32.690 169.600 48.850 ;
        RECT 171.100 45.095 181.160 46.425 ;
        RECT 171.100 40.535 181.160 41.865 ;
        RECT 171.100 36.445 181.160 37.775 ;
        RECT 171.100 32.690 181.160 34.020 ;
        RECT 171.045 21.980 181.160 23.320 ;
        RECT 171.045 12.730 181.160 13.885 ;
      LAYER met4 ;
        RECT 139.240 221.805 159.865 222.705 ;
        RECT 93.270 62.595 94.570 65.295 ;
        RECT 102.460 62.595 103.760 65.240 ;
        RECT 105.705 62.595 106.565 67.570 ;
        RECT 110.795 62.595 111.655 67.405 ;
        RECT 93.270 61.735 111.890 62.595 ;
        RECT 93.270 56.655 94.570 61.735 ;
        RECT 102.460 56.655 103.760 61.735 ;
        RECT 143.210 58.180 144.510 65.250 ;
        RECT 114.845 56.880 144.510 58.180 ;
        RECT 76.825 55.355 107.165 56.655 ;
        RECT 31.430 49.800 32.760 50.750 ;
        RECT 45.020 49.800 46.350 51.050 ;
        RECT 54.160 49.800 55.490 51.370 ;
        RECT 70.580 49.800 71.910 50.720 ;
        RECT 76.910 49.800 78.240 51.330 ;
        RECT 83.220 49.800 84.550 50.850 ;
        RECT 93.270 49.800 94.570 55.355 ;
        RECT 102.460 49.800 103.760 55.355 ;
        RECT 105.090 49.800 105.560 51.605 ;
        RECT 31.430 48.500 107.060 49.800 ;
        RECT 143.210 49.205 144.510 56.880 ;
        RECT 149.910 49.205 151.905 65.200 ;
        RECT 156.430 63.955 158.415 65.205 ;
        RECT 158.965 64.660 159.865 221.805 ;
        RECT 156.430 62.655 175.860 63.955 ;
        RECT 156.430 57.760 158.415 62.655 ;
        RECT 170.560 62.645 175.860 62.655 ;
        RECT 174.550 57.760 175.860 62.645 ;
        RECT 156.430 56.430 175.860 57.760 ;
        RECT 156.430 49.205 158.415 56.430 ;
        RECT 159.010 54.640 172.555 55.970 ;
        RECT 159.010 49.745 172.555 51.075 ;
        RECT 31.430 29.710 32.760 48.500 ;
        RECT 45.020 29.710 46.350 48.500 ;
        RECT 46.700 29.710 47.080 30.215 ;
        RECT 54.160 29.710 55.490 48.500 ;
        RECT 31.430 29.480 70.040 29.710 ;
        RECT 70.580 29.480 71.910 48.500 ;
        RECT 76.910 29.480 78.240 48.500 ;
        RECT 83.220 29.480 84.550 48.500 ;
        RECT 102.460 48.445 103.760 48.500 ;
        RECT 105.090 45.990 105.560 48.500 ;
        RECT 143.210 47.905 158.615 49.205 ;
        RECT 143.210 47.890 144.510 47.905 ;
        RECT 91.725 30.380 107.335 45.990 ;
        RECT 108.690 30.045 109.170 46.325 ;
        RECT 159.010 45.095 172.555 46.425 ;
        RECT 142.800 40.535 172.555 41.870 ;
        RECT 158.955 36.445 172.555 37.775 ;
        RECT 159.010 32.690 172.555 34.020 ;
        RECT 31.430 28.380 84.550 29.480 ;
        RECT 31.430 23.320 32.760 28.380 ;
        RECT 45.020 23.320 46.350 28.380 ;
        RECT 46.700 27.930 47.080 28.380 ;
        RECT 54.160 23.320 55.490 28.380 ;
        RECT 70.580 23.320 71.910 28.380 ;
        RECT 76.910 23.320 78.240 28.380 ;
        RECT 83.220 23.320 84.550 28.380 ;
        RECT 31.430 21.980 172.555 23.320 ;
        RECT 31.430 13.885 32.760 21.980 ;
        RECT 45.020 13.885 46.350 21.980 ;
        RECT 54.160 13.885 55.490 21.980 ;
        RECT 70.580 13.885 71.910 21.980 ;
        RECT 76.910 13.885 78.240 21.980 ;
        RECT 83.220 13.885 84.550 21.980 ;
        RECT 31.430 12.730 172.555 13.885 ;
        RECT 70.580 12.700 71.910 12.730 ;
        RECT 174.550 5.045 175.860 56.430 ;
  END
END tt_um_SAR_ADC
END LIBRARY

